VERSION 5.8 ;
BUSBITCHARS "[]" ;
DIVIDERCHAR "/" ;
UNITS
    DATABASE MICRONS 1000 ;
END UNITS

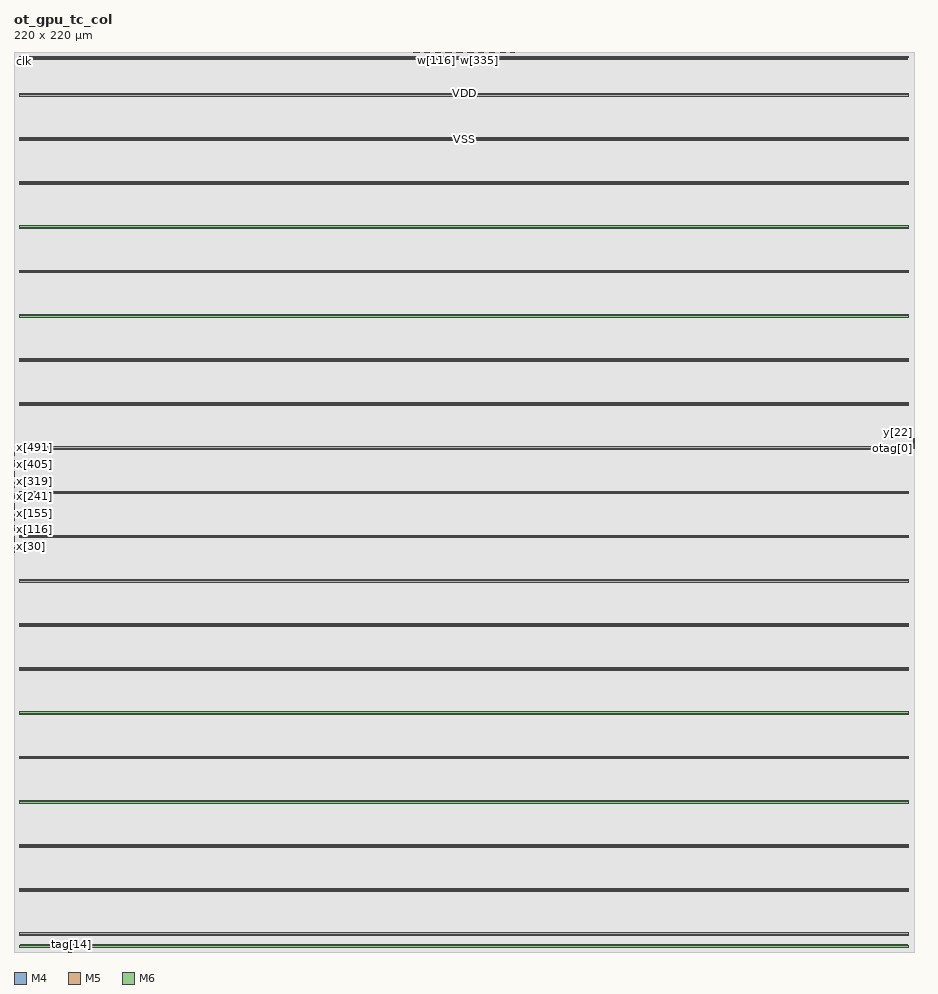
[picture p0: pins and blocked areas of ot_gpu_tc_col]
MACRO ot_gpu_tc_col
  FOREIGN ot_gpu_tc_col 0 0 ;
  CLASS BLOCK ;
  SIZE 220 BY 220 ;
  PIN clk
    DIRECTION INPUT ;
    USE SIGNAL ;
    PORT
      LAYER M4 ;
        RECT  0 217.584 0.084 217.608 ;
    END
  END clk
  PIN fault
    DIRECTION OUTPUT ;
    USE SIGNAL ;
    PORT
      LAYER M4 ;
        RECT  219.916 123.12 220 123.144 ;
    END
  END fault
  PIN first
    DIRECTION INPUT ;
    USE SIGNAL ;
    PORT
      LAYER M5 ;
        RECT  13.2 0 13.224 0.084 ;
    END
  END first
  PIN last
    DIRECTION INPUT ;
    USE SIGNAL ;
    PORT
      LAYER M5 ;
        RECT  13.248 0 13.272 0.084 ;
    END
  END last
  PIN otag[0]
    DIRECTION OUTPUT ;
    USE SIGNAL ;
    PORT
      LAYER M4 ;
        RECT  219.916 123.168 220 123.192 ;
    END
  END otag[0]
  PIN otag[10]
    DIRECTION OUTPUT ;
    USE SIGNAL ;
    PORT
      LAYER M4 ;
        RECT  219.916 123.648 220 123.672 ;
    END
  END otag[10]
  PIN otag[11]
    DIRECTION OUTPUT ;
    USE SIGNAL ;
    PORT
      LAYER M4 ;
        RECT  219.916 123.696 220 123.72 ;
    END
  END otag[11]
  PIN otag[12]
    DIRECTION OUTPUT ;
    USE SIGNAL ;
    PORT
      LAYER M4 ;
        RECT  219.916 123.744 220 123.768 ;
    END
  END otag[12]
  PIN otag[13]
    DIRECTION OUTPUT ;
    USE SIGNAL ;
    PORT
      LAYER M4 ;
        RECT  219.916 123.792 220 123.816 ;
    END
  END otag[13]
  PIN otag[14]
    DIRECTION OUTPUT ;
    USE SIGNAL ;
    PORT
      LAYER M4 ;
        RECT  219.916 123.84 220 123.864 ;
    END
  END otag[14]
  PIN otag[15]
    DIRECTION OUTPUT ;
    USE SIGNAL ;
    PORT
      LAYER M4 ;
        RECT  219.916 123.888 220 123.912 ;
    END
  END otag[15]
  PIN otag[1]
    DIRECTION OUTPUT ;
    USE SIGNAL ;
    PORT
      LAYER M4 ;
        RECT  219.916 123.216 220 123.24 ;
    END
  END otag[1]
  PIN otag[2]
    DIRECTION OUTPUT ;
    USE SIGNAL ;
    PORT
      LAYER M4 ;
        RECT  219.916 123.264 220 123.288 ;
    END
  END otag[2]
  PIN otag[3]
    DIRECTION OUTPUT ;
    USE SIGNAL ;
    PORT
      LAYER M4 ;
        RECT  219.916 123.312 220 123.336 ;
    END
  END otag[3]
  PIN otag[4]
    DIRECTION OUTPUT ;
    USE SIGNAL ;
    PORT
      LAYER M4 ;
        RECT  219.916 123.36 220 123.384 ;
    END
  END otag[4]
  PIN otag[5]
    DIRECTION OUTPUT ;
    USE SIGNAL ;
    PORT
      LAYER M4 ;
        RECT  219.916 123.408 220 123.432 ;
    END
  END otag[5]
  PIN otag[6]
    DIRECTION OUTPUT ;
    USE SIGNAL ;
    PORT
      LAYER M4 ;
        RECT  219.916 123.456 220 123.48 ;
    END
  END otag[6]
  PIN otag[7]
    DIRECTION OUTPUT ;
    USE SIGNAL ;
    PORT
      LAYER M4 ;
        RECT  219.916 123.504 220 123.528 ;
    END
  END otag[7]
  PIN otag[8]
    DIRECTION OUTPUT ;
    USE SIGNAL ;
    PORT
      LAYER M4 ;
        RECT  219.916 123.552 220 123.576 ;
    END
  END otag[8]
  PIN otag[9]
    DIRECTION OUTPUT ;
    USE SIGNAL ;
    PORT
      LAYER M4 ;
        RECT  219.916 123.6 220 123.624 ;
    END
  END otag[9]
  PIN ov
    DIRECTION OUTPUT ;
    USE SIGNAL ;
    PORT
      LAYER M4 ;
        RECT  219.916 123.936 220 123.96 ;
    END
  END ov
  PIN rst_n
    DIRECTION INPUT ;
    USE SIGNAL ;
    PORT
      LAYER M5 ;
        RECT  13.296 0 13.32 0.084 ;
    END
  END rst_n
  PIN tag[0]
    DIRECTION INPUT ;
    USE SIGNAL ;
    PORT
      LAYER M5 ;
        RECT  13.344 0 13.368 0.084 ;
    END
  END tag[0]
  PIN tag[10]
    DIRECTION INPUT ;
    USE SIGNAL ;
    PORT
      LAYER M5 ;
        RECT  13.824 0 13.848 0.084 ;
    END
  END tag[10]
  PIN tag[11]
    DIRECTION INPUT ;
    USE SIGNAL ;
    PORT
      LAYER M5 ;
        RECT  13.872 0 13.896 0.084 ;
    END
  END tag[11]
  PIN tag[12]
    DIRECTION INPUT ;
    USE SIGNAL ;
    PORT
      LAYER M5 ;
        RECT  13.92 0 13.944 0.084 ;
    END
  END tag[12]
  PIN tag[13]
    DIRECTION INPUT ;
    USE SIGNAL ;
    PORT
      LAYER M5 ;
        RECT  13.968 0 13.992 0.084 ;
    END
  END tag[13]
  PIN tag[14]
    DIRECTION INPUT ;
    USE SIGNAL ;
    PORT
      LAYER M5 ;
        RECT  14.016 0 14.04 0.084 ;
    END
  END tag[14]
  PIN tag[15]
    DIRECTION INPUT ;
    USE SIGNAL ;
    PORT
      LAYER M5 ;
        RECT  14.064 0 14.088 0.084 ;
    END
  END tag[15]
  PIN tag[1]
    DIRECTION INPUT ;
    USE SIGNAL ;
    PORT
      LAYER M5 ;
        RECT  13.392 0 13.416 0.084 ;
    END
  END tag[1]
  PIN tag[2]
    DIRECTION INPUT ;
    USE SIGNAL ;
    PORT
      LAYER M5 ;
        RECT  13.44 0 13.464 0.084 ;
    END
  END tag[2]
  PIN tag[3]
    DIRECTION INPUT ;
    USE SIGNAL ;
    PORT
      LAYER M5 ;
        RECT  13.488 0 13.512 0.084 ;
    END
  END tag[3]
  PIN tag[4]
    DIRECTION INPUT ;
    USE SIGNAL ;
    PORT
      LAYER M5 ;
        RECT  13.536 0 13.56 0.084 ;
    END
  END tag[4]
  PIN tag[5]
    DIRECTION INPUT ;
    USE SIGNAL ;
    PORT
      LAYER M5 ;
        RECT  13.584 0 13.608 0.084 ;
    END
  END tag[5]
  PIN tag[6]
    DIRECTION INPUT ;
    USE SIGNAL ;
    PORT
      LAYER M5 ;
        RECT  13.632 0 13.656 0.084 ;
    END
  END tag[6]
  PIN tag[7]
    DIRECTION INPUT ;
    USE SIGNAL ;
    PORT
      LAYER M5 ;
        RECT  13.68 0 13.704 0.084 ;
    END
  END tag[7]
  PIN tag[8]
    DIRECTION INPUT ;
    USE SIGNAL ;
    PORT
      LAYER M5 ;
        RECT  13.728 0 13.752 0.084 ;
    END
  END tag[8]
  PIN tag[9]
    DIRECTION INPUT ;
    USE SIGNAL ;
    PORT
      LAYER M5 ;
        RECT  13.776 0 13.8 0.084 ;
    END
  END tag[9]
  PIN v
    DIRECTION INPUT ;
    USE SIGNAL ;
    PORT
      LAYER M5 ;
        RECT  14.112 0 14.136 0.084 ;
    END
  END v
  PIN w[0]
    DIRECTION INPUT ;
    USE SIGNAL ;
    PORT
      LAYER M5 ;
        RECT  97.728 219.916 97.752 220 ;
    END
  END w[0]
  PIN w[100]
    DIRECTION INPUT ;
    USE SIGNAL ;
    PORT
      LAYER M5 ;
        RECT  102.528 219.916 102.552 220 ;
    END
  END w[100]
  PIN w[101]
    DIRECTION INPUT ;
    USE SIGNAL ;
    PORT
      LAYER M5 ;
        RECT  102.576 219.916 102.6 220 ;
    END
  END w[101]
  PIN w[102]
    DIRECTION INPUT ;
    USE SIGNAL ;
    PORT
      LAYER M5 ;
        RECT  102.624 219.916 102.648 220 ;
    END
  END w[102]
  PIN w[103]
    DIRECTION INPUT ;
    USE SIGNAL ;
    PORT
      LAYER M5 ;
        RECT  102.672 219.916 102.696 220 ;
    END
  END w[103]
  PIN w[104]
    DIRECTION INPUT ;
    USE SIGNAL ;
    PORT
      LAYER M5 ;
        RECT  102.72 219.916 102.744 220 ;
    END
  END w[104]
  PIN w[105]
    DIRECTION INPUT ;
    USE SIGNAL ;
    PORT
      LAYER M5 ;
        RECT  102.768 219.916 102.792 220 ;
    END
  END w[105]
  PIN w[106]
    DIRECTION INPUT ;
    USE SIGNAL ;
    PORT
      LAYER M5 ;
        RECT  102.816 219.916 102.84 220 ;
    END
  END w[106]
  PIN w[107]
    DIRECTION INPUT ;
    USE SIGNAL ;
    PORT
      LAYER M5 ;
        RECT  102.864 219.916 102.888 220 ;
    END
  END w[107]
  PIN w[108]
    DIRECTION INPUT ;
    USE SIGNAL ;
    PORT
      LAYER M5 ;
        RECT  102.912 219.916 102.936 220 ;
    END
  END w[108]
  PIN w[109]
    DIRECTION INPUT ;
    USE SIGNAL ;
    PORT
      LAYER M5 ;
        RECT  102.96 219.916 102.984 220 ;
    END
  END w[109]
  PIN w[10]
    DIRECTION INPUT ;
    USE SIGNAL ;
    PORT
      LAYER M5 ;
        RECT  98.208 219.916 98.232 220 ;
    END
  END w[10]
  PIN w[110]
    DIRECTION INPUT ;
    USE SIGNAL ;
    PORT
      LAYER M5 ;
        RECT  103.008 219.916 103.032 220 ;
    END
  END w[110]
  PIN w[111]
    DIRECTION INPUT ;
    USE SIGNAL ;
    PORT
      LAYER M5 ;
        RECT  103.056 219.916 103.08 220 ;
    END
  END w[111]
  PIN w[112]
    DIRECTION INPUT ;
    USE SIGNAL ;
    PORT
      LAYER M5 ;
        RECT  103.104 219.916 103.128 220 ;
    END
  END w[112]
  PIN w[113]
    DIRECTION INPUT ;
    USE SIGNAL ;
    PORT
      LAYER M5 ;
        RECT  103.152 219.916 103.176 220 ;
    END
  END w[113]
  PIN w[114]
    DIRECTION INPUT ;
    USE SIGNAL ;
    PORT
      LAYER M5 ;
        RECT  103.2 219.916 103.224 220 ;
    END
  END w[114]
  PIN w[115]
    DIRECTION INPUT ;
    USE SIGNAL ;
    PORT
      LAYER M5 ;
        RECT  103.248 219.916 103.272 220 ;
    END
  END w[115]
  PIN w[116]
    DIRECTION INPUT ;
    USE SIGNAL ;
    PORT
      LAYER M5 ;
        RECT  103.296 219.916 103.32 220 ;
    END
  END w[116]
  PIN w[117]
    DIRECTION INPUT ;
    USE SIGNAL ;
    PORT
      LAYER M5 ;
        RECT  103.344 219.916 103.368 220 ;
    END
  END w[117]
  PIN w[118]
    DIRECTION INPUT ;
    USE SIGNAL ;
    PORT
      LAYER M5 ;
        RECT  103.392 219.916 103.416 220 ;
    END
  END w[118]
  PIN w[119]
    DIRECTION INPUT ;
    USE SIGNAL ;
    PORT
      LAYER M5 ;
        RECT  103.44 219.916 103.464 220 ;
    END
  END w[119]
  PIN w[11]
    DIRECTION INPUT ;
    USE SIGNAL ;
    PORT
      LAYER M5 ;
        RECT  98.256 219.916 98.28 220 ;
    END
  END w[11]
  PIN w[120]
    DIRECTION INPUT ;
    USE SIGNAL ;
    PORT
      LAYER M5 ;
        RECT  103.488 219.916 103.512 220 ;
    END
  END w[120]
  PIN w[121]
    DIRECTION INPUT ;
    USE SIGNAL ;
    PORT
      LAYER M5 ;
        RECT  103.536 219.916 103.56 220 ;
    END
  END w[121]
  PIN w[122]
    DIRECTION INPUT ;
    USE SIGNAL ;
    PORT
      LAYER M5 ;
        RECT  103.584 219.916 103.608 220 ;
    END
  END w[122]
  PIN w[123]
    DIRECTION INPUT ;
    USE SIGNAL ;
    PORT
      LAYER M5 ;
        RECT  103.632 219.916 103.656 220 ;
    END
  END w[123]
  PIN w[124]
    DIRECTION INPUT ;
    USE SIGNAL ;
    PORT
      LAYER M5 ;
        RECT  103.68 219.916 103.704 220 ;
    END
  END w[124]
  PIN w[125]
    DIRECTION INPUT ;
    USE SIGNAL ;
    PORT
      LAYER M5 ;
        RECT  103.728 219.916 103.752 220 ;
    END
  END w[125]
  PIN w[126]
    DIRECTION INPUT ;
    USE SIGNAL ;
    PORT
      LAYER M5 ;
        RECT  103.776 219.916 103.8 220 ;
    END
  END w[126]
  PIN w[127]
    DIRECTION INPUT ;
    USE SIGNAL ;
    PORT
      LAYER M5 ;
        RECT  103.824 219.916 103.848 220 ;
    END
  END w[127]
  PIN w[128]
    DIRECTION INPUT ;
    USE SIGNAL ;
    PORT
      LAYER M5 ;
        RECT  103.872 219.916 103.896 220 ;
    END
  END w[128]
  PIN w[129]
    DIRECTION INPUT ;
    USE SIGNAL ;
    PORT
      LAYER M5 ;
        RECT  103.92 219.916 103.944 220 ;
    END
  END w[129]
  PIN w[12]
    DIRECTION INPUT ;
    USE SIGNAL ;
    PORT
      LAYER M5 ;
        RECT  98.304 219.916 98.328 220 ;
    END
  END w[12]
  PIN w[130]
    DIRECTION INPUT ;
    USE SIGNAL ;
    PORT
      LAYER M5 ;
        RECT  103.968 219.916 103.992 220 ;
    END
  END w[130]
  PIN w[131]
    DIRECTION INPUT ;
    USE SIGNAL ;
    PORT
      LAYER M5 ;
        RECT  104.016 219.916 104.04 220 ;
    END
  END w[131]
  PIN w[132]
    DIRECTION INPUT ;
    USE SIGNAL ;
    PORT
      LAYER M5 ;
        RECT  104.064 219.916 104.088 220 ;
    END
  END w[132]
  PIN w[133]
    DIRECTION INPUT ;
    USE SIGNAL ;
    PORT
      LAYER M5 ;
        RECT  104.112 219.916 104.136 220 ;
    END
  END w[133]
  PIN w[134]
    DIRECTION INPUT ;
    USE SIGNAL ;
    PORT
      LAYER M5 ;
        RECT  104.16 219.916 104.184 220 ;
    END
  END w[134]
  PIN w[135]
    DIRECTION INPUT ;
    USE SIGNAL ;
    PORT
      LAYER M5 ;
        RECT  104.208 219.916 104.232 220 ;
    END
  END w[135]
  PIN w[136]
    DIRECTION INPUT ;
    USE SIGNAL ;
    PORT
      LAYER M5 ;
        RECT  104.256 219.916 104.28 220 ;
    END
  END w[136]
  PIN w[137]
    DIRECTION INPUT ;
    USE SIGNAL ;
    PORT
      LAYER M5 ;
        RECT  104.304 219.916 104.328 220 ;
    END
  END w[137]
  PIN w[138]
    DIRECTION INPUT ;
    USE SIGNAL ;
    PORT
      LAYER M5 ;
        RECT  104.352 219.916 104.376 220 ;
    END
  END w[138]
  PIN w[139]
    DIRECTION INPUT ;
    USE SIGNAL ;
    PORT
      LAYER M5 ;
        RECT  104.4 219.916 104.424 220 ;
    END
  END w[139]
  PIN w[13]
    DIRECTION INPUT ;
    USE SIGNAL ;
    PORT
      LAYER M5 ;
        RECT  98.352 219.916 98.376 220 ;
    END
  END w[13]
  PIN w[140]
    DIRECTION INPUT ;
    USE SIGNAL ;
    PORT
      LAYER M5 ;
        RECT  104.448 219.916 104.472 220 ;
    END
  END w[140]
  PIN w[141]
    DIRECTION INPUT ;
    USE SIGNAL ;
    PORT
      LAYER M5 ;
        RECT  104.496 219.916 104.52 220 ;
    END
  END w[141]
  PIN w[142]
    DIRECTION INPUT ;
    USE SIGNAL ;
    PORT
      LAYER M5 ;
        RECT  104.544 219.916 104.568 220 ;
    END
  END w[142]
  PIN w[143]
    DIRECTION INPUT ;
    USE SIGNAL ;
    PORT
      LAYER M5 ;
        RECT  104.592 219.916 104.616 220 ;
    END
  END w[143]
  PIN w[144]
    DIRECTION INPUT ;
    USE SIGNAL ;
    PORT
      LAYER M5 ;
        RECT  104.64 219.916 104.664 220 ;
    END
  END w[144]
  PIN w[145]
    DIRECTION INPUT ;
    USE SIGNAL ;
    PORT
      LAYER M5 ;
        RECT  104.688 219.916 104.712 220 ;
    END
  END w[145]
  PIN w[146]
    DIRECTION INPUT ;
    USE SIGNAL ;
    PORT
      LAYER M5 ;
        RECT  104.736 219.916 104.76 220 ;
    END
  END w[146]
  PIN w[147]
    DIRECTION INPUT ;
    USE SIGNAL ;
    PORT
      LAYER M5 ;
        RECT  104.784 219.916 104.808 220 ;
    END
  END w[147]
  PIN w[148]
    DIRECTION INPUT ;
    USE SIGNAL ;
    PORT
      LAYER M5 ;
        RECT  104.832 219.916 104.856 220 ;
    END
  END w[148]
  PIN w[149]
    DIRECTION INPUT ;
    USE SIGNAL ;
    PORT
      LAYER M5 ;
        RECT  104.88 219.916 104.904 220 ;
    END
  END w[149]
  PIN w[14]
    DIRECTION INPUT ;
    USE SIGNAL ;
    PORT
      LAYER M5 ;
        RECT  98.4 219.916 98.424 220 ;
    END
  END w[14]
  PIN w[150]
    DIRECTION INPUT ;
    USE SIGNAL ;
    PORT
      LAYER M5 ;
        RECT  104.928 219.916 104.952 220 ;
    END
  END w[150]
  PIN w[151]
    DIRECTION INPUT ;
    USE SIGNAL ;
    PORT
      LAYER M5 ;
        RECT  104.976 219.916 105 220 ;
    END
  END w[151]
  PIN w[152]
    DIRECTION INPUT ;
    USE SIGNAL ;
    PORT
      LAYER M5 ;
        RECT  105.024 219.916 105.048 220 ;
    END
  END w[152]
  PIN w[153]
    DIRECTION INPUT ;
    USE SIGNAL ;
    PORT
      LAYER M5 ;
        RECT  105.072 219.916 105.096 220 ;
    END
  END w[153]
  PIN w[154]
    DIRECTION INPUT ;
    USE SIGNAL ;
    PORT
      LAYER M5 ;
        RECT  105.12 219.916 105.144 220 ;
    END
  END w[154]
  PIN w[155]
    DIRECTION INPUT ;
    USE SIGNAL ;
    PORT
      LAYER M5 ;
        RECT  105.168 219.916 105.192 220 ;
    END
  END w[155]
  PIN w[156]
    DIRECTION INPUT ;
    USE SIGNAL ;
    PORT
      LAYER M5 ;
        RECT  105.216 219.916 105.24 220 ;
    END
  END w[156]
  PIN w[157]
    DIRECTION INPUT ;
    USE SIGNAL ;
    PORT
      LAYER M5 ;
        RECT  105.264 219.916 105.288 220 ;
    END
  END w[157]
  PIN w[158]
    DIRECTION INPUT ;
    USE SIGNAL ;
    PORT
      LAYER M5 ;
        RECT  105.312 219.916 105.336 220 ;
    END
  END w[158]
  PIN w[159]
    DIRECTION INPUT ;
    USE SIGNAL ;
    PORT
      LAYER M5 ;
        RECT  105.36 219.916 105.384 220 ;
    END
  END w[159]
  PIN w[15]
    DIRECTION INPUT ;
    USE SIGNAL ;
    PORT
      LAYER M5 ;
        RECT  98.448 219.916 98.472 220 ;
    END
  END w[15]
  PIN w[160]
    DIRECTION INPUT ;
    USE SIGNAL ;
    PORT
      LAYER M5 ;
        RECT  105.408 219.916 105.432 220 ;
    END
  END w[160]
  PIN w[161]
    DIRECTION INPUT ;
    USE SIGNAL ;
    PORT
      LAYER M5 ;
        RECT  105.456 219.916 105.48 220 ;
    END
  END w[161]
  PIN w[162]
    DIRECTION INPUT ;
    USE SIGNAL ;
    PORT
      LAYER M5 ;
        RECT  105.504 219.916 105.528 220 ;
    END
  END w[162]
  PIN w[163]
    DIRECTION INPUT ;
    USE SIGNAL ;
    PORT
      LAYER M5 ;
        RECT  105.552 219.916 105.576 220 ;
    END
  END w[163]
  PIN w[164]
    DIRECTION INPUT ;
    USE SIGNAL ;
    PORT
      LAYER M5 ;
        RECT  105.6 219.916 105.624 220 ;
    END
  END w[164]
  PIN w[165]
    DIRECTION INPUT ;
    USE SIGNAL ;
    PORT
      LAYER M5 ;
        RECT  105.648 219.916 105.672 220 ;
    END
  END w[165]
  PIN w[166]
    DIRECTION INPUT ;
    USE SIGNAL ;
    PORT
      LAYER M5 ;
        RECT  105.696 219.916 105.72 220 ;
    END
  END w[166]
  PIN w[167]
    DIRECTION INPUT ;
    USE SIGNAL ;
    PORT
      LAYER M5 ;
        RECT  105.744 219.916 105.768 220 ;
    END
  END w[167]
  PIN w[168]
    DIRECTION INPUT ;
    USE SIGNAL ;
    PORT
      LAYER M5 ;
        RECT  105.792 219.916 105.816 220 ;
    END
  END w[168]
  PIN w[169]
    DIRECTION INPUT ;
    USE SIGNAL ;
    PORT
      LAYER M5 ;
        RECT  105.84 219.916 105.864 220 ;
    END
  END w[169]
  PIN w[16]
    DIRECTION INPUT ;
    USE SIGNAL ;
    PORT
      LAYER M5 ;
        RECT  98.496 219.916 98.52 220 ;
    END
  END w[16]
  PIN w[170]
    DIRECTION INPUT ;
    USE SIGNAL ;
    PORT
      LAYER M5 ;
        RECT  105.888 219.916 105.912 220 ;
    END
  END w[170]
  PIN w[171]
    DIRECTION INPUT ;
    USE SIGNAL ;
    PORT
      LAYER M5 ;
        RECT  105.936 219.916 105.96 220 ;
    END
  END w[171]
  PIN w[172]
    DIRECTION INPUT ;
    USE SIGNAL ;
    PORT
      LAYER M5 ;
        RECT  105.984 219.916 106.008 220 ;
    END
  END w[172]
  PIN w[173]
    DIRECTION INPUT ;
    USE SIGNAL ;
    PORT
      LAYER M5 ;
        RECT  106.032 219.916 106.056 220 ;
    END
  END w[173]
  PIN w[174]
    DIRECTION INPUT ;
    USE SIGNAL ;
    PORT
      LAYER M5 ;
        RECT  106.08 219.916 106.104 220 ;
    END
  END w[174]
  PIN w[175]
    DIRECTION INPUT ;
    USE SIGNAL ;
    PORT
      LAYER M5 ;
        RECT  106.128 219.916 106.152 220 ;
    END
  END w[175]
  PIN w[176]
    DIRECTION INPUT ;
    USE SIGNAL ;
    PORT
      LAYER M5 ;
        RECT  106.176 219.916 106.2 220 ;
    END
  END w[176]
  PIN w[177]
    DIRECTION INPUT ;
    USE SIGNAL ;
    PORT
      LAYER M5 ;
        RECT  106.224 219.916 106.248 220 ;
    END
  END w[177]
  PIN w[178]
    DIRECTION INPUT ;
    USE SIGNAL ;
    PORT
      LAYER M5 ;
        RECT  106.272 219.916 106.296 220 ;
    END
  END w[178]
  PIN w[179]
    DIRECTION INPUT ;
    USE SIGNAL ;
    PORT
      LAYER M5 ;
        RECT  106.32 219.916 106.344 220 ;
    END
  END w[179]
  PIN w[17]
    DIRECTION INPUT ;
    USE SIGNAL ;
    PORT
      LAYER M5 ;
        RECT  98.544 219.916 98.568 220 ;
    END
  END w[17]
  PIN w[180]
    DIRECTION INPUT ;
    USE SIGNAL ;
    PORT
      LAYER M5 ;
        RECT  106.368 219.916 106.392 220 ;
    END
  END w[180]
  PIN w[181]
    DIRECTION INPUT ;
    USE SIGNAL ;
    PORT
      LAYER M5 ;
        RECT  106.416 219.916 106.44 220 ;
    END
  END w[181]
  PIN w[182]
    DIRECTION INPUT ;
    USE SIGNAL ;
    PORT
      LAYER M5 ;
        RECT  106.464 219.916 106.488 220 ;
    END
  END w[182]
  PIN w[183]
    DIRECTION INPUT ;
    USE SIGNAL ;
    PORT
      LAYER M5 ;
        RECT  106.512 219.916 106.536 220 ;
    END
  END w[183]
  PIN w[184]
    DIRECTION INPUT ;
    USE SIGNAL ;
    PORT
      LAYER M5 ;
        RECT  106.56 219.916 106.584 220 ;
    END
  END w[184]
  PIN w[185]
    DIRECTION INPUT ;
    USE SIGNAL ;
    PORT
      LAYER M5 ;
        RECT  106.608 219.916 106.632 220 ;
    END
  END w[185]
  PIN w[186]
    DIRECTION INPUT ;
    USE SIGNAL ;
    PORT
      LAYER M5 ;
        RECT  106.656 219.916 106.68 220 ;
    END
  END w[186]
  PIN w[187]
    DIRECTION INPUT ;
    USE SIGNAL ;
    PORT
      LAYER M5 ;
        RECT  106.704 219.916 106.728 220 ;
    END
  END w[187]
  PIN w[188]
    DIRECTION INPUT ;
    USE SIGNAL ;
    PORT
      LAYER M5 ;
        RECT  106.752 219.916 106.776 220 ;
    END
  END w[188]
  PIN w[189]
    DIRECTION INPUT ;
    USE SIGNAL ;
    PORT
      LAYER M5 ;
        RECT  106.8 219.916 106.824 220 ;
    END
  END w[189]
  PIN w[18]
    DIRECTION INPUT ;
    USE SIGNAL ;
    PORT
      LAYER M5 ;
        RECT  98.592 219.916 98.616 220 ;
    END
  END w[18]
  PIN w[190]
    DIRECTION INPUT ;
    USE SIGNAL ;
    PORT
      LAYER M5 ;
        RECT  106.848 219.916 106.872 220 ;
    END
  END w[190]
  PIN w[191]
    DIRECTION INPUT ;
    USE SIGNAL ;
    PORT
      LAYER M5 ;
        RECT  106.896 219.916 106.92 220 ;
    END
  END w[191]
  PIN w[192]
    DIRECTION INPUT ;
    USE SIGNAL ;
    PORT
      LAYER M5 ;
        RECT  106.944 219.916 106.968 220 ;
    END
  END w[192]
  PIN w[193]
    DIRECTION INPUT ;
    USE SIGNAL ;
    PORT
      LAYER M5 ;
        RECT  106.992 219.916 107.016 220 ;
    END
  END w[193]
  PIN w[194]
    DIRECTION INPUT ;
    USE SIGNAL ;
    PORT
      LAYER M5 ;
        RECT  107.04 219.916 107.064 220 ;
    END
  END w[194]
  PIN w[195]
    DIRECTION INPUT ;
    USE SIGNAL ;
    PORT
      LAYER M5 ;
        RECT  107.088 219.916 107.112 220 ;
    END
  END w[195]
  PIN w[196]
    DIRECTION INPUT ;
    USE SIGNAL ;
    PORT
      LAYER M5 ;
        RECT  107.136 219.916 107.16 220 ;
    END
  END w[196]
  PIN w[197]
    DIRECTION INPUT ;
    USE SIGNAL ;
    PORT
      LAYER M5 ;
        RECT  107.184 219.916 107.208 220 ;
    END
  END w[197]
  PIN w[198]
    DIRECTION INPUT ;
    USE SIGNAL ;
    PORT
      LAYER M5 ;
        RECT  107.232 219.916 107.256 220 ;
    END
  END w[198]
  PIN w[199]
    DIRECTION INPUT ;
    USE SIGNAL ;
    PORT
      LAYER M5 ;
        RECT  107.28 219.916 107.304 220 ;
    END
  END w[199]
  PIN w[19]
    DIRECTION INPUT ;
    USE SIGNAL ;
    PORT
      LAYER M5 ;
        RECT  98.64 219.916 98.664 220 ;
    END
  END w[19]
  PIN w[1]
    DIRECTION INPUT ;
    USE SIGNAL ;
    PORT
      LAYER M5 ;
        RECT  97.776 219.916 97.8 220 ;
    END
  END w[1]
  PIN w[200]
    DIRECTION INPUT ;
    USE SIGNAL ;
    PORT
      LAYER M5 ;
        RECT  107.328 219.916 107.352 220 ;
    END
  END w[200]
  PIN w[201]
    DIRECTION INPUT ;
    USE SIGNAL ;
    PORT
      LAYER M5 ;
        RECT  107.376 219.916 107.4 220 ;
    END
  END w[201]
  PIN w[202]
    DIRECTION INPUT ;
    USE SIGNAL ;
    PORT
      LAYER M5 ;
        RECT  107.424 219.916 107.448 220 ;
    END
  END w[202]
  PIN w[203]
    DIRECTION INPUT ;
    USE SIGNAL ;
    PORT
      LAYER M5 ;
        RECT  107.472 219.916 107.496 220 ;
    END
  END w[203]
  PIN w[204]
    DIRECTION INPUT ;
    USE SIGNAL ;
    PORT
      LAYER M5 ;
        RECT  107.52 219.916 107.544 220 ;
    END
  END w[204]
  PIN w[205]
    DIRECTION INPUT ;
    USE SIGNAL ;
    PORT
      LAYER M5 ;
        RECT  107.568 219.916 107.592 220 ;
    END
  END w[205]
  PIN w[206]
    DIRECTION INPUT ;
    USE SIGNAL ;
    PORT
      LAYER M5 ;
        RECT  107.616 219.916 107.64 220 ;
    END
  END w[206]
  PIN w[207]
    DIRECTION INPUT ;
    USE SIGNAL ;
    PORT
      LAYER M5 ;
        RECT  107.664 219.916 107.688 220 ;
    END
  END w[207]
  PIN w[208]
    DIRECTION INPUT ;
    USE SIGNAL ;
    PORT
      LAYER M5 ;
        RECT  107.712 219.916 107.736 220 ;
    END
  END w[208]
  PIN w[209]
    DIRECTION INPUT ;
    USE SIGNAL ;
    PORT
      LAYER M5 ;
        RECT  107.76 219.916 107.784 220 ;
    END
  END w[209]
  PIN w[20]
    DIRECTION INPUT ;
    USE SIGNAL ;
    PORT
      LAYER M5 ;
        RECT  98.688 219.916 98.712 220 ;
    END
  END w[20]
  PIN w[210]
    DIRECTION INPUT ;
    USE SIGNAL ;
    PORT
      LAYER M5 ;
        RECT  107.808 219.916 107.832 220 ;
    END
  END w[210]
  PIN w[211]
    DIRECTION INPUT ;
    USE SIGNAL ;
    PORT
      LAYER M5 ;
        RECT  107.856 219.916 107.88 220 ;
    END
  END w[211]
  PIN w[212]
    DIRECTION INPUT ;
    USE SIGNAL ;
    PORT
      LAYER M5 ;
        RECT  107.904 219.916 107.928 220 ;
    END
  END w[212]
  PIN w[213]
    DIRECTION INPUT ;
    USE SIGNAL ;
    PORT
      LAYER M5 ;
        RECT  107.952 219.916 107.976 220 ;
    END
  END w[213]
  PIN w[214]
    DIRECTION INPUT ;
    USE SIGNAL ;
    PORT
      LAYER M5 ;
        RECT  108 219.916 108.024 220 ;
    END
  END w[214]
  PIN w[215]
    DIRECTION INPUT ;
    USE SIGNAL ;
    PORT
      LAYER M5 ;
        RECT  108.048 219.916 108.072 220 ;
    END
  END w[215]
  PIN w[216]
    DIRECTION INPUT ;
    USE SIGNAL ;
    PORT
      LAYER M5 ;
        RECT  108.096 219.916 108.12 220 ;
    END
  END w[216]
  PIN w[217]
    DIRECTION INPUT ;
    USE SIGNAL ;
    PORT
      LAYER M5 ;
        RECT  108.144 219.916 108.168 220 ;
    END
  END w[217]
  PIN w[218]
    DIRECTION INPUT ;
    USE SIGNAL ;
    PORT
      LAYER M5 ;
        RECT  108.192 219.916 108.216 220 ;
    END
  END w[218]
  PIN w[219]
    DIRECTION INPUT ;
    USE SIGNAL ;
    PORT
      LAYER M5 ;
        RECT  108.24 219.916 108.264 220 ;
    END
  END w[219]
  PIN w[21]
    DIRECTION INPUT ;
    USE SIGNAL ;
    PORT
      LAYER M5 ;
        RECT  98.736 219.916 98.76 220 ;
    END
  END w[21]
  PIN w[220]
    DIRECTION INPUT ;
    USE SIGNAL ;
    PORT
      LAYER M5 ;
        RECT  108.288 219.916 108.312 220 ;
    END
  END w[220]
  PIN w[221]
    DIRECTION INPUT ;
    USE SIGNAL ;
    PORT
      LAYER M5 ;
        RECT  108.336 219.916 108.36 220 ;
    END
  END w[221]
  PIN w[222]
    DIRECTION INPUT ;
    USE SIGNAL ;
    PORT
      LAYER M5 ;
        RECT  108.384 219.916 108.408 220 ;
    END
  END w[222]
  PIN w[223]
    DIRECTION INPUT ;
    USE SIGNAL ;
    PORT
      LAYER M5 ;
        RECT  108.432 219.916 108.456 220 ;
    END
  END w[223]
  PIN w[224]
    DIRECTION INPUT ;
    USE SIGNAL ;
    PORT
      LAYER M5 ;
        RECT  108.48 219.916 108.504 220 ;
    END
  END w[224]
  PIN w[225]
    DIRECTION INPUT ;
    USE SIGNAL ;
    PORT
      LAYER M5 ;
        RECT  108.528 219.916 108.552 220 ;
    END
  END w[225]
  PIN w[226]
    DIRECTION INPUT ;
    USE SIGNAL ;
    PORT
      LAYER M5 ;
        RECT  108.576 219.916 108.6 220 ;
    END
  END w[226]
  PIN w[227]
    DIRECTION INPUT ;
    USE SIGNAL ;
    PORT
      LAYER M5 ;
        RECT  108.624 219.916 108.648 220 ;
    END
  END w[227]
  PIN w[228]
    DIRECTION INPUT ;
    USE SIGNAL ;
    PORT
      LAYER M5 ;
        RECT  108.672 219.916 108.696 220 ;
    END
  END w[228]
  PIN w[229]
    DIRECTION INPUT ;
    USE SIGNAL ;
    PORT
      LAYER M5 ;
        RECT  108.72 219.916 108.744 220 ;
    END
  END w[229]
  PIN w[22]
    DIRECTION INPUT ;
    USE SIGNAL ;
    PORT
      LAYER M5 ;
        RECT  98.784 219.916 98.808 220 ;
    END
  END w[22]
  PIN w[230]
    DIRECTION INPUT ;
    USE SIGNAL ;
    PORT
      LAYER M5 ;
        RECT  108.768 219.916 108.792 220 ;
    END
  END w[230]
  PIN w[231]
    DIRECTION INPUT ;
    USE SIGNAL ;
    PORT
      LAYER M5 ;
        RECT  108.816 219.916 108.84 220 ;
    END
  END w[231]
  PIN w[232]
    DIRECTION INPUT ;
    USE SIGNAL ;
    PORT
      LAYER M5 ;
        RECT  108.864 219.916 108.888 220 ;
    END
  END w[232]
  PIN w[233]
    DIRECTION INPUT ;
    USE SIGNAL ;
    PORT
      LAYER M5 ;
        RECT  108.912 219.916 108.936 220 ;
    END
  END w[233]
  PIN w[234]
    DIRECTION INPUT ;
    USE SIGNAL ;
    PORT
      LAYER M5 ;
        RECT  108.96 219.916 108.984 220 ;
    END
  END w[234]
  PIN w[235]
    DIRECTION INPUT ;
    USE SIGNAL ;
    PORT
      LAYER M5 ;
        RECT  109.008 219.916 109.032 220 ;
    END
  END w[235]
  PIN w[236]
    DIRECTION INPUT ;
    USE SIGNAL ;
    PORT
      LAYER M5 ;
        RECT  109.056 219.916 109.08 220 ;
    END
  END w[236]
  PIN w[237]
    DIRECTION INPUT ;
    USE SIGNAL ;
    PORT
      LAYER M5 ;
        RECT  109.104 219.916 109.128 220 ;
    END
  END w[237]
  PIN w[238]
    DIRECTION INPUT ;
    USE SIGNAL ;
    PORT
      LAYER M5 ;
        RECT  109.152 219.916 109.176 220 ;
    END
  END w[238]
  PIN w[239]
    DIRECTION INPUT ;
    USE SIGNAL ;
    PORT
      LAYER M5 ;
        RECT  109.2 219.916 109.224 220 ;
    END
  END w[239]
  PIN w[23]
    DIRECTION INPUT ;
    USE SIGNAL ;
    PORT
      LAYER M5 ;
        RECT  98.832 219.916 98.856 220 ;
    END
  END w[23]
  PIN w[240]
    DIRECTION INPUT ;
    USE SIGNAL ;
    PORT
      LAYER M5 ;
        RECT  109.248 219.916 109.272 220 ;
    END
  END w[240]
  PIN w[241]
    DIRECTION INPUT ;
    USE SIGNAL ;
    PORT
      LAYER M5 ;
        RECT  109.296 219.916 109.32 220 ;
    END
  END w[241]
  PIN w[242]
    DIRECTION INPUT ;
    USE SIGNAL ;
    PORT
      LAYER M5 ;
        RECT  109.344 219.916 109.368 220 ;
    END
  END w[242]
  PIN w[243]
    DIRECTION INPUT ;
    USE SIGNAL ;
    PORT
      LAYER M5 ;
        RECT  109.392 219.916 109.416 220 ;
    END
  END w[243]
  PIN w[244]
    DIRECTION INPUT ;
    USE SIGNAL ;
    PORT
      LAYER M5 ;
        RECT  109.44 219.916 109.464 220 ;
    END
  END w[244]
  PIN w[245]
    DIRECTION INPUT ;
    USE SIGNAL ;
    PORT
      LAYER M5 ;
        RECT  109.488 219.916 109.512 220 ;
    END
  END w[245]
  PIN w[246]
    DIRECTION INPUT ;
    USE SIGNAL ;
    PORT
      LAYER M5 ;
        RECT  109.536 219.916 109.56 220 ;
    END
  END w[246]
  PIN w[247]
    DIRECTION INPUT ;
    USE SIGNAL ;
    PORT
      LAYER M5 ;
        RECT  109.584 219.916 109.608 220 ;
    END
  END w[247]
  PIN w[248]
    DIRECTION INPUT ;
    USE SIGNAL ;
    PORT
      LAYER M5 ;
        RECT  109.632 219.916 109.656 220 ;
    END
  END w[248]
  PIN w[249]
    DIRECTION INPUT ;
    USE SIGNAL ;
    PORT
      LAYER M5 ;
        RECT  109.68 219.916 109.704 220 ;
    END
  END w[249]
  PIN w[24]
    DIRECTION INPUT ;
    USE SIGNAL ;
    PORT
      LAYER M5 ;
        RECT  98.88 219.916 98.904 220 ;
    END
  END w[24]
  PIN w[250]
    DIRECTION INPUT ;
    USE SIGNAL ;
    PORT
      LAYER M5 ;
        RECT  109.728 219.916 109.752 220 ;
    END
  END w[250]
  PIN w[251]
    DIRECTION INPUT ;
    USE SIGNAL ;
    PORT
      LAYER M5 ;
        RECT  109.776 219.916 109.8 220 ;
    END
  END w[251]
  PIN w[252]
    DIRECTION INPUT ;
    USE SIGNAL ;
    PORT
      LAYER M5 ;
        RECT  109.824 219.916 109.848 220 ;
    END
  END w[252]
  PIN w[253]
    DIRECTION INPUT ;
    USE SIGNAL ;
    PORT
      LAYER M5 ;
        RECT  109.872 219.916 109.896 220 ;
    END
  END w[253]
  PIN w[254]
    DIRECTION INPUT ;
    USE SIGNAL ;
    PORT
      LAYER M5 ;
        RECT  109.92 219.916 109.944 220 ;
    END
  END w[254]
  PIN w[255]
    DIRECTION INPUT ;
    USE SIGNAL ;
    PORT
      LAYER M5 ;
        RECT  109.968 219.916 109.992 220 ;
    END
  END w[255]
  PIN w[256]
    DIRECTION INPUT ;
    USE SIGNAL ;
    PORT
      LAYER M5 ;
        RECT  110.016 219.916 110.04 220 ;
    END
  END w[256]
  PIN w[257]
    DIRECTION INPUT ;
    USE SIGNAL ;
    PORT
      LAYER M5 ;
        RECT  110.064 219.916 110.088 220 ;
    END
  END w[257]
  PIN w[258]
    DIRECTION INPUT ;
    USE SIGNAL ;
    PORT
      LAYER M5 ;
        RECT  110.112 219.916 110.136 220 ;
    END
  END w[258]
  PIN w[259]
    DIRECTION INPUT ;
    USE SIGNAL ;
    PORT
      LAYER M5 ;
        RECT  110.16 219.916 110.184 220 ;
    END
  END w[259]
  PIN w[25]
    DIRECTION INPUT ;
    USE SIGNAL ;
    PORT
      LAYER M5 ;
        RECT  98.928 219.916 98.952 220 ;
    END
  END w[25]
  PIN w[260]
    DIRECTION INPUT ;
    USE SIGNAL ;
    PORT
      LAYER M5 ;
        RECT  110.208 219.916 110.232 220 ;
    END
  END w[260]
  PIN w[261]
    DIRECTION INPUT ;
    USE SIGNAL ;
    PORT
      LAYER M5 ;
        RECT  110.256 219.916 110.28 220 ;
    END
  END w[261]
  PIN w[262]
    DIRECTION INPUT ;
    USE SIGNAL ;
    PORT
      LAYER M5 ;
        RECT  110.304 219.916 110.328 220 ;
    END
  END w[262]
  PIN w[263]
    DIRECTION INPUT ;
    USE SIGNAL ;
    PORT
      LAYER M5 ;
        RECT  110.352 219.916 110.376 220 ;
    END
  END w[263]
  PIN w[264]
    DIRECTION INPUT ;
    USE SIGNAL ;
    PORT
      LAYER M5 ;
        RECT  110.4 219.916 110.424 220 ;
    END
  END w[264]
  PIN w[265]
    DIRECTION INPUT ;
    USE SIGNAL ;
    PORT
      LAYER M5 ;
        RECT  110.448 219.916 110.472 220 ;
    END
  END w[265]
  PIN w[266]
    DIRECTION INPUT ;
    USE SIGNAL ;
    PORT
      LAYER M5 ;
        RECT  110.496 219.916 110.52 220 ;
    END
  END w[266]
  PIN w[267]
    DIRECTION INPUT ;
    USE SIGNAL ;
    PORT
      LAYER M5 ;
        RECT  110.544 219.916 110.568 220 ;
    END
  END w[267]
  PIN w[268]
    DIRECTION INPUT ;
    USE SIGNAL ;
    PORT
      LAYER M5 ;
        RECT  110.592 219.916 110.616 220 ;
    END
  END w[268]
  PIN w[269]
    DIRECTION INPUT ;
    USE SIGNAL ;
    PORT
      LAYER M5 ;
        RECT  110.64 219.916 110.664 220 ;
    END
  END w[269]
  PIN w[26]
    DIRECTION INPUT ;
    USE SIGNAL ;
    PORT
      LAYER M5 ;
        RECT  98.976 219.916 99 220 ;
    END
  END w[26]
  PIN w[270]
    DIRECTION INPUT ;
    USE SIGNAL ;
    PORT
      LAYER M5 ;
        RECT  110.688 219.916 110.712 220 ;
    END
  END w[270]
  PIN w[271]
    DIRECTION INPUT ;
    USE SIGNAL ;
    PORT
      LAYER M5 ;
        RECT  110.736 219.916 110.76 220 ;
    END
  END w[271]
  PIN w[272]
    DIRECTION INPUT ;
    USE SIGNAL ;
    PORT
      LAYER M5 ;
        RECT  110.784 219.916 110.808 220 ;
    END
  END w[272]
  PIN w[273]
    DIRECTION INPUT ;
    USE SIGNAL ;
    PORT
      LAYER M5 ;
        RECT  110.832 219.916 110.856 220 ;
    END
  END w[273]
  PIN w[274]
    DIRECTION INPUT ;
    USE SIGNAL ;
    PORT
      LAYER M5 ;
        RECT  110.88 219.916 110.904 220 ;
    END
  END w[274]
  PIN w[275]
    DIRECTION INPUT ;
    USE SIGNAL ;
    PORT
      LAYER M5 ;
        RECT  110.928 219.916 110.952 220 ;
    END
  END w[275]
  PIN w[276]
    DIRECTION INPUT ;
    USE SIGNAL ;
    PORT
      LAYER M5 ;
        RECT  110.976 219.916 111 220 ;
    END
  END w[276]
  PIN w[277]
    DIRECTION INPUT ;
    USE SIGNAL ;
    PORT
      LAYER M5 ;
        RECT  111.024 219.916 111.048 220 ;
    END
  END w[277]
  PIN w[278]
    DIRECTION INPUT ;
    USE SIGNAL ;
    PORT
      LAYER M5 ;
        RECT  111.072 219.916 111.096 220 ;
    END
  END w[278]
  PIN w[279]
    DIRECTION INPUT ;
    USE SIGNAL ;
    PORT
      LAYER M5 ;
        RECT  111.12 219.916 111.144 220 ;
    END
  END w[279]
  PIN w[27]
    DIRECTION INPUT ;
    USE SIGNAL ;
    PORT
      LAYER M5 ;
        RECT  99.024 219.916 99.048 220 ;
    END
  END w[27]
  PIN w[280]
    DIRECTION INPUT ;
    USE SIGNAL ;
    PORT
      LAYER M5 ;
        RECT  111.168 219.916 111.192 220 ;
    END
  END w[280]
  PIN w[281]
    DIRECTION INPUT ;
    USE SIGNAL ;
    PORT
      LAYER M5 ;
        RECT  111.216 219.916 111.24 220 ;
    END
  END w[281]
  PIN w[282]
    DIRECTION INPUT ;
    USE SIGNAL ;
    PORT
      LAYER M5 ;
        RECT  111.264 219.916 111.288 220 ;
    END
  END w[282]
  PIN w[283]
    DIRECTION INPUT ;
    USE SIGNAL ;
    PORT
      LAYER M5 ;
        RECT  111.312 219.916 111.336 220 ;
    END
  END w[283]
  PIN w[284]
    DIRECTION INPUT ;
    USE SIGNAL ;
    PORT
      LAYER M5 ;
        RECT  111.36 219.916 111.384 220 ;
    END
  END w[284]
  PIN w[285]
    DIRECTION INPUT ;
    USE SIGNAL ;
    PORT
      LAYER M5 ;
        RECT  111.408 219.916 111.432 220 ;
    END
  END w[285]
  PIN w[286]
    DIRECTION INPUT ;
    USE SIGNAL ;
    PORT
      LAYER M5 ;
        RECT  111.456 219.916 111.48 220 ;
    END
  END w[286]
  PIN w[287]
    DIRECTION INPUT ;
    USE SIGNAL ;
    PORT
      LAYER M5 ;
        RECT  111.504 219.916 111.528 220 ;
    END
  END w[287]
  PIN w[288]
    DIRECTION INPUT ;
    USE SIGNAL ;
    PORT
      LAYER M5 ;
        RECT  111.552 219.916 111.576 220 ;
    END
  END w[288]
  PIN w[289]
    DIRECTION INPUT ;
    USE SIGNAL ;
    PORT
      LAYER M5 ;
        RECT  111.6 219.916 111.624 220 ;
    END
  END w[289]
  PIN w[28]
    DIRECTION INPUT ;
    USE SIGNAL ;
    PORT
      LAYER M5 ;
        RECT  99.072 219.916 99.096 220 ;
    END
  END w[28]
  PIN w[290]
    DIRECTION INPUT ;
    USE SIGNAL ;
    PORT
      LAYER M5 ;
        RECT  111.648 219.916 111.672 220 ;
    END
  END w[290]
  PIN w[291]
    DIRECTION INPUT ;
    USE SIGNAL ;
    PORT
      LAYER M5 ;
        RECT  111.696 219.916 111.72 220 ;
    END
  END w[291]
  PIN w[292]
    DIRECTION INPUT ;
    USE SIGNAL ;
    PORT
      LAYER M5 ;
        RECT  111.744 219.916 111.768 220 ;
    END
  END w[292]
  PIN w[293]
    DIRECTION INPUT ;
    USE SIGNAL ;
    PORT
      LAYER M5 ;
        RECT  111.792 219.916 111.816 220 ;
    END
  END w[293]
  PIN w[294]
    DIRECTION INPUT ;
    USE SIGNAL ;
    PORT
      LAYER M5 ;
        RECT  111.84 219.916 111.864 220 ;
    END
  END w[294]
  PIN w[295]
    DIRECTION INPUT ;
    USE SIGNAL ;
    PORT
      LAYER M5 ;
        RECT  111.888 219.916 111.912 220 ;
    END
  END w[295]
  PIN w[296]
    DIRECTION INPUT ;
    USE SIGNAL ;
    PORT
      LAYER M5 ;
        RECT  111.936 219.916 111.96 220 ;
    END
  END w[296]
  PIN w[297]
    DIRECTION INPUT ;
    USE SIGNAL ;
    PORT
      LAYER M5 ;
        RECT  111.984 219.916 112.008 220 ;
    END
  END w[297]
  PIN w[298]
    DIRECTION INPUT ;
    USE SIGNAL ;
    PORT
      LAYER M5 ;
        RECT  112.032 219.916 112.056 220 ;
    END
  END w[298]
  PIN w[299]
    DIRECTION INPUT ;
    USE SIGNAL ;
    PORT
      LAYER M5 ;
        RECT  112.08 219.916 112.104 220 ;
    END
  END w[299]
  PIN w[29]
    DIRECTION INPUT ;
    USE SIGNAL ;
    PORT
      LAYER M5 ;
        RECT  99.12 219.916 99.144 220 ;
    END
  END w[29]
  PIN w[2]
    DIRECTION INPUT ;
    USE SIGNAL ;
    PORT
      LAYER M5 ;
        RECT  97.824 219.916 97.848 220 ;
    END
  END w[2]
  PIN w[300]
    DIRECTION INPUT ;
    USE SIGNAL ;
    PORT
      LAYER M5 ;
        RECT  112.128 219.916 112.152 220 ;
    END
  END w[300]
  PIN w[301]
    DIRECTION INPUT ;
    USE SIGNAL ;
    PORT
      LAYER M5 ;
        RECT  112.176 219.916 112.2 220 ;
    END
  END w[301]
  PIN w[302]
    DIRECTION INPUT ;
    USE SIGNAL ;
    PORT
      LAYER M5 ;
        RECT  112.224 219.916 112.248 220 ;
    END
  END w[302]
  PIN w[303]
    DIRECTION INPUT ;
    USE SIGNAL ;
    PORT
      LAYER M5 ;
        RECT  112.272 219.916 112.296 220 ;
    END
  END w[303]
  PIN w[304]
    DIRECTION INPUT ;
    USE SIGNAL ;
    PORT
      LAYER M5 ;
        RECT  112.32 219.916 112.344 220 ;
    END
  END w[304]
  PIN w[305]
    DIRECTION INPUT ;
    USE SIGNAL ;
    PORT
      LAYER M5 ;
        RECT  112.368 219.916 112.392 220 ;
    END
  END w[305]
  PIN w[306]
    DIRECTION INPUT ;
    USE SIGNAL ;
    PORT
      LAYER M5 ;
        RECT  112.416 219.916 112.44 220 ;
    END
  END w[306]
  PIN w[307]
    DIRECTION INPUT ;
    USE SIGNAL ;
    PORT
      LAYER M5 ;
        RECT  112.464 219.916 112.488 220 ;
    END
  END w[307]
  PIN w[308]
    DIRECTION INPUT ;
    USE SIGNAL ;
    PORT
      LAYER M5 ;
        RECT  112.512 219.916 112.536 220 ;
    END
  END w[308]
  PIN w[309]
    DIRECTION INPUT ;
    USE SIGNAL ;
    PORT
      LAYER M5 ;
        RECT  112.56 219.916 112.584 220 ;
    END
  END w[309]
  PIN w[30]
    DIRECTION INPUT ;
    USE SIGNAL ;
    PORT
      LAYER M5 ;
        RECT  99.168 219.916 99.192 220 ;
    END
  END w[30]
  PIN w[310]
    DIRECTION INPUT ;
    USE SIGNAL ;
    PORT
      LAYER M5 ;
        RECT  112.608 219.916 112.632 220 ;
    END
  END w[310]
  PIN w[311]
    DIRECTION INPUT ;
    USE SIGNAL ;
    PORT
      LAYER M5 ;
        RECT  112.656 219.916 112.68 220 ;
    END
  END w[311]
  PIN w[312]
    DIRECTION INPUT ;
    USE SIGNAL ;
    PORT
      LAYER M5 ;
        RECT  112.704 219.916 112.728 220 ;
    END
  END w[312]
  PIN w[313]
    DIRECTION INPUT ;
    USE SIGNAL ;
    PORT
      LAYER M5 ;
        RECT  112.752 219.916 112.776 220 ;
    END
  END w[313]
  PIN w[314]
    DIRECTION INPUT ;
    USE SIGNAL ;
    PORT
      LAYER M5 ;
        RECT  112.8 219.916 112.824 220 ;
    END
  END w[314]
  PIN w[315]
    DIRECTION INPUT ;
    USE SIGNAL ;
    PORT
      LAYER M5 ;
        RECT  112.848 219.916 112.872 220 ;
    END
  END w[315]
  PIN w[316]
    DIRECTION INPUT ;
    USE SIGNAL ;
    PORT
      LAYER M5 ;
        RECT  112.896 219.916 112.92 220 ;
    END
  END w[316]
  PIN w[317]
    DIRECTION INPUT ;
    USE SIGNAL ;
    PORT
      LAYER M5 ;
        RECT  112.944 219.916 112.968 220 ;
    END
  END w[317]
  PIN w[318]
    DIRECTION INPUT ;
    USE SIGNAL ;
    PORT
      LAYER M5 ;
        RECT  112.992 219.916 113.016 220 ;
    END
  END w[318]
  PIN w[319]
    DIRECTION INPUT ;
    USE SIGNAL ;
    PORT
      LAYER M5 ;
        RECT  113.04 219.916 113.064 220 ;
    END
  END w[319]
  PIN w[31]
    DIRECTION INPUT ;
    USE SIGNAL ;
    PORT
      LAYER M5 ;
        RECT  99.216 219.916 99.24 220 ;
    END
  END w[31]
  PIN w[320]
    DIRECTION INPUT ;
    USE SIGNAL ;
    PORT
      LAYER M5 ;
        RECT  113.088 219.916 113.112 220 ;
    END
  END w[320]
  PIN w[321]
    DIRECTION INPUT ;
    USE SIGNAL ;
    PORT
      LAYER M5 ;
        RECT  113.136 219.916 113.16 220 ;
    END
  END w[321]
  PIN w[322]
    DIRECTION INPUT ;
    USE SIGNAL ;
    PORT
      LAYER M5 ;
        RECT  113.184 219.916 113.208 220 ;
    END
  END w[322]
  PIN w[323]
    DIRECTION INPUT ;
    USE SIGNAL ;
    PORT
      LAYER M5 ;
        RECT  113.232 219.916 113.256 220 ;
    END
  END w[323]
  PIN w[324]
    DIRECTION INPUT ;
    USE SIGNAL ;
    PORT
      LAYER M5 ;
        RECT  113.28 219.916 113.304 220 ;
    END
  END w[324]
  PIN w[325]
    DIRECTION INPUT ;
    USE SIGNAL ;
    PORT
      LAYER M5 ;
        RECT  113.328 219.916 113.352 220 ;
    END
  END w[325]
  PIN w[326]
    DIRECTION INPUT ;
    USE SIGNAL ;
    PORT
      LAYER M5 ;
        RECT  113.376 219.916 113.4 220 ;
    END
  END w[326]
  PIN w[327]
    DIRECTION INPUT ;
    USE SIGNAL ;
    PORT
      LAYER M5 ;
        RECT  113.424 219.916 113.448 220 ;
    END
  END w[327]
  PIN w[328]
    DIRECTION INPUT ;
    USE SIGNAL ;
    PORT
      LAYER M5 ;
        RECT  113.472 219.916 113.496 220 ;
    END
  END w[328]
  PIN w[329]
    DIRECTION INPUT ;
    USE SIGNAL ;
    PORT
      LAYER M5 ;
        RECT  113.52 219.916 113.544 220 ;
    END
  END w[329]
  PIN w[32]
    DIRECTION INPUT ;
    USE SIGNAL ;
    PORT
      LAYER M5 ;
        RECT  99.264 219.916 99.288 220 ;
    END
  END w[32]
  PIN w[330]
    DIRECTION INPUT ;
    USE SIGNAL ;
    PORT
      LAYER M5 ;
        RECT  113.568 219.916 113.592 220 ;
    END
  END w[330]
  PIN w[331]
    DIRECTION INPUT ;
    USE SIGNAL ;
    PORT
      LAYER M5 ;
        RECT  113.616 219.916 113.64 220 ;
    END
  END w[331]
  PIN w[332]
    DIRECTION INPUT ;
    USE SIGNAL ;
    PORT
      LAYER M5 ;
        RECT  113.664 219.916 113.688 220 ;
    END
  END w[332]
  PIN w[333]
    DIRECTION INPUT ;
    USE SIGNAL ;
    PORT
      LAYER M5 ;
        RECT  113.712 219.916 113.736 220 ;
    END
  END w[333]
  PIN w[334]
    DIRECTION INPUT ;
    USE SIGNAL ;
    PORT
      LAYER M5 ;
        RECT  113.76 219.916 113.784 220 ;
    END
  END w[334]
  PIN w[335]
    DIRECTION INPUT ;
    USE SIGNAL ;
    PORT
      LAYER M5 ;
        RECT  113.808 219.916 113.832 220 ;
    END
  END w[335]
  PIN w[336]
    DIRECTION INPUT ;
    USE SIGNAL ;
    PORT
      LAYER M5 ;
        RECT  113.856 219.916 113.88 220 ;
    END
  END w[336]
  PIN w[337]
    DIRECTION INPUT ;
    USE SIGNAL ;
    PORT
      LAYER M5 ;
        RECT  113.904 219.916 113.928 220 ;
    END
  END w[337]
  PIN w[338]
    DIRECTION INPUT ;
    USE SIGNAL ;
    PORT
      LAYER M5 ;
        RECT  113.952 219.916 113.976 220 ;
    END
  END w[338]
  PIN w[339]
    DIRECTION INPUT ;
    USE SIGNAL ;
    PORT
      LAYER M5 ;
        RECT  114 219.916 114.024 220 ;
    END
  END w[339]
  PIN w[33]
    DIRECTION INPUT ;
    USE SIGNAL ;
    PORT
      LAYER M5 ;
        RECT  99.312 219.916 99.336 220 ;
    END
  END w[33]
  PIN w[340]
    DIRECTION INPUT ;
    USE SIGNAL ;
    PORT
      LAYER M5 ;
        RECT  114.048 219.916 114.072 220 ;
    END
  END w[340]
  PIN w[341]
    DIRECTION INPUT ;
    USE SIGNAL ;
    PORT
      LAYER M5 ;
        RECT  114.096 219.916 114.12 220 ;
    END
  END w[341]
  PIN w[342]
    DIRECTION INPUT ;
    USE SIGNAL ;
    PORT
      LAYER M5 ;
        RECT  114.144 219.916 114.168 220 ;
    END
  END w[342]
  PIN w[343]
    DIRECTION INPUT ;
    USE SIGNAL ;
    PORT
      LAYER M5 ;
        RECT  114.192 219.916 114.216 220 ;
    END
  END w[343]
  PIN w[344]
    DIRECTION INPUT ;
    USE SIGNAL ;
    PORT
      LAYER M5 ;
        RECT  114.24 219.916 114.264 220 ;
    END
  END w[344]
  PIN w[345]
    DIRECTION INPUT ;
    USE SIGNAL ;
    PORT
      LAYER M5 ;
        RECT  114.288 219.916 114.312 220 ;
    END
  END w[345]
  PIN w[346]
    DIRECTION INPUT ;
    USE SIGNAL ;
    PORT
      LAYER M5 ;
        RECT  114.336 219.916 114.36 220 ;
    END
  END w[346]
  PIN w[347]
    DIRECTION INPUT ;
    USE SIGNAL ;
    PORT
      LAYER M5 ;
        RECT  114.384 219.916 114.408 220 ;
    END
  END w[347]
  PIN w[348]
    DIRECTION INPUT ;
    USE SIGNAL ;
    PORT
      LAYER M5 ;
        RECT  114.432 219.916 114.456 220 ;
    END
  END w[348]
  PIN w[349]
    DIRECTION INPUT ;
    USE SIGNAL ;
    PORT
      LAYER M5 ;
        RECT  114.48 219.916 114.504 220 ;
    END
  END w[349]
  PIN w[34]
    DIRECTION INPUT ;
    USE SIGNAL ;
    PORT
      LAYER M5 ;
        RECT  99.36 219.916 99.384 220 ;
    END
  END w[34]
  PIN w[350]
    DIRECTION INPUT ;
    USE SIGNAL ;
    PORT
      LAYER M5 ;
        RECT  114.528 219.916 114.552 220 ;
    END
  END w[350]
  PIN w[351]
    DIRECTION INPUT ;
    USE SIGNAL ;
    PORT
      LAYER M5 ;
        RECT  114.576 219.916 114.6 220 ;
    END
  END w[351]
  PIN w[352]
    DIRECTION INPUT ;
    USE SIGNAL ;
    PORT
      LAYER M5 ;
        RECT  114.624 219.916 114.648 220 ;
    END
  END w[352]
  PIN w[353]
    DIRECTION INPUT ;
    USE SIGNAL ;
    PORT
      LAYER M5 ;
        RECT  114.672 219.916 114.696 220 ;
    END
  END w[353]
  PIN w[354]
    DIRECTION INPUT ;
    USE SIGNAL ;
    PORT
      LAYER M5 ;
        RECT  114.72 219.916 114.744 220 ;
    END
  END w[354]
  PIN w[355]
    DIRECTION INPUT ;
    USE SIGNAL ;
    PORT
      LAYER M5 ;
        RECT  114.768 219.916 114.792 220 ;
    END
  END w[355]
  PIN w[356]
    DIRECTION INPUT ;
    USE SIGNAL ;
    PORT
      LAYER M5 ;
        RECT  114.816 219.916 114.84 220 ;
    END
  END w[356]
  PIN w[357]
    DIRECTION INPUT ;
    USE SIGNAL ;
    PORT
      LAYER M5 ;
        RECT  114.864 219.916 114.888 220 ;
    END
  END w[357]
  PIN w[358]
    DIRECTION INPUT ;
    USE SIGNAL ;
    PORT
      LAYER M5 ;
        RECT  114.912 219.916 114.936 220 ;
    END
  END w[358]
  PIN w[359]
    DIRECTION INPUT ;
    USE SIGNAL ;
    PORT
      LAYER M5 ;
        RECT  114.96 219.916 114.984 220 ;
    END
  END w[359]
  PIN w[35]
    DIRECTION INPUT ;
    USE SIGNAL ;
    PORT
      LAYER M5 ;
        RECT  99.408 219.916 99.432 220 ;
    END
  END w[35]
  PIN w[360]
    DIRECTION INPUT ;
    USE SIGNAL ;
    PORT
      LAYER M5 ;
        RECT  115.008 219.916 115.032 220 ;
    END
  END w[360]
  PIN w[361]
    DIRECTION INPUT ;
    USE SIGNAL ;
    PORT
      LAYER M5 ;
        RECT  115.056 219.916 115.08 220 ;
    END
  END w[361]
  PIN w[362]
    DIRECTION INPUT ;
    USE SIGNAL ;
    PORT
      LAYER M5 ;
        RECT  115.104 219.916 115.128 220 ;
    END
  END w[362]
  PIN w[363]
    DIRECTION INPUT ;
    USE SIGNAL ;
    PORT
      LAYER M5 ;
        RECT  115.152 219.916 115.176 220 ;
    END
  END w[363]
  PIN w[364]
    DIRECTION INPUT ;
    USE SIGNAL ;
    PORT
      LAYER M5 ;
        RECT  115.2 219.916 115.224 220 ;
    END
  END w[364]
  PIN w[365]
    DIRECTION INPUT ;
    USE SIGNAL ;
    PORT
      LAYER M5 ;
        RECT  115.248 219.916 115.272 220 ;
    END
  END w[365]
  PIN w[366]
    DIRECTION INPUT ;
    USE SIGNAL ;
    PORT
      LAYER M5 ;
        RECT  115.296 219.916 115.32 220 ;
    END
  END w[366]
  PIN w[367]
    DIRECTION INPUT ;
    USE SIGNAL ;
    PORT
      LAYER M5 ;
        RECT  115.344 219.916 115.368 220 ;
    END
  END w[367]
  PIN w[368]
    DIRECTION INPUT ;
    USE SIGNAL ;
    PORT
      LAYER M5 ;
        RECT  115.392 219.916 115.416 220 ;
    END
  END w[368]
  PIN w[369]
    DIRECTION INPUT ;
    USE SIGNAL ;
    PORT
      LAYER M5 ;
        RECT  115.44 219.916 115.464 220 ;
    END
  END w[369]
  PIN w[36]
    DIRECTION INPUT ;
    USE SIGNAL ;
    PORT
      LAYER M5 ;
        RECT  99.456 219.916 99.48 220 ;
    END
  END w[36]
  PIN w[370]
    DIRECTION INPUT ;
    USE SIGNAL ;
    PORT
      LAYER M5 ;
        RECT  115.488 219.916 115.512 220 ;
    END
  END w[370]
  PIN w[371]
    DIRECTION INPUT ;
    USE SIGNAL ;
    PORT
      LAYER M5 ;
        RECT  115.536 219.916 115.56 220 ;
    END
  END w[371]
  PIN w[372]
    DIRECTION INPUT ;
    USE SIGNAL ;
    PORT
      LAYER M5 ;
        RECT  115.584 219.916 115.608 220 ;
    END
  END w[372]
  PIN w[373]
    DIRECTION INPUT ;
    USE SIGNAL ;
    PORT
      LAYER M5 ;
        RECT  115.632 219.916 115.656 220 ;
    END
  END w[373]
  PIN w[374]
    DIRECTION INPUT ;
    USE SIGNAL ;
    PORT
      LAYER M5 ;
        RECT  115.68 219.916 115.704 220 ;
    END
  END w[374]
  PIN w[375]
    DIRECTION INPUT ;
    USE SIGNAL ;
    PORT
      LAYER M5 ;
        RECT  115.728 219.916 115.752 220 ;
    END
  END w[375]
  PIN w[376]
    DIRECTION INPUT ;
    USE SIGNAL ;
    PORT
      LAYER M5 ;
        RECT  115.776 219.916 115.8 220 ;
    END
  END w[376]
  PIN w[377]
    DIRECTION INPUT ;
    USE SIGNAL ;
    PORT
      LAYER M5 ;
        RECT  115.824 219.916 115.848 220 ;
    END
  END w[377]
  PIN w[378]
    DIRECTION INPUT ;
    USE SIGNAL ;
    PORT
      LAYER M5 ;
        RECT  115.872 219.916 115.896 220 ;
    END
  END w[378]
  PIN w[379]
    DIRECTION INPUT ;
    USE SIGNAL ;
    PORT
      LAYER M5 ;
        RECT  115.92 219.916 115.944 220 ;
    END
  END w[379]
  PIN w[37]
    DIRECTION INPUT ;
    USE SIGNAL ;
    PORT
      LAYER M5 ;
        RECT  99.504 219.916 99.528 220 ;
    END
  END w[37]
  PIN w[380]
    DIRECTION INPUT ;
    USE SIGNAL ;
    PORT
      LAYER M5 ;
        RECT  115.968 219.916 115.992 220 ;
    END
  END w[380]
  PIN w[381]
    DIRECTION INPUT ;
    USE SIGNAL ;
    PORT
      LAYER M5 ;
        RECT  116.016 219.916 116.04 220 ;
    END
  END w[381]
  PIN w[382]
    DIRECTION INPUT ;
    USE SIGNAL ;
    PORT
      LAYER M5 ;
        RECT  116.064 219.916 116.088 220 ;
    END
  END w[382]
  PIN w[383]
    DIRECTION INPUT ;
    USE SIGNAL ;
    PORT
      LAYER M5 ;
        RECT  116.112 219.916 116.136 220 ;
    END
  END w[383]
  PIN w[384]
    DIRECTION INPUT ;
    USE SIGNAL ;
    PORT
      LAYER M5 ;
        RECT  116.16 219.916 116.184 220 ;
    END
  END w[384]
  PIN w[385]
    DIRECTION INPUT ;
    USE SIGNAL ;
    PORT
      LAYER M5 ;
        RECT  116.208 219.916 116.232 220 ;
    END
  END w[385]
  PIN w[386]
    DIRECTION INPUT ;
    USE SIGNAL ;
    PORT
      LAYER M5 ;
        RECT  116.256 219.916 116.28 220 ;
    END
  END w[386]
  PIN w[387]
    DIRECTION INPUT ;
    USE SIGNAL ;
    PORT
      LAYER M5 ;
        RECT  116.304 219.916 116.328 220 ;
    END
  END w[387]
  PIN w[388]
    DIRECTION INPUT ;
    USE SIGNAL ;
    PORT
      LAYER M5 ;
        RECT  116.352 219.916 116.376 220 ;
    END
  END w[388]
  PIN w[389]
    DIRECTION INPUT ;
    USE SIGNAL ;
    PORT
      LAYER M5 ;
        RECT  116.4 219.916 116.424 220 ;
    END
  END w[389]
  PIN w[38]
    DIRECTION INPUT ;
    USE SIGNAL ;
    PORT
      LAYER M5 ;
        RECT  99.552 219.916 99.576 220 ;
    END
  END w[38]
  PIN w[390]
    DIRECTION INPUT ;
    USE SIGNAL ;
    PORT
      LAYER M5 ;
        RECT  116.448 219.916 116.472 220 ;
    END
  END w[390]
  PIN w[391]
    DIRECTION INPUT ;
    USE SIGNAL ;
    PORT
      LAYER M5 ;
        RECT  116.496 219.916 116.52 220 ;
    END
  END w[391]
  PIN w[392]
    DIRECTION INPUT ;
    USE SIGNAL ;
    PORT
      LAYER M5 ;
        RECT  116.544 219.916 116.568 220 ;
    END
  END w[392]
  PIN w[393]
    DIRECTION INPUT ;
    USE SIGNAL ;
    PORT
      LAYER M5 ;
        RECT  116.592 219.916 116.616 220 ;
    END
  END w[393]
  PIN w[394]
    DIRECTION INPUT ;
    USE SIGNAL ;
    PORT
      LAYER M5 ;
        RECT  116.64 219.916 116.664 220 ;
    END
  END w[394]
  PIN w[395]
    DIRECTION INPUT ;
    USE SIGNAL ;
    PORT
      LAYER M5 ;
        RECT  116.688 219.916 116.712 220 ;
    END
  END w[395]
  PIN w[396]
    DIRECTION INPUT ;
    USE SIGNAL ;
    PORT
      LAYER M5 ;
        RECT  116.736 219.916 116.76 220 ;
    END
  END w[396]
  PIN w[397]
    DIRECTION INPUT ;
    USE SIGNAL ;
    PORT
      LAYER M5 ;
        RECT  116.784 219.916 116.808 220 ;
    END
  END w[397]
  PIN w[398]
    DIRECTION INPUT ;
    USE SIGNAL ;
    PORT
      LAYER M5 ;
        RECT  116.832 219.916 116.856 220 ;
    END
  END w[398]
  PIN w[399]
    DIRECTION INPUT ;
    USE SIGNAL ;
    PORT
      LAYER M5 ;
        RECT  116.88 219.916 116.904 220 ;
    END
  END w[399]
  PIN w[39]
    DIRECTION INPUT ;
    USE SIGNAL ;
    PORT
      LAYER M5 ;
        RECT  99.6 219.916 99.624 220 ;
    END
  END w[39]
  PIN w[3]
    DIRECTION INPUT ;
    USE SIGNAL ;
    PORT
      LAYER M5 ;
        RECT  97.872 219.916 97.896 220 ;
    END
  END w[3]
  PIN w[400]
    DIRECTION INPUT ;
    USE SIGNAL ;
    PORT
      LAYER M5 ;
        RECT  116.928 219.916 116.952 220 ;
    END
  END w[400]
  PIN w[401]
    DIRECTION INPUT ;
    USE SIGNAL ;
    PORT
      LAYER M5 ;
        RECT  116.976 219.916 117 220 ;
    END
  END w[401]
  PIN w[402]
    DIRECTION INPUT ;
    USE SIGNAL ;
    PORT
      LAYER M5 ;
        RECT  117.024 219.916 117.048 220 ;
    END
  END w[402]
  PIN w[403]
    DIRECTION INPUT ;
    USE SIGNAL ;
    PORT
      LAYER M5 ;
        RECT  117.072 219.916 117.096 220 ;
    END
  END w[403]
  PIN w[404]
    DIRECTION INPUT ;
    USE SIGNAL ;
    PORT
      LAYER M5 ;
        RECT  117.12 219.916 117.144 220 ;
    END
  END w[404]
  PIN w[405]
    DIRECTION INPUT ;
    USE SIGNAL ;
    PORT
      LAYER M5 ;
        RECT  117.168 219.916 117.192 220 ;
    END
  END w[405]
  PIN w[406]
    DIRECTION INPUT ;
    USE SIGNAL ;
    PORT
      LAYER M5 ;
        RECT  117.216 219.916 117.24 220 ;
    END
  END w[406]
  PIN w[407]
    DIRECTION INPUT ;
    USE SIGNAL ;
    PORT
      LAYER M5 ;
        RECT  117.264 219.916 117.288 220 ;
    END
  END w[407]
  PIN w[408]
    DIRECTION INPUT ;
    USE SIGNAL ;
    PORT
      LAYER M5 ;
        RECT  117.312 219.916 117.336 220 ;
    END
  END w[408]
  PIN w[409]
    DIRECTION INPUT ;
    USE SIGNAL ;
    PORT
      LAYER M5 ;
        RECT  117.36 219.916 117.384 220 ;
    END
  END w[409]
  PIN w[40]
    DIRECTION INPUT ;
    USE SIGNAL ;
    PORT
      LAYER M5 ;
        RECT  99.648 219.916 99.672 220 ;
    END
  END w[40]
  PIN w[410]
    DIRECTION INPUT ;
    USE SIGNAL ;
    PORT
      LAYER M5 ;
        RECT  117.408 219.916 117.432 220 ;
    END
  END w[410]
  PIN w[411]
    DIRECTION INPUT ;
    USE SIGNAL ;
    PORT
      LAYER M5 ;
        RECT  117.456 219.916 117.48 220 ;
    END
  END w[411]
  PIN w[412]
    DIRECTION INPUT ;
    USE SIGNAL ;
    PORT
      LAYER M5 ;
        RECT  117.504 219.916 117.528 220 ;
    END
  END w[412]
  PIN w[413]
    DIRECTION INPUT ;
    USE SIGNAL ;
    PORT
      LAYER M5 ;
        RECT  117.552 219.916 117.576 220 ;
    END
  END w[413]
  PIN w[414]
    DIRECTION INPUT ;
    USE SIGNAL ;
    PORT
      LAYER M5 ;
        RECT  117.6 219.916 117.624 220 ;
    END
  END w[414]
  PIN w[415]
    DIRECTION INPUT ;
    USE SIGNAL ;
    PORT
      LAYER M5 ;
        RECT  117.648 219.916 117.672 220 ;
    END
  END w[415]
  PIN w[416]
    DIRECTION INPUT ;
    USE SIGNAL ;
    PORT
      LAYER M5 ;
        RECT  117.696 219.916 117.72 220 ;
    END
  END w[416]
  PIN w[417]
    DIRECTION INPUT ;
    USE SIGNAL ;
    PORT
      LAYER M5 ;
        RECT  117.744 219.916 117.768 220 ;
    END
  END w[417]
  PIN w[418]
    DIRECTION INPUT ;
    USE SIGNAL ;
    PORT
      LAYER M5 ;
        RECT  117.792 219.916 117.816 220 ;
    END
  END w[418]
  PIN w[419]
    DIRECTION INPUT ;
    USE SIGNAL ;
    PORT
      LAYER M5 ;
        RECT  117.84 219.916 117.864 220 ;
    END
  END w[419]
  PIN w[41]
    DIRECTION INPUT ;
    USE SIGNAL ;
    PORT
      LAYER M5 ;
        RECT  99.696 219.916 99.72 220 ;
    END
  END w[41]
  PIN w[420]
    DIRECTION INPUT ;
    USE SIGNAL ;
    PORT
      LAYER M5 ;
        RECT  117.888 219.916 117.912 220 ;
    END
  END w[420]
  PIN w[421]
    DIRECTION INPUT ;
    USE SIGNAL ;
    PORT
      LAYER M5 ;
        RECT  117.936 219.916 117.96 220 ;
    END
  END w[421]
  PIN w[422]
    DIRECTION INPUT ;
    USE SIGNAL ;
    PORT
      LAYER M5 ;
        RECT  117.984 219.916 118.008 220 ;
    END
  END w[422]
  PIN w[423]
    DIRECTION INPUT ;
    USE SIGNAL ;
    PORT
      LAYER M5 ;
        RECT  118.032 219.916 118.056 220 ;
    END
  END w[423]
  PIN w[424]
    DIRECTION INPUT ;
    USE SIGNAL ;
    PORT
      LAYER M5 ;
        RECT  118.08 219.916 118.104 220 ;
    END
  END w[424]
  PIN w[425]
    DIRECTION INPUT ;
    USE SIGNAL ;
    PORT
      LAYER M5 ;
        RECT  118.128 219.916 118.152 220 ;
    END
  END w[425]
  PIN w[426]
    DIRECTION INPUT ;
    USE SIGNAL ;
    PORT
      LAYER M5 ;
        RECT  118.176 219.916 118.2 220 ;
    END
  END w[426]
  PIN w[427]
    DIRECTION INPUT ;
    USE SIGNAL ;
    PORT
      LAYER M5 ;
        RECT  118.224 219.916 118.248 220 ;
    END
  END w[427]
  PIN w[428]
    DIRECTION INPUT ;
    USE SIGNAL ;
    PORT
      LAYER M5 ;
        RECT  118.272 219.916 118.296 220 ;
    END
  END w[428]
  PIN w[429]
    DIRECTION INPUT ;
    USE SIGNAL ;
    PORT
      LAYER M5 ;
        RECT  118.32 219.916 118.344 220 ;
    END
  END w[429]
  PIN w[42]
    DIRECTION INPUT ;
    USE SIGNAL ;
    PORT
      LAYER M5 ;
        RECT  99.744 219.916 99.768 220 ;
    END
  END w[42]
  PIN w[430]
    DIRECTION INPUT ;
    USE SIGNAL ;
    PORT
      LAYER M5 ;
        RECT  118.368 219.916 118.392 220 ;
    END
  END w[430]
  PIN w[431]
    DIRECTION INPUT ;
    USE SIGNAL ;
    PORT
      LAYER M5 ;
        RECT  118.416 219.916 118.44 220 ;
    END
  END w[431]
  PIN w[432]
    DIRECTION INPUT ;
    USE SIGNAL ;
    PORT
      LAYER M5 ;
        RECT  118.464 219.916 118.488 220 ;
    END
  END w[432]
  PIN w[433]
    DIRECTION INPUT ;
    USE SIGNAL ;
    PORT
      LAYER M5 ;
        RECT  118.512 219.916 118.536 220 ;
    END
  END w[433]
  PIN w[434]
    DIRECTION INPUT ;
    USE SIGNAL ;
    PORT
      LAYER M5 ;
        RECT  118.56 219.916 118.584 220 ;
    END
  END w[434]
  PIN w[435]
    DIRECTION INPUT ;
    USE SIGNAL ;
    PORT
      LAYER M5 ;
        RECT  118.608 219.916 118.632 220 ;
    END
  END w[435]
  PIN w[436]
    DIRECTION INPUT ;
    USE SIGNAL ;
    PORT
      LAYER M5 ;
        RECT  118.656 219.916 118.68 220 ;
    END
  END w[436]
  PIN w[437]
    DIRECTION INPUT ;
    USE SIGNAL ;
    PORT
      LAYER M5 ;
        RECT  118.704 219.916 118.728 220 ;
    END
  END w[437]
  PIN w[438]
    DIRECTION INPUT ;
    USE SIGNAL ;
    PORT
      LAYER M5 ;
        RECT  118.752 219.916 118.776 220 ;
    END
  END w[438]
  PIN w[439]
    DIRECTION INPUT ;
    USE SIGNAL ;
    PORT
      LAYER M5 ;
        RECT  118.8 219.916 118.824 220 ;
    END
  END w[439]
  PIN w[43]
    DIRECTION INPUT ;
    USE SIGNAL ;
    PORT
      LAYER M5 ;
        RECT  99.792 219.916 99.816 220 ;
    END
  END w[43]
  PIN w[440]
    DIRECTION INPUT ;
    USE SIGNAL ;
    PORT
      LAYER M5 ;
        RECT  118.848 219.916 118.872 220 ;
    END
  END w[440]
  PIN w[441]
    DIRECTION INPUT ;
    USE SIGNAL ;
    PORT
      LAYER M5 ;
        RECT  118.896 219.916 118.92 220 ;
    END
  END w[441]
  PIN w[442]
    DIRECTION INPUT ;
    USE SIGNAL ;
    PORT
      LAYER M5 ;
        RECT  118.944 219.916 118.968 220 ;
    END
  END w[442]
  PIN w[443]
    DIRECTION INPUT ;
    USE SIGNAL ;
    PORT
      LAYER M5 ;
        RECT  118.992 219.916 119.016 220 ;
    END
  END w[443]
  PIN w[444]
    DIRECTION INPUT ;
    USE SIGNAL ;
    PORT
      LAYER M5 ;
        RECT  119.04 219.916 119.064 220 ;
    END
  END w[444]
  PIN w[445]
    DIRECTION INPUT ;
    USE SIGNAL ;
    PORT
      LAYER M5 ;
        RECT  119.088 219.916 119.112 220 ;
    END
  END w[445]
  PIN w[446]
    DIRECTION INPUT ;
    USE SIGNAL ;
    PORT
      LAYER M5 ;
        RECT  119.136 219.916 119.16 220 ;
    END
  END w[446]
  PIN w[447]
    DIRECTION INPUT ;
    USE SIGNAL ;
    PORT
      LAYER M5 ;
        RECT  119.184 219.916 119.208 220 ;
    END
  END w[447]
  PIN w[448]
    DIRECTION INPUT ;
    USE SIGNAL ;
    PORT
      LAYER M5 ;
        RECT  119.232 219.916 119.256 220 ;
    END
  END w[448]
  PIN w[449]
    DIRECTION INPUT ;
    USE SIGNAL ;
    PORT
      LAYER M5 ;
        RECT  119.28 219.916 119.304 220 ;
    END
  END w[449]
  PIN w[44]
    DIRECTION INPUT ;
    USE SIGNAL ;
    PORT
      LAYER M5 ;
        RECT  99.84 219.916 99.864 220 ;
    END
  END w[44]
  PIN w[450]
    DIRECTION INPUT ;
    USE SIGNAL ;
    PORT
      LAYER M5 ;
        RECT  119.328 219.916 119.352 220 ;
    END
  END w[450]
  PIN w[451]
    DIRECTION INPUT ;
    USE SIGNAL ;
    PORT
      LAYER M5 ;
        RECT  119.376 219.916 119.4 220 ;
    END
  END w[451]
  PIN w[452]
    DIRECTION INPUT ;
    USE SIGNAL ;
    PORT
      LAYER M5 ;
        RECT  119.424 219.916 119.448 220 ;
    END
  END w[452]
  PIN w[453]
    DIRECTION INPUT ;
    USE SIGNAL ;
    PORT
      LAYER M5 ;
        RECT  119.472 219.916 119.496 220 ;
    END
  END w[453]
  PIN w[454]
    DIRECTION INPUT ;
    USE SIGNAL ;
    PORT
      LAYER M5 ;
        RECT  119.52 219.916 119.544 220 ;
    END
  END w[454]
  PIN w[455]
    DIRECTION INPUT ;
    USE SIGNAL ;
    PORT
      LAYER M5 ;
        RECT  119.568 219.916 119.592 220 ;
    END
  END w[455]
  PIN w[456]
    DIRECTION INPUT ;
    USE SIGNAL ;
    PORT
      LAYER M5 ;
        RECT  119.616 219.916 119.64 220 ;
    END
  END w[456]
  PIN w[457]
    DIRECTION INPUT ;
    USE SIGNAL ;
    PORT
      LAYER M5 ;
        RECT  119.664 219.916 119.688 220 ;
    END
  END w[457]
  PIN w[458]
    DIRECTION INPUT ;
    USE SIGNAL ;
    PORT
      LAYER M5 ;
        RECT  119.712 219.916 119.736 220 ;
    END
  END w[458]
  PIN w[459]
    DIRECTION INPUT ;
    USE SIGNAL ;
    PORT
      LAYER M5 ;
        RECT  119.76 219.916 119.784 220 ;
    END
  END w[459]
  PIN w[45]
    DIRECTION INPUT ;
    USE SIGNAL ;
    PORT
      LAYER M5 ;
        RECT  99.888 219.916 99.912 220 ;
    END
  END w[45]
  PIN w[460]
    DIRECTION INPUT ;
    USE SIGNAL ;
    PORT
      LAYER M5 ;
        RECT  119.808 219.916 119.832 220 ;
    END
  END w[460]
  PIN w[461]
    DIRECTION INPUT ;
    USE SIGNAL ;
    PORT
      LAYER M5 ;
        RECT  119.856 219.916 119.88 220 ;
    END
  END w[461]
  PIN w[462]
    DIRECTION INPUT ;
    USE SIGNAL ;
    PORT
      LAYER M5 ;
        RECT  119.904 219.916 119.928 220 ;
    END
  END w[462]
  PIN w[463]
    DIRECTION INPUT ;
    USE SIGNAL ;
    PORT
      LAYER M5 ;
        RECT  119.952 219.916 119.976 220 ;
    END
  END w[463]
  PIN w[464]
    DIRECTION INPUT ;
    USE SIGNAL ;
    PORT
      LAYER M5 ;
        RECT  120 219.916 120.024 220 ;
    END
  END w[464]
  PIN w[465]
    DIRECTION INPUT ;
    USE SIGNAL ;
    PORT
      LAYER M5 ;
        RECT  120.048 219.916 120.072 220 ;
    END
  END w[465]
  PIN w[466]
    DIRECTION INPUT ;
    USE SIGNAL ;
    PORT
      LAYER M5 ;
        RECT  120.096 219.916 120.12 220 ;
    END
  END w[466]
  PIN w[467]
    DIRECTION INPUT ;
    USE SIGNAL ;
    PORT
      LAYER M5 ;
        RECT  120.144 219.916 120.168 220 ;
    END
  END w[467]
  PIN w[468]
    DIRECTION INPUT ;
    USE SIGNAL ;
    PORT
      LAYER M5 ;
        RECT  120.192 219.916 120.216 220 ;
    END
  END w[468]
  PIN w[469]
    DIRECTION INPUT ;
    USE SIGNAL ;
    PORT
      LAYER M5 ;
        RECT  120.24 219.916 120.264 220 ;
    END
  END w[469]
  PIN w[46]
    DIRECTION INPUT ;
    USE SIGNAL ;
    PORT
      LAYER M5 ;
        RECT  99.936 219.916 99.96 220 ;
    END
  END w[46]
  PIN w[470]
    DIRECTION INPUT ;
    USE SIGNAL ;
    PORT
      LAYER M5 ;
        RECT  120.288 219.916 120.312 220 ;
    END
  END w[470]
  PIN w[471]
    DIRECTION INPUT ;
    USE SIGNAL ;
    PORT
      LAYER M5 ;
        RECT  120.336 219.916 120.36 220 ;
    END
  END w[471]
  PIN w[472]
    DIRECTION INPUT ;
    USE SIGNAL ;
    PORT
      LAYER M5 ;
        RECT  120.384 219.916 120.408 220 ;
    END
  END w[472]
  PIN w[473]
    DIRECTION INPUT ;
    USE SIGNAL ;
    PORT
      LAYER M5 ;
        RECT  120.432 219.916 120.456 220 ;
    END
  END w[473]
  PIN w[474]
    DIRECTION INPUT ;
    USE SIGNAL ;
    PORT
      LAYER M5 ;
        RECT  120.48 219.916 120.504 220 ;
    END
  END w[474]
  PIN w[475]
    DIRECTION INPUT ;
    USE SIGNAL ;
    PORT
      LAYER M5 ;
        RECT  120.528 219.916 120.552 220 ;
    END
  END w[475]
  PIN w[476]
    DIRECTION INPUT ;
    USE SIGNAL ;
    PORT
      LAYER M5 ;
        RECT  120.576 219.916 120.6 220 ;
    END
  END w[476]
  PIN w[477]
    DIRECTION INPUT ;
    USE SIGNAL ;
    PORT
      LAYER M5 ;
        RECT  120.624 219.916 120.648 220 ;
    END
  END w[477]
  PIN w[478]
    DIRECTION INPUT ;
    USE SIGNAL ;
    PORT
      LAYER M5 ;
        RECT  120.672 219.916 120.696 220 ;
    END
  END w[478]
  PIN w[479]
    DIRECTION INPUT ;
    USE SIGNAL ;
    PORT
      LAYER M5 ;
        RECT  120.72 219.916 120.744 220 ;
    END
  END w[479]
  PIN w[47]
    DIRECTION INPUT ;
    USE SIGNAL ;
    PORT
      LAYER M5 ;
        RECT  99.984 219.916 100.008 220 ;
    END
  END w[47]
  PIN w[480]
    DIRECTION INPUT ;
    USE SIGNAL ;
    PORT
      LAYER M5 ;
        RECT  120.768 219.916 120.792 220 ;
    END
  END w[480]
  PIN w[481]
    DIRECTION INPUT ;
    USE SIGNAL ;
    PORT
      LAYER M5 ;
        RECT  120.816 219.916 120.84 220 ;
    END
  END w[481]
  PIN w[482]
    DIRECTION INPUT ;
    USE SIGNAL ;
    PORT
      LAYER M5 ;
        RECT  120.864 219.916 120.888 220 ;
    END
  END w[482]
  PIN w[483]
    DIRECTION INPUT ;
    USE SIGNAL ;
    PORT
      LAYER M5 ;
        RECT  120.912 219.916 120.936 220 ;
    END
  END w[483]
  PIN w[484]
    DIRECTION INPUT ;
    USE SIGNAL ;
    PORT
      LAYER M5 ;
        RECT  120.96 219.916 120.984 220 ;
    END
  END w[484]
  PIN w[485]
    DIRECTION INPUT ;
    USE SIGNAL ;
    PORT
      LAYER M5 ;
        RECT  121.008 219.916 121.032 220 ;
    END
  END w[485]
  PIN w[486]
    DIRECTION INPUT ;
    USE SIGNAL ;
    PORT
      LAYER M5 ;
        RECT  121.056 219.916 121.08 220 ;
    END
  END w[486]
  PIN w[487]
    DIRECTION INPUT ;
    USE SIGNAL ;
    PORT
      LAYER M5 ;
        RECT  121.104 219.916 121.128 220 ;
    END
  END w[487]
  PIN w[488]
    DIRECTION INPUT ;
    USE SIGNAL ;
    PORT
      LAYER M5 ;
        RECT  121.152 219.916 121.176 220 ;
    END
  END w[488]
  PIN w[489]
    DIRECTION INPUT ;
    USE SIGNAL ;
    PORT
      LAYER M5 ;
        RECT  121.2 219.916 121.224 220 ;
    END
  END w[489]
  PIN w[48]
    DIRECTION INPUT ;
    USE SIGNAL ;
    PORT
      LAYER M5 ;
        RECT  100.032 219.916 100.056 220 ;
    END
  END w[48]
  PIN w[490]
    DIRECTION INPUT ;
    USE SIGNAL ;
    PORT
      LAYER M5 ;
        RECT  121.248 219.916 121.272 220 ;
    END
  END w[490]
  PIN w[491]
    DIRECTION INPUT ;
    USE SIGNAL ;
    PORT
      LAYER M5 ;
        RECT  121.296 219.916 121.32 220 ;
    END
  END w[491]
  PIN w[492]
    DIRECTION INPUT ;
    USE SIGNAL ;
    PORT
      LAYER M5 ;
        RECT  121.344 219.916 121.368 220 ;
    END
  END w[492]
  PIN w[493]
    DIRECTION INPUT ;
    USE SIGNAL ;
    PORT
      LAYER M5 ;
        RECT  121.392 219.916 121.416 220 ;
    END
  END w[493]
  PIN w[494]
    DIRECTION INPUT ;
    USE SIGNAL ;
    PORT
      LAYER M5 ;
        RECT  121.44 219.916 121.464 220 ;
    END
  END w[494]
  PIN w[495]
    DIRECTION INPUT ;
    USE SIGNAL ;
    PORT
      LAYER M5 ;
        RECT  121.488 219.916 121.512 220 ;
    END
  END w[495]
  PIN w[496]
    DIRECTION INPUT ;
    USE SIGNAL ;
    PORT
      LAYER M5 ;
        RECT  121.536 219.916 121.56 220 ;
    END
  END w[496]
  PIN w[497]
    DIRECTION INPUT ;
    USE SIGNAL ;
    PORT
      LAYER M5 ;
        RECT  121.584 219.916 121.608 220 ;
    END
  END w[497]
  PIN w[498]
    DIRECTION INPUT ;
    USE SIGNAL ;
    PORT
      LAYER M5 ;
        RECT  121.632 219.916 121.656 220 ;
    END
  END w[498]
  PIN w[499]
    DIRECTION INPUT ;
    USE SIGNAL ;
    PORT
      LAYER M5 ;
        RECT  121.68 219.916 121.704 220 ;
    END
  END w[499]
  PIN w[49]
    DIRECTION INPUT ;
    USE SIGNAL ;
    PORT
      LAYER M5 ;
        RECT  100.08 219.916 100.104 220 ;
    END
  END w[49]
  PIN w[4]
    DIRECTION INPUT ;
    USE SIGNAL ;
    PORT
      LAYER M5 ;
        RECT  97.92 219.916 97.944 220 ;
    END
  END w[4]
  PIN w[500]
    DIRECTION INPUT ;
    USE SIGNAL ;
    PORT
      LAYER M5 ;
        RECT  121.728 219.916 121.752 220 ;
    END
  END w[500]
  PIN w[501]
    DIRECTION INPUT ;
    USE SIGNAL ;
    PORT
      LAYER M5 ;
        RECT  121.776 219.916 121.8 220 ;
    END
  END w[501]
  PIN w[502]
    DIRECTION INPUT ;
    USE SIGNAL ;
    PORT
      LAYER M5 ;
        RECT  121.824 219.916 121.848 220 ;
    END
  END w[502]
  PIN w[503]
    DIRECTION INPUT ;
    USE SIGNAL ;
    PORT
      LAYER M5 ;
        RECT  121.872 219.916 121.896 220 ;
    END
  END w[503]
  PIN w[504]
    DIRECTION INPUT ;
    USE SIGNAL ;
    PORT
      LAYER M5 ;
        RECT  121.92 219.916 121.944 220 ;
    END
  END w[504]
  PIN w[505]
    DIRECTION INPUT ;
    USE SIGNAL ;
    PORT
      LAYER M5 ;
        RECT  121.968 219.916 121.992 220 ;
    END
  END w[505]
  PIN w[506]
    DIRECTION INPUT ;
    USE SIGNAL ;
    PORT
      LAYER M5 ;
        RECT  122.016 219.916 122.04 220 ;
    END
  END w[506]
  PIN w[507]
    DIRECTION INPUT ;
    USE SIGNAL ;
    PORT
      LAYER M5 ;
        RECT  122.064 219.916 122.088 220 ;
    END
  END w[507]
  PIN w[508]
    DIRECTION INPUT ;
    USE SIGNAL ;
    PORT
      LAYER M5 ;
        RECT  122.112 219.916 122.136 220 ;
    END
  END w[508]
  PIN w[509]
    DIRECTION INPUT ;
    USE SIGNAL ;
    PORT
      LAYER M5 ;
        RECT  122.16 219.916 122.184 220 ;
    END
  END w[509]
  PIN w[50]
    DIRECTION INPUT ;
    USE SIGNAL ;
    PORT
      LAYER M5 ;
        RECT  100.128 219.916 100.152 220 ;
    END
  END w[50]
  PIN w[510]
    DIRECTION INPUT ;
    USE SIGNAL ;
    PORT
      LAYER M5 ;
        RECT  122.208 219.916 122.232 220 ;
    END
  END w[510]
  PIN w[511]
    DIRECTION INPUT ;
    USE SIGNAL ;
    PORT
      LAYER M5 ;
        RECT  122.256 219.916 122.28 220 ;
    END
  END w[511]
  PIN w[51]
    DIRECTION INPUT ;
    USE SIGNAL ;
    PORT
      LAYER M5 ;
        RECT  100.176 219.916 100.2 220 ;
    END
  END w[51]
  PIN w[52]
    DIRECTION INPUT ;
    USE SIGNAL ;
    PORT
      LAYER M5 ;
        RECT  100.224 219.916 100.248 220 ;
    END
  END w[52]
  PIN w[53]
    DIRECTION INPUT ;
    USE SIGNAL ;
    PORT
      LAYER M5 ;
        RECT  100.272 219.916 100.296 220 ;
    END
  END w[53]
  PIN w[54]
    DIRECTION INPUT ;
    USE SIGNAL ;
    PORT
      LAYER M5 ;
        RECT  100.32 219.916 100.344 220 ;
    END
  END w[54]
  PIN w[55]
    DIRECTION INPUT ;
    USE SIGNAL ;
    PORT
      LAYER M5 ;
        RECT  100.368 219.916 100.392 220 ;
    END
  END w[55]
  PIN w[56]
    DIRECTION INPUT ;
    USE SIGNAL ;
    PORT
      LAYER M5 ;
        RECT  100.416 219.916 100.44 220 ;
    END
  END w[56]
  PIN w[57]
    DIRECTION INPUT ;
    USE SIGNAL ;
    PORT
      LAYER M5 ;
        RECT  100.464 219.916 100.488 220 ;
    END
  END w[57]
  PIN w[58]
    DIRECTION INPUT ;
    USE SIGNAL ;
    PORT
      LAYER M5 ;
        RECT  100.512 219.916 100.536 220 ;
    END
  END w[58]
  PIN w[59]
    DIRECTION INPUT ;
    USE SIGNAL ;
    PORT
      LAYER M5 ;
        RECT  100.56 219.916 100.584 220 ;
    END
  END w[59]
  PIN w[5]
    DIRECTION INPUT ;
    USE SIGNAL ;
    PORT
      LAYER M5 ;
        RECT  97.968 219.916 97.992 220 ;
    END
  END w[5]
  PIN w[60]
    DIRECTION INPUT ;
    USE SIGNAL ;
    PORT
      LAYER M5 ;
        RECT  100.608 219.916 100.632 220 ;
    END
  END w[60]
  PIN w[61]
    DIRECTION INPUT ;
    USE SIGNAL ;
    PORT
      LAYER M5 ;
        RECT  100.656 219.916 100.68 220 ;
    END
  END w[61]
  PIN w[62]
    DIRECTION INPUT ;
    USE SIGNAL ;
    PORT
      LAYER M5 ;
        RECT  100.704 219.916 100.728 220 ;
    END
  END w[62]
  PIN w[63]
    DIRECTION INPUT ;
    USE SIGNAL ;
    PORT
      LAYER M5 ;
        RECT  100.752 219.916 100.776 220 ;
    END
  END w[63]
  PIN w[64]
    DIRECTION INPUT ;
    USE SIGNAL ;
    PORT
      LAYER M5 ;
        RECT  100.8 219.916 100.824 220 ;
    END
  END w[64]
  PIN w[65]
    DIRECTION INPUT ;
    USE SIGNAL ;
    PORT
      LAYER M5 ;
        RECT  100.848 219.916 100.872 220 ;
    END
  END w[65]
  PIN w[66]
    DIRECTION INPUT ;
    USE SIGNAL ;
    PORT
      LAYER M5 ;
        RECT  100.896 219.916 100.92 220 ;
    END
  END w[66]
  PIN w[67]
    DIRECTION INPUT ;
    USE SIGNAL ;
    PORT
      LAYER M5 ;
        RECT  100.944 219.916 100.968 220 ;
    END
  END w[67]
  PIN w[68]
    DIRECTION INPUT ;
    USE SIGNAL ;
    PORT
      LAYER M5 ;
        RECT  100.992 219.916 101.016 220 ;
    END
  END w[68]
  PIN w[69]
    DIRECTION INPUT ;
    USE SIGNAL ;
    PORT
      LAYER M5 ;
        RECT  101.04 219.916 101.064 220 ;
    END
  END w[69]
  PIN w[6]
    DIRECTION INPUT ;
    USE SIGNAL ;
    PORT
      LAYER M5 ;
        RECT  98.016 219.916 98.04 220 ;
    END
  END w[6]
  PIN w[70]
    DIRECTION INPUT ;
    USE SIGNAL ;
    PORT
      LAYER M5 ;
        RECT  101.088 219.916 101.112 220 ;
    END
  END w[70]
  PIN w[71]
    DIRECTION INPUT ;
    USE SIGNAL ;
    PORT
      LAYER M5 ;
        RECT  101.136 219.916 101.16 220 ;
    END
  END w[71]
  PIN w[72]
    DIRECTION INPUT ;
    USE SIGNAL ;
    PORT
      LAYER M5 ;
        RECT  101.184 219.916 101.208 220 ;
    END
  END w[72]
  PIN w[73]
    DIRECTION INPUT ;
    USE SIGNAL ;
    PORT
      LAYER M5 ;
        RECT  101.232 219.916 101.256 220 ;
    END
  END w[73]
  PIN w[74]
    DIRECTION INPUT ;
    USE SIGNAL ;
    PORT
      LAYER M5 ;
        RECT  101.28 219.916 101.304 220 ;
    END
  END w[74]
  PIN w[75]
    DIRECTION INPUT ;
    USE SIGNAL ;
    PORT
      LAYER M5 ;
        RECT  101.328 219.916 101.352 220 ;
    END
  END w[75]
  PIN w[76]
    DIRECTION INPUT ;
    USE SIGNAL ;
    PORT
      LAYER M5 ;
        RECT  101.376 219.916 101.4 220 ;
    END
  END w[76]
  PIN w[77]
    DIRECTION INPUT ;
    USE SIGNAL ;
    PORT
      LAYER M5 ;
        RECT  101.424 219.916 101.448 220 ;
    END
  END w[77]
  PIN w[78]
    DIRECTION INPUT ;
    USE SIGNAL ;
    PORT
      LAYER M5 ;
        RECT  101.472 219.916 101.496 220 ;
    END
  END w[78]
  PIN w[79]
    DIRECTION INPUT ;
    USE SIGNAL ;
    PORT
      LAYER M5 ;
        RECT  101.52 219.916 101.544 220 ;
    END
  END w[79]
  PIN w[7]
    DIRECTION INPUT ;
    USE SIGNAL ;
    PORT
      LAYER M5 ;
        RECT  98.064 219.916 98.088 220 ;
    END
  END w[7]
  PIN w[80]
    DIRECTION INPUT ;
    USE SIGNAL ;
    PORT
      LAYER M5 ;
        RECT  101.568 219.916 101.592 220 ;
    END
  END w[80]
  PIN w[81]
    DIRECTION INPUT ;
    USE SIGNAL ;
    PORT
      LAYER M5 ;
        RECT  101.616 219.916 101.64 220 ;
    END
  END w[81]
  PIN w[82]
    DIRECTION INPUT ;
    USE SIGNAL ;
    PORT
      LAYER M5 ;
        RECT  101.664 219.916 101.688 220 ;
    END
  END w[82]
  PIN w[83]
    DIRECTION INPUT ;
    USE SIGNAL ;
    PORT
      LAYER M5 ;
        RECT  101.712 219.916 101.736 220 ;
    END
  END w[83]
  PIN w[84]
    DIRECTION INPUT ;
    USE SIGNAL ;
    PORT
      LAYER M5 ;
        RECT  101.76 219.916 101.784 220 ;
    END
  END w[84]
  PIN w[85]
    DIRECTION INPUT ;
    USE SIGNAL ;
    PORT
      LAYER M5 ;
        RECT  101.808 219.916 101.832 220 ;
    END
  END w[85]
  PIN w[86]
    DIRECTION INPUT ;
    USE SIGNAL ;
    PORT
      LAYER M5 ;
        RECT  101.856 219.916 101.88 220 ;
    END
  END w[86]
  PIN w[87]
    DIRECTION INPUT ;
    USE SIGNAL ;
    PORT
      LAYER M5 ;
        RECT  101.904 219.916 101.928 220 ;
    END
  END w[87]
  PIN w[88]
    DIRECTION INPUT ;
    USE SIGNAL ;
    PORT
      LAYER M5 ;
        RECT  101.952 219.916 101.976 220 ;
    END
  END w[88]
  PIN w[89]
    DIRECTION INPUT ;
    USE SIGNAL ;
    PORT
      LAYER M5 ;
        RECT  102 219.916 102.024 220 ;
    END
  END w[89]
  PIN w[8]
    DIRECTION INPUT ;
    USE SIGNAL ;
    PORT
      LAYER M5 ;
        RECT  98.112 219.916 98.136 220 ;
    END
  END w[8]
  PIN w[90]
    DIRECTION INPUT ;
    USE SIGNAL ;
    PORT
      LAYER M5 ;
        RECT  102.048 219.916 102.072 220 ;
    END
  END w[90]
  PIN w[91]
    DIRECTION INPUT ;
    USE SIGNAL ;
    PORT
      LAYER M5 ;
        RECT  102.096 219.916 102.12 220 ;
    END
  END w[91]
  PIN w[92]
    DIRECTION INPUT ;
    USE SIGNAL ;
    PORT
      LAYER M5 ;
        RECT  102.144 219.916 102.168 220 ;
    END
  END w[92]
  PIN w[93]
    DIRECTION INPUT ;
    USE SIGNAL ;
    PORT
      LAYER M5 ;
        RECT  102.192 219.916 102.216 220 ;
    END
  END w[93]
  PIN w[94]
    DIRECTION INPUT ;
    USE SIGNAL ;
    PORT
      LAYER M5 ;
        RECT  102.24 219.916 102.264 220 ;
    END
  END w[94]
  PIN w[95]
    DIRECTION INPUT ;
    USE SIGNAL ;
    PORT
      LAYER M5 ;
        RECT  102.288 219.916 102.312 220 ;
    END
  END w[95]
  PIN w[96]
    DIRECTION INPUT ;
    USE SIGNAL ;
    PORT
      LAYER M5 ;
        RECT  102.336 219.916 102.36 220 ;
    END
  END w[96]
  PIN w[97]
    DIRECTION INPUT ;
    USE SIGNAL ;
    PORT
      LAYER M5 ;
        RECT  102.384 219.916 102.408 220 ;
    END
  END w[97]
  PIN w[98]
    DIRECTION INPUT ;
    USE SIGNAL ;
    PORT
      LAYER M5 ;
        RECT  102.432 219.916 102.456 220 ;
    END
  END w[98]
  PIN w[99]
    DIRECTION INPUT ;
    USE SIGNAL ;
    PORT
      LAYER M5 ;
        RECT  102.48 219.916 102.504 220 ;
    END
  END w[99]
  PIN w[9]
    DIRECTION INPUT ;
    USE SIGNAL ;
    PORT
      LAYER M5 ;
        RECT  98.16 219.916 98.184 220 ;
    END
  END w[9]
  PIN x[0]
    DIRECTION INPUT ;
    USE SIGNAL ;
    PORT
      LAYER M4 ;
        RECT  0 97.728 0.084 97.752 ;
    END
  END x[0]
  PIN x[100]
    DIRECTION INPUT ;
    USE SIGNAL ;
    PORT
      LAYER M4 ;
        RECT  0 102.528 0.084 102.552 ;
    END
  END x[100]
  PIN x[101]
    DIRECTION INPUT ;
    USE SIGNAL ;
    PORT
      LAYER M4 ;
        RECT  0 102.576 0.084 102.6 ;
    END
  END x[101]
  PIN x[102]
    DIRECTION INPUT ;
    USE SIGNAL ;
    PORT
      LAYER M4 ;
        RECT  0 102.624 0.084 102.648 ;
    END
  END x[102]
  PIN x[103]
    DIRECTION INPUT ;
    USE SIGNAL ;
    PORT
      LAYER M4 ;
        RECT  0 102.672 0.084 102.696 ;
    END
  END x[103]
  PIN x[104]
    DIRECTION INPUT ;
    USE SIGNAL ;
    PORT
      LAYER M4 ;
        RECT  0 102.72 0.084 102.744 ;
    END
  END x[104]
  PIN x[105]
    DIRECTION INPUT ;
    USE SIGNAL ;
    PORT
      LAYER M4 ;
        RECT  0 102.768 0.084 102.792 ;
    END
  END x[105]
  PIN x[106]
    DIRECTION INPUT ;
    USE SIGNAL ;
    PORT
      LAYER M4 ;
        RECT  0 102.816 0.084 102.84 ;
    END
  END x[106]
  PIN x[107]
    DIRECTION INPUT ;
    USE SIGNAL ;
    PORT
      LAYER M4 ;
        RECT  0 102.864 0.084 102.888 ;
    END
  END x[107]
  PIN x[108]
    DIRECTION INPUT ;
    USE SIGNAL ;
    PORT
      LAYER M4 ;
        RECT  0 102.912 0.084 102.936 ;
    END
  END x[108]
  PIN x[109]
    DIRECTION INPUT ;
    USE SIGNAL ;
    PORT
      LAYER M4 ;
        RECT  0 102.96 0.084 102.984 ;
    END
  END x[109]
  PIN x[10]
    DIRECTION INPUT ;
    USE SIGNAL ;
    PORT
      LAYER M4 ;
        RECT  0 98.208 0.084 98.232 ;
    END
  END x[10]
  PIN x[110]
    DIRECTION INPUT ;
    USE SIGNAL ;
    PORT
      LAYER M4 ;
        RECT  0 103.008 0.084 103.032 ;
    END
  END x[110]
  PIN x[111]
    DIRECTION INPUT ;
    USE SIGNAL ;
    PORT
      LAYER M4 ;
        RECT  0 103.056 0.084 103.08 ;
    END
  END x[111]
  PIN x[112]
    DIRECTION INPUT ;
    USE SIGNAL ;
    PORT
      LAYER M4 ;
        RECT  0 103.104 0.084 103.128 ;
    END
  END x[112]
  PIN x[113]
    DIRECTION INPUT ;
    USE SIGNAL ;
    PORT
      LAYER M4 ;
        RECT  0 103.152 0.084 103.176 ;
    END
  END x[113]
  PIN x[114]
    DIRECTION INPUT ;
    USE SIGNAL ;
    PORT
      LAYER M4 ;
        RECT  0 103.2 0.084 103.224 ;
    END
  END x[114]
  PIN x[115]
    DIRECTION INPUT ;
    USE SIGNAL ;
    PORT
      LAYER M4 ;
        RECT  0 103.248 0.084 103.272 ;
    END
  END x[115]
  PIN x[116]
    DIRECTION INPUT ;
    USE SIGNAL ;
    PORT
      LAYER M4 ;
        RECT  0 103.296 0.084 103.32 ;
    END
  END x[116]
  PIN x[117]
    DIRECTION INPUT ;
    USE SIGNAL ;
    PORT
      LAYER M4 ;
        RECT  0 103.344 0.084 103.368 ;
    END
  END x[117]
  PIN x[118]
    DIRECTION INPUT ;
    USE SIGNAL ;
    PORT
      LAYER M4 ;
        RECT  0 103.392 0.084 103.416 ;
    END
  END x[118]
  PIN x[119]
    DIRECTION INPUT ;
    USE SIGNAL ;
    PORT
      LAYER M4 ;
        RECT  0 103.44 0.084 103.464 ;
    END
  END x[119]
  PIN x[11]
    DIRECTION INPUT ;
    USE SIGNAL ;
    PORT
      LAYER M4 ;
        RECT  0 98.256 0.084 98.28 ;
    END
  END x[11]
  PIN x[120]
    DIRECTION INPUT ;
    USE SIGNAL ;
    PORT
      LAYER M4 ;
        RECT  0 103.488 0.084 103.512 ;
    END
  END x[120]
  PIN x[121]
    DIRECTION INPUT ;
    USE SIGNAL ;
    PORT
      LAYER M4 ;
        RECT  0 103.536 0.084 103.56 ;
    END
  END x[121]
  PIN x[122]
    DIRECTION INPUT ;
    USE SIGNAL ;
    PORT
      LAYER M4 ;
        RECT  0 103.584 0.084 103.608 ;
    END
  END x[122]
  PIN x[123]
    DIRECTION INPUT ;
    USE SIGNAL ;
    PORT
      LAYER M4 ;
        RECT  0 103.632 0.084 103.656 ;
    END
  END x[123]
  PIN x[124]
    DIRECTION INPUT ;
    USE SIGNAL ;
    PORT
      LAYER M4 ;
        RECT  0 103.68 0.084 103.704 ;
    END
  END x[124]
  PIN x[125]
    DIRECTION INPUT ;
    USE SIGNAL ;
    PORT
      LAYER M4 ;
        RECT  0 103.728 0.084 103.752 ;
    END
  END x[125]
  PIN x[126]
    DIRECTION INPUT ;
    USE SIGNAL ;
    PORT
      LAYER M4 ;
        RECT  0 103.776 0.084 103.8 ;
    END
  END x[126]
  PIN x[127]
    DIRECTION INPUT ;
    USE SIGNAL ;
    PORT
      LAYER M4 ;
        RECT  0 103.824 0.084 103.848 ;
    END
  END x[127]
  PIN x[128]
    DIRECTION INPUT ;
    USE SIGNAL ;
    PORT
      LAYER M4 ;
        RECT  0 103.872 0.084 103.896 ;
    END
  END x[128]
  PIN x[129]
    DIRECTION INPUT ;
    USE SIGNAL ;
    PORT
      LAYER M4 ;
        RECT  0 103.92 0.084 103.944 ;
    END
  END x[129]
  PIN x[12]
    DIRECTION INPUT ;
    USE SIGNAL ;
    PORT
      LAYER M4 ;
        RECT  0 98.304 0.084 98.328 ;
    END
  END x[12]
  PIN x[130]
    DIRECTION INPUT ;
    USE SIGNAL ;
    PORT
      LAYER M4 ;
        RECT  0 103.968 0.084 103.992 ;
    END
  END x[130]
  PIN x[131]
    DIRECTION INPUT ;
    USE SIGNAL ;
    PORT
      LAYER M4 ;
        RECT  0 104.016 0.084 104.04 ;
    END
  END x[131]
  PIN x[132]
    DIRECTION INPUT ;
    USE SIGNAL ;
    PORT
      LAYER M4 ;
        RECT  0 104.064 0.084 104.088 ;
    END
  END x[132]
  PIN x[133]
    DIRECTION INPUT ;
    USE SIGNAL ;
    PORT
      LAYER M4 ;
        RECT  0 104.112 0.084 104.136 ;
    END
  END x[133]
  PIN x[134]
    DIRECTION INPUT ;
    USE SIGNAL ;
    PORT
      LAYER M4 ;
        RECT  0 104.16 0.084 104.184 ;
    END
  END x[134]
  PIN x[135]
    DIRECTION INPUT ;
    USE SIGNAL ;
    PORT
      LAYER M4 ;
        RECT  0 104.208 0.084 104.232 ;
    END
  END x[135]
  PIN x[136]
    DIRECTION INPUT ;
    USE SIGNAL ;
    PORT
      LAYER M4 ;
        RECT  0 104.256 0.084 104.28 ;
    END
  END x[136]
  PIN x[137]
    DIRECTION INPUT ;
    USE SIGNAL ;
    PORT
      LAYER M4 ;
        RECT  0 104.304 0.084 104.328 ;
    END
  END x[137]
  PIN x[138]
    DIRECTION INPUT ;
    USE SIGNAL ;
    PORT
      LAYER M4 ;
        RECT  0 104.352 0.084 104.376 ;
    END
  END x[138]
  PIN x[139]
    DIRECTION INPUT ;
    USE SIGNAL ;
    PORT
      LAYER M4 ;
        RECT  0 104.4 0.084 104.424 ;
    END
  END x[139]
  PIN x[13]
    DIRECTION INPUT ;
    USE SIGNAL ;
    PORT
      LAYER M4 ;
        RECT  0 98.352 0.084 98.376 ;
    END
  END x[13]
  PIN x[140]
    DIRECTION INPUT ;
    USE SIGNAL ;
    PORT
      LAYER M4 ;
        RECT  0 104.448 0.084 104.472 ;
    END
  END x[140]
  PIN x[141]
    DIRECTION INPUT ;
    USE SIGNAL ;
    PORT
      LAYER M4 ;
        RECT  0 104.496 0.084 104.52 ;
    END
  END x[141]
  PIN x[142]
    DIRECTION INPUT ;
    USE SIGNAL ;
    PORT
      LAYER M4 ;
        RECT  0 104.544 0.084 104.568 ;
    END
  END x[142]
  PIN x[143]
    DIRECTION INPUT ;
    USE SIGNAL ;
    PORT
      LAYER M4 ;
        RECT  0 104.592 0.084 104.616 ;
    END
  END x[143]
  PIN x[144]
    DIRECTION INPUT ;
    USE SIGNAL ;
    PORT
      LAYER M4 ;
        RECT  0 104.64 0.084 104.664 ;
    END
  END x[144]
  PIN x[145]
    DIRECTION INPUT ;
    USE SIGNAL ;
    PORT
      LAYER M4 ;
        RECT  0 104.688 0.084 104.712 ;
    END
  END x[145]
  PIN x[146]
    DIRECTION INPUT ;
    USE SIGNAL ;
    PORT
      LAYER M4 ;
        RECT  0 104.736 0.084 104.76 ;
    END
  END x[146]
  PIN x[147]
    DIRECTION INPUT ;
    USE SIGNAL ;
    PORT
      LAYER M4 ;
        RECT  0 104.784 0.084 104.808 ;
    END
  END x[147]
  PIN x[148]
    DIRECTION INPUT ;
    USE SIGNAL ;
    PORT
      LAYER M4 ;
        RECT  0 104.832 0.084 104.856 ;
    END
  END x[148]
  PIN x[149]
    DIRECTION INPUT ;
    USE SIGNAL ;
    PORT
      LAYER M4 ;
        RECT  0 104.88 0.084 104.904 ;
    END
  END x[149]
  PIN x[14]
    DIRECTION INPUT ;
    USE SIGNAL ;
    PORT
      LAYER M4 ;
        RECT  0 98.4 0.084 98.424 ;
    END
  END x[14]
  PIN x[150]
    DIRECTION INPUT ;
    USE SIGNAL ;
    PORT
      LAYER M4 ;
        RECT  0 104.928 0.084 104.952 ;
    END
  END x[150]
  PIN x[151]
    DIRECTION INPUT ;
    USE SIGNAL ;
    PORT
      LAYER M4 ;
        RECT  0 104.976 0.084 105 ;
    END
  END x[151]
  PIN x[152]
    DIRECTION INPUT ;
    USE SIGNAL ;
    PORT
      LAYER M4 ;
        RECT  0 105.024 0.084 105.048 ;
    END
  END x[152]
  PIN x[153]
    DIRECTION INPUT ;
    USE SIGNAL ;
    PORT
      LAYER M4 ;
        RECT  0 105.072 0.084 105.096 ;
    END
  END x[153]
  PIN x[154]
    DIRECTION INPUT ;
    USE SIGNAL ;
    PORT
      LAYER M4 ;
        RECT  0 105.12 0.084 105.144 ;
    END
  END x[154]
  PIN x[155]
    DIRECTION INPUT ;
    USE SIGNAL ;
    PORT
      LAYER M4 ;
        RECT  0 105.168 0.084 105.192 ;
    END
  END x[155]
  PIN x[156]
    DIRECTION INPUT ;
    USE SIGNAL ;
    PORT
      LAYER M4 ;
        RECT  0 105.216 0.084 105.24 ;
    END
  END x[156]
  PIN x[157]
    DIRECTION INPUT ;
    USE SIGNAL ;
    PORT
      LAYER M4 ;
        RECT  0 105.264 0.084 105.288 ;
    END
  END x[157]
  PIN x[158]
    DIRECTION INPUT ;
    USE SIGNAL ;
    PORT
      LAYER M4 ;
        RECT  0 105.312 0.084 105.336 ;
    END
  END x[158]
  PIN x[159]
    DIRECTION INPUT ;
    USE SIGNAL ;
    PORT
      LAYER M4 ;
        RECT  0 105.36 0.084 105.384 ;
    END
  END x[159]
  PIN x[15]
    DIRECTION INPUT ;
    USE SIGNAL ;
    PORT
      LAYER M4 ;
        RECT  0 98.448 0.084 98.472 ;
    END
  END x[15]
  PIN x[160]
    DIRECTION INPUT ;
    USE SIGNAL ;
    PORT
      LAYER M4 ;
        RECT  0 105.408 0.084 105.432 ;
    END
  END x[160]
  PIN x[161]
    DIRECTION INPUT ;
    USE SIGNAL ;
    PORT
      LAYER M4 ;
        RECT  0 105.456 0.084 105.48 ;
    END
  END x[161]
  PIN x[162]
    DIRECTION INPUT ;
    USE SIGNAL ;
    PORT
      LAYER M4 ;
        RECT  0 105.504 0.084 105.528 ;
    END
  END x[162]
  PIN x[163]
    DIRECTION INPUT ;
    USE SIGNAL ;
    PORT
      LAYER M4 ;
        RECT  0 105.552 0.084 105.576 ;
    END
  END x[163]
  PIN x[164]
    DIRECTION INPUT ;
    USE SIGNAL ;
    PORT
      LAYER M4 ;
        RECT  0 105.6 0.084 105.624 ;
    END
  END x[164]
  PIN x[165]
    DIRECTION INPUT ;
    USE SIGNAL ;
    PORT
      LAYER M4 ;
        RECT  0 105.648 0.084 105.672 ;
    END
  END x[165]
  PIN x[166]
    DIRECTION INPUT ;
    USE SIGNAL ;
    PORT
      LAYER M4 ;
        RECT  0 105.696 0.084 105.72 ;
    END
  END x[166]
  PIN x[167]
    DIRECTION INPUT ;
    USE SIGNAL ;
    PORT
      LAYER M4 ;
        RECT  0 105.744 0.084 105.768 ;
    END
  END x[167]
  PIN x[168]
    DIRECTION INPUT ;
    USE SIGNAL ;
    PORT
      LAYER M4 ;
        RECT  0 105.792 0.084 105.816 ;
    END
  END x[168]
  PIN x[169]
    DIRECTION INPUT ;
    USE SIGNAL ;
    PORT
      LAYER M4 ;
        RECT  0 105.84 0.084 105.864 ;
    END
  END x[169]
  PIN x[16]
    DIRECTION INPUT ;
    USE SIGNAL ;
    PORT
      LAYER M4 ;
        RECT  0 98.496 0.084 98.52 ;
    END
  END x[16]
  PIN x[170]
    DIRECTION INPUT ;
    USE SIGNAL ;
    PORT
      LAYER M4 ;
        RECT  0 105.888 0.084 105.912 ;
    END
  END x[170]
  PIN x[171]
    DIRECTION INPUT ;
    USE SIGNAL ;
    PORT
      LAYER M4 ;
        RECT  0 105.936 0.084 105.96 ;
    END
  END x[171]
  PIN x[172]
    DIRECTION INPUT ;
    USE SIGNAL ;
    PORT
      LAYER M4 ;
        RECT  0 105.984 0.084 106.008 ;
    END
  END x[172]
  PIN x[173]
    DIRECTION INPUT ;
    USE SIGNAL ;
    PORT
      LAYER M4 ;
        RECT  0 106.032 0.084 106.056 ;
    END
  END x[173]
  PIN x[174]
    DIRECTION INPUT ;
    USE SIGNAL ;
    PORT
      LAYER M4 ;
        RECT  0 106.08 0.084 106.104 ;
    END
  END x[174]
  PIN x[175]
    DIRECTION INPUT ;
    USE SIGNAL ;
    PORT
      LAYER M4 ;
        RECT  0 106.128 0.084 106.152 ;
    END
  END x[175]
  PIN x[176]
    DIRECTION INPUT ;
    USE SIGNAL ;
    PORT
      LAYER M4 ;
        RECT  0 106.176 0.084 106.2 ;
    END
  END x[176]
  PIN x[177]
    DIRECTION INPUT ;
    USE SIGNAL ;
    PORT
      LAYER M4 ;
        RECT  0 106.224 0.084 106.248 ;
    END
  END x[177]
  PIN x[178]
    DIRECTION INPUT ;
    USE SIGNAL ;
    PORT
      LAYER M4 ;
        RECT  0 106.272 0.084 106.296 ;
    END
  END x[178]
  PIN x[179]
    DIRECTION INPUT ;
    USE SIGNAL ;
    PORT
      LAYER M4 ;
        RECT  0 106.32 0.084 106.344 ;
    END
  END x[179]
  PIN x[17]
    DIRECTION INPUT ;
    USE SIGNAL ;
    PORT
      LAYER M4 ;
        RECT  0 98.544 0.084 98.568 ;
    END
  END x[17]
  PIN x[180]
    DIRECTION INPUT ;
    USE SIGNAL ;
    PORT
      LAYER M4 ;
        RECT  0 106.368 0.084 106.392 ;
    END
  END x[180]
  PIN x[181]
    DIRECTION INPUT ;
    USE SIGNAL ;
    PORT
      LAYER M4 ;
        RECT  0 106.416 0.084 106.44 ;
    END
  END x[181]
  PIN x[182]
    DIRECTION INPUT ;
    USE SIGNAL ;
    PORT
      LAYER M4 ;
        RECT  0 106.464 0.084 106.488 ;
    END
  END x[182]
  PIN x[183]
    DIRECTION INPUT ;
    USE SIGNAL ;
    PORT
      LAYER M4 ;
        RECT  0 106.512 0.084 106.536 ;
    END
  END x[183]
  PIN x[184]
    DIRECTION INPUT ;
    USE SIGNAL ;
    PORT
      LAYER M4 ;
        RECT  0 106.56 0.084 106.584 ;
    END
  END x[184]
  PIN x[185]
    DIRECTION INPUT ;
    USE SIGNAL ;
    PORT
      LAYER M4 ;
        RECT  0 106.608 0.084 106.632 ;
    END
  END x[185]
  PIN x[186]
    DIRECTION INPUT ;
    USE SIGNAL ;
    PORT
      LAYER M4 ;
        RECT  0 106.656 0.084 106.68 ;
    END
  END x[186]
  PIN x[187]
    DIRECTION INPUT ;
    USE SIGNAL ;
    PORT
      LAYER M4 ;
        RECT  0 106.704 0.084 106.728 ;
    END
  END x[187]
  PIN x[188]
    DIRECTION INPUT ;
    USE SIGNAL ;
    PORT
      LAYER M4 ;
        RECT  0 106.752 0.084 106.776 ;
    END
  END x[188]
  PIN x[189]
    DIRECTION INPUT ;
    USE SIGNAL ;
    PORT
      LAYER M4 ;
        RECT  0 106.8 0.084 106.824 ;
    END
  END x[189]
  PIN x[18]
    DIRECTION INPUT ;
    USE SIGNAL ;
    PORT
      LAYER M4 ;
        RECT  0 98.592 0.084 98.616 ;
    END
  END x[18]
  PIN x[190]
    DIRECTION INPUT ;
    USE SIGNAL ;
    PORT
      LAYER M4 ;
        RECT  0 106.848 0.084 106.872 ;
    END
  END x[190]
  PIN x[191]
    DIRECTION INPUT ;
    USE SIGNAL ;
    PORT
      LAYER M4 ;
        RECT  0 106.896 0.084 106.92 ;
    END
  END x[191]
  PIN x[192]
    DIRECTION INPUT ;
    USE SIGNAL ;
    PORT
      LAYER M4 ;
        RECT  0 106.944 0.084 106.968 ;
    END
  END x[192]
  PIN x[193]
    DIRECTION INPUT ;
    USE SIGNAL ;
    PORT
      LAYER M4 ;
        RECT  0 106.992 0.084 107.016 ;
    END
  END x[193]
  PIN x[194]
    DIRECTION INPUT ;
    USE SIGNAL ;
    PORT
      LAYER M4 ;
        RECT  0 107.04 0.084 107.064 ;
    END
  END x[194]
  PIN x[195]
    DIRECTION INPUT ;
    USE SIGNAL ;
    PORT
      LAYER M4 ;
        RECT  0 107.088 0.084 107.112 ;
    END
  END x[195]
  PIN x[196]
    DIRECTION INPUT ;
    USE SIGNAL ;
    PORT
      LAYER M4 ;
        RECT  0 107.136 0.084 107.16 ;
    END
  END x[196]
  PIN x[197]
    DIRECTION INPUT ;
    USE SIGNAL ;
    PORT
      LAYER M4 ;
        RECT  0 107.184 0.084 107.208 ;
    END
  END x[197]
  PIN x[198]
    DIRECTION INPUT ;
    USE SIGNAL ;
    PORT
      LAYER M4 ;
        RECT  0 107.232 0.084 107.256 ;
    END
  END x[198]
  PIN x[199]
    DIRECTION INPUT ;
    USE SIGNAL ;
    PORT
      LAYER M4 ;
        RECT  0 107.28 0.084 107.304 ;
    END
  END x[199]
  PIN x[19]
    DIRECTION INPUT ;
    USE SIGNAL ;
    PORT
      LAYER M4 ;
        RECT  0 98.64 0.084 98.664 ;
    END
  END x[19]
  PIN x[1]
    DIRECTION INPUT ;
    USE SIGNAL ;
    PORT
      LAYER M4 ;
        RECT  0 97.776 0.084 97.8 ;
    END
  END x[1]
  PIN x[200]
    DIRECTION INPUT ;
    USE SIGNAL ;
    PORT
      LAYER M4 ;
        RECT  0 107.328 0.084 107.352 ;
    END
  END x[200]
  PIN x[201]
    DIRECTION INPUT ;
    USE SIGNAL ;
    PORT
      LAYER M4 ;
        RECT  0 107.376 0.084 107.4 ;
    END
  END x[201]
  PIN x[202]
    DIRECTION INPUT ;
    USE SIGNAL ;
    PORT
      LAYER M4 ;
        RECT  0 107.424 0.084 107.448 ;
    END
  END x[202]
  PIN x[203]
    DIRECTION INPUT ;
    USE SIGNAL ;
    PORT
      LAYER M4 ;
        RECT  0 107.472 0.084 107.496 ;
    END
  END x[203]
  PIN x[204]
    DIRECTION INPUT ;
    USE SIGNAL ;
    PORT
      LAYER M4 ;
        RECT  0 107.52 0.084 107.544 ;
    END
  END x[204]
  PIN x[205]
    DIRECTION INPUT ;
    USE SIGNAL ;
    PORT
      LAYER M4 ;
        RECT  0 107.568 0.084 107.592 ;
    END
  END x[205]
  PIN x[206]
    DIRECTION INPUT ;
    USE SIGNAL ;
    PORT
      LAYER M4 ;
        RECT  0 107.616 0.084 107.64 ;
    END
  END x[206]
  PIN x[207]
    DIRECTION INPUT ;
    USE SIGNAL ;
    PORT
      LAYER M4 ;
        RECT  0 107.664 0.084 107.688 ;
    END
  END x[207]
  PIN x[208]
    DIRECTION INPUT ;
    USE SIGNAL ;
    PORT
      LAYER M4 ;
        RECT  0 107.712 0.084 107.736 ;
    END
  END x[208]
  PIN x[209]
    DIRECTION INPUT ;
    USE SIGNAL ;
    PORT
      LAYER M4 ;
        RECT  0 107.76 0.084 107.784 ;
    END
  END x[209]
  PIN x[20]
    DIRECTION INPUT ;
    USE SIGNAL ;
    PORT
      LAYER M4 ;
        RECT  0 98.688 0.084 98.712 ;
    END
  END x[20]
  PIN x[210]
    DIRECTION INPUT ;
    USE SIGNAL ;
    PORT
      LAYER M4 ;
        RECT  0 107.808 0.084 107.832 ;
    END
  END x[210]
  PIN x[211]
    DIRECTION INPUT ;
    USE SIGNAL ;
    PORT
      LAYER M4 ;
        RECT  0 107.856 0.084 107.88 ;
    END
  END x[211]
  PIN x[212]
    DIRECTION INPUT ;
    USE SIGNAL ;
    PORT
      LAYER M4 ;
        RECT  0 107.904 0.084 107.928 ;
    END
  END x[212]
  PIN x[213]
    DIRECTION INPUT ;
    USE SIGNAL ;
    PORT
      LAYER M4 ;
        RECT  0 107.952 0.084 107.976 ;
    END
  END x[213]
  PIN x[214]
    DIRECTION INPUT ;
    USE SIGNAL ;
    PORT
      LAYER M4 ;
        RECT  0 108 0.084 108.024 ;
    END
  END x[214]
  PIN x[215]
    DIRECTION INPUT ;
    USE SIGNAL ;
    PORT
      LAYER M4 ;
        RECT  0 108.048 0.084 108.072 ;
    END
  END x[215]
  PIN x[216]
    DIRECTION INPUT ;
    USE SIGNAL ;
    PORT
      LAYER M4 ;
        RECT  0 108.096 0.084 108.12 ;
    END
  END x[216]
  PIN x[217]
    DIRECTION INPUT ;
    USE SIGNAL ;
    PORT
      LAYER M4 ;
        RECT  0 108.144 0.084 108.168 ;
    END
  END x[217]
  PIN x[218]
    DIRECTION INPUT ;
    USE SIGNAL ;
    PORT
      LAYER M4 ;
        RECT  0 108.192 0.084 108.216 ;
    END
  END x[218]
  PIN x[219]
    DIRECTION INPUT ;
    USE SIGNAL ;
    PORT
      LAYER M4 ;
        RECT  0 108.24 0.084 108.264 ;
    END
  END x[219]
  PIN x[21]
    DIRECTION INPUT ;
    USE SIGNAL ;
    PORT
      LAYER M4 ;
        RECT  0 98.736 0.084 98.76 ;
    END
  END x[21]
  PIN x[220]
    DIRECTION INPUT ;
    USE SIGNAL ;
    PORT
      LAYER M4 ;
        RECT  0 108.288 0.084 108.312 ;
    END
  END x[220]
  PIN x[221]
    DIRECTION INPUT ;
    USE SIGNAL ;
    PORT
      LAYER M4 ;
        RECT  0 108.336 0.084 108.36 ;
    END
  END x[221]
  PIN x[222]
    DIRECTION INPUT ;
    USE SIGNAL ;
    PORT
      LAYER M4 ;
        RECT  0 108.384 0.084 108.408 ;
    END
  END x[222]
  PIN x[223]
    DIRECTION INPUT ;
    USE SIGNAL ;
    PORT
      LAYER M4 ;
        RECT  0 108.432 0.084 108.456 ;
    END
  END x[223]
  PIN x[224]
    DIRECTION INPUT ;
    USE SIGNAL ;
    PORT
      LAYER M4 ;
        RECT  0 108.48 0.084 108.504 ;
    END
  END x[224]
  PIN x[225]
    DIRECTION INPUT ;
    USE SIGNAL ;
    PORT
      LAYER M4 ;
        RECT  0 108.528 0.084 108.552 ;
    END
  END x[225]
  PIN x[226]
    DIRECTION INPUT ;
    USE SIGNAL ;
    PORT
      LAYER M4 ;
        RECT  0 108.576 0.084 108.6 ;
    END
  END x[226]
  PIN x[227]
    DIRECTION INPUT ;
    USE SIGNAL ;
    PORT
      LAYER M4 ;
        RECT  0 108.624 0.084 108.648 ;
    END
  END x[227]
  PIN x[228]
    DIRECTION INPUT ;
    USE SIGNAL ;
    PORT
      LAYER M4 ;
        RECT  0 108.672 0.084 108.696 ;
    END
  END x[228]
  PIN x[229]
    DIRECTION INPUT ;
    USE SIGNAL ;
    PORT
      LAYER M4 ;
        RECT  0 108.72 0.084 108.744 ;
    END
  END x[229]
  PIN x[22]
    DIRECTION INPUT ;
    USE SIGNAL ;
    PORT
      LAYER M4 ;
        RECT  0 98.784 0.084 98.808 ;
    END
  END x[22]
  PIN x[230]
    DIRECTION INPUT ;
    USE SIGNAL ;
    PORT
      LAYER M4 ;
        RECT  0 108.768 0.084 108.792 ;
    END
  END x[230]
  PIN x[231]
    DIRECTION INPUT ;
    USE SIGNAL ;
    PORT
      LAYER M4 ;
        RECT  0 108.816 0.084 108.84 ;
    END
  END x[231]
  PIN x[232]
    DIRECTION INPUT ;
    USE SIGNAL ;
    PORT
      LAYER M4 ;
        RECT  0 108.864 0.084 108.888 ;
    END
  END x[232]
  PIN x[233]
    DIRECTION INPUT ;
    USE SIGNAL ;
    PORT
      LAYER M4 ;
        RECT  0 108.912 0.084 108.936 ;
    END
  END x[233]
  PIN x[234]
    DIRECTION INPUT ;
    USE SIGNAL ;
    PORT
      LAYER M4 ;
        RECT  0 108.96 0.084 108.984 ;
    END
  END x[234]
  PIN x[235]
    DIRECTION INPUT ;
    USE SIGNAL ;
    PORT
      LAYER M4 ;
        RECT  0 109.008 0.084 109.032 ;
    END
  END x[235]
  PIN x[236]
    DIRECTION INPUT ;
    USE SIGNAL ;
    PORT
      LAYER M4 ;
        RECT  0 109.056 0.084 109.08 ;
    END
  END x[236]
  PIN x[237]
    DIRECTION INPUT ;
    USE SIGNAL ;
    PORT
      LAYER M4 ;
        RECT  0 109.104 0.084 109.128 ;
    END
  END x[237]
  PIN x[238]
    DIRECTION INPUT ;
    USE SIGNAL ;
    PORT
      LAYER M4 ;
        RECT  0 109.152 0.084 109.176 ;
    END
  END x[238]
  PIN x[239]
    DIRECTION INPUT ;
    USE SIGNAL ;
    PORT
      LAYER M4 ;
        RECT  0 109.2 0.084 109.224 ;
    END
  END x[239]
  PIN x[23]
    DIRECTION INPUT ;
    USE SIGNAL ;
    PORT
      LAYER M4 ;
        RECT  0 98.832 0.084 98.856 ;
    END
  END x[23]
  PIN x[240]
    DIRECTION INPUT ;
    USE SIGNAL ;
    PORT
      LAYER M4 ;
        RECT  0 109.248 0.084 109.272 ;
    END
  END x[240]
  PIN x[241]
    DIRECTION INPUT ;
    USE SIGNAL ;
    PORT
      LAYER M4 ;
        RECT  0 109.296 0.084 109.32 ;
    END
  END x[241]
  PIN x[242]
    DIRECTION INPUT ;
    USE SIGNAL ;
    PORT
      LAYER M4 ;
        RECT  0 109.344 0.084 109.368 ;
    END
  END x[242]
  PIN x[243]
    DIRECTION INPUT ;
    USE SIGNAL ;
    PORT
      LAYER M4 ;
        RECT  0 109.392 0.084 109.416 ;
    END
  END x[243]
  PIN x[244]
    DIRECTION INPUT ;
    USE SIGNAL ;
    PORT
      LAYER M4 ;
        RECT  0 109.44 0.084 109.464 ;
    END
  END x[244]
  PIN x[245]
    DIRECTION INPUT ;
    USE SIGNAL ;
    PORT
      LAYER M4 ;
        RECT  0 109.488 0.084 109.512 ;
    END
  END x[245]
  PIN x[246]
    DIRECTION INPUT ;
    USE SIGNAL ;
    PORT
      LAYER M4 ;
        RECT  0 109.536 0.084 109.56 ;
    END
  END x[246]
  PIN x[247]
    DIRECTION INPUT ;
    USE SIGNAL ;
    PORT
      LAYER M4 ;
        RECT  0 109.584 0.084 109.608 ;
    END
  END x[247]
  PIN x[248]
    DIRECTION INPUT ;
    USE SIGNAL ;
    PORT
      LAYER M4 ;
        RECT  0 109.632 0.084 109.656 ;
    END
  END x[248]
  PIN x[249]
    DIRECTION INPUT ;
    USE SIGNAL ;
    PORT
      LAYER M4 ;
        RECT  0 109.68 0.084 109.704 ;
    END
  END x[249]
  PIN x[24]
    DIRECTION INPUT ;
    USE SIGNAL ;
    PORT
      LAYER M4 ;
        RECT  0 98.88 0.084 98.904 ;
    END
  END x[24]
  PIN x[250]
    DIRECTION INPUT ;
    USE SIGNAL ;
    PORT
      LAYER M4 ;
        RECT  0 109.728 0.084 109.752 ;
    END
  END x[250]
  PIN x[251]
    DIRECTION INPUT ;
    USE SIGNAL ;
    PORT
      LAYER M4 ;
        RECT  0 109.776 0.084 109.8 ;
    END
  END x[251]
  PIN x[252]
    DIRECTION INPUT ;
    USE SIGNAL ;
    PORT
      LAYER M4 ;
        RECT  0 109.824 0.084 109.848 ;
    END
  END x[252]
  PIN x[253]
    DIRECTION INPUT ;
    USE SIGNAL ;
    PORT
      LAYER M4 ;
        RECT  0 109.872 0.084 109.896 ;
    END
  END x[253]
  PIN x[254]
    DIRECTION INPUT ;
    USE SIGNAL ;
    PORT
      LAYER M4 ;
        RECT  0 109.92 0.084 109.944 ;
    END
  END x[254]
  PIN x[255]
    DIRECTION INPUT ;
    USE SIGNAL ;
    PORT
      LAYER M4 ;
        RECT  0 109.968 0.084 109.992 ;
    END
  END x[255]
  PIN x[256]
    DIRECTION INPUT ;
    USE SIGNAL ;
    PORT
      LAYER M4 ;
        RECT  0 110.016 0.084 110.04 ;
    END
  END x[256]
  PIN x[257]
    DIRECTION INPUT ;
    USE SIGNAL ;
    PORT
      LAYER M4 ;
        RECT  0 110.064 0.084 110.088 ;
    END
  END x[257]
  PIN x[258]
    DIRECTION INPUT ;
    USE SIGNAL ;
    PORT
      LAYER M4 ;
        RECT  0 110.112 0.084 110.136 ;
    END
  END x[258]
  PIN x[259]
    DIRECTION INPUT ;
    USE SIGNAL ;
    PORT
      LAYER M4 ;
        RECT  0 110.16 0.084 110.184 ;
    END
  END x[259]
  PIN x[25]
    DIRECTION INPUT ;
    USE SIGNAL ;
    PORT
      LAYER M4 ;
        RECT  0 98.928 0.084 98.952 ;
    END
  END x[25]
  PIN x[260]
    DIRECTION INPUT ;
    USE SIGNAL ;
    PORT
      LAYER M4 ;
        RECT  0 110.208 0.084 110.232 ;
    END
  END x[260]
  PIN x[261]
    DIRECTION INPUT ;
    USE SIGNAL ;
    PORT
      LAYER M4 ;
        RECT  0 110.256 0.084 110.28 ;
    END
  END x[261]
  PIN x[262]
    DIRECTION INPUT ;
    USE SIGNAL ;
    PORT
      LAYER M4 ;
        RECT  0 110.304 0.084 110.328 ;
    END
  END x[262]
  PIN x[263]
    DIRECTION INPUT ;
    USE SIGNAL ;
    PORT
      LAYER M4 ;
        RECT  0 110.352 0.084 110.376 ;
    END
  END x[263]
  PIN x[264]
    DIRECTION INPUT ;
    USE SIGNAL ;
    PORT
      LAYER M4 ;
        RECT  0 110.4 0.084 110.424 ;
    END
  END x[264]
  PIN x[265]
    DIRECTION INPUT ;
    USE SIGNAL ;
    PORT
      LAYER M4 ;
        RECT  0 110.448 0.084 110.472 ;
    END
  END x[265]
  PIN x[266]
    DIRECTION INPUT ;
    USE SIGNAL ;
    PORT
      LAYER M4 ;
        RECT  0 110.496 0.084 110.52 ;
    END
  END x[266]
  PIN x[267]
    DIRECTION INPUT ;
    USE SIGNAL ;
    PORT
      LAYER M4 ;
        RECT  0 110.544 0.084 110.568 ;
    END
  END x[267]
  PIN x[268]
    DIRECTION INPUT ;
    USE SIGNAL ;
    PORT
      LAYER M4 ;
        RECT  0 110.592 0.084 110.616 ;
    END
  END x[268]
  PIN x[269]
    DIRECTION INPUT ;
    USE SIGNAL ;
    PORT
      LAYER M4 ;
        RECT  0 110.64 0.084 110.664 ;
    END
  END x[269]
  PIN x[26]
    DIRECTION INPUT ;
    USE SIGNAL ;
    PORT
      LAYER M4 ;
        RECT  0 98.976 0.084 99 ;
    END
  END x[26]
  PIN x[270]
    DIRECTION INPUT ;
    USE SIGNAL ;
    PORT
      LAYER M4 ;
        RECT  0 110.688 0.084 110.712 ;
    END
  END x[270]
  PIN x[271]
    DIRECTION INPUT ;
    USE SIGNAL ;
    PORT
      LAYER M4 ;
        RECT  0 110.736 0.084 110.76 ;
    END
  END x[271]
  PIN x[272]
    DIRECTION INPUT ;
    USE SIGNAL ;
    PORT
      LAYER M4 ;
        RECT  0 110.784 0.084 110.808 ;
    END
  END x[272]
  PIN x[273]
    DIRECTION INPUT ;
    USE SIGNAL ;
    PORT
      LAYER M4 ;
        RECT  0 110.832 0.084 110.856 ;
    END
  END x[273]
  PIN x[274]
    DIRECTION INPUT ;
    USE SIGNAL ;
    PORT
      LAYER M4 ;
        RECT  0 110.88 0.084 110.904 ;
    END
  END x[274]
  PIN x[275]
    DIRECTION INPUT ;
    USE SIGNAL ;
    PORT
      LAYER M4 ;
        RECT  0 110.928 0.084 110.952 ;
    END
  END x[275]
  PIN x[276]
    DIRECTION INPUT ;
    USE SIGNAL ;
    PORT
      LAYER M4 ;
        RECT  0 110.976 0.084 111 ;
    END
  END x[276]
  PIN x[277]
    DIRECTION INPUT ;
    USE SIGNAL ;
    PORT
      LAYER M4 ;
        RECT  0 111.024 0.084 111.048 ;
    END
  END x[277]
  PIN x[278]
    DIRECTION INPUT ;
    USE SIGNAL ;
    PORT
      LAYER M4 ;
        RECT  0 111.072 0.084 111.096 ;
    END
  END x[278]
  PIN x[279]
    DIRECTION INPUT ;
    USE SIGNAL ;
    PORT
      LAYER M4 ;
        RECT  0 111.12 0.084 111.144 ;
    END
  END x[279]
  PIN x[27]
    DIRECTION INPUT ;
    USE SIGNAL ;
    PORT
      LAYER M4 ;
        RECT  0 99.024 0.084 99.048 ;
    END
  END x[27]
  PIN x[280]
    DIRECTION INPUT ;
    USE SIGNAL ;
    PORT
      LAYER M4 ;
        RECT  0 111.168 0.084 111.192 ;
    END
  END x[280]
  PIN x[281]
    DIRECTION INPUT ;
    USE SIGNAL ;
    PORT
      LAYER M4 ;
        RECT  0 111.216 0.084 111.24 ;
    END
  END x[281]
  PIN x[282]
    DIRECTION INPUT ;
    USE SIGNAL ;
    PORT
      LAYER M4 ;
        RECT  0 111.264 0.084 111.288 ;
    END
  END x[282]
  PIN x[283]
    DIRECTION INPUT ;
    USE SIGNAL ;
    PORT
      LAYER M4 ;
        RECT  0 111.312 0.084 111.336 ;
    END
  END x[283]
  PIN x[284]
    DIRECTION INPUT ;
    USE SIGNAL ;
    PORT
      LAYER M4 ;
        RECT  0 111.36 0.084 111.384 ;
    END
  END x[284]
  PIN x[285]
    DIRECTION INPUT ;
    USE SIGNAL ;
    PORT
      LAYER M4 ;
        RECT  0 111.408 0.084 111.432 ;
    END
  END x[285]
  PIN x[286]
    DIRECTION INPUT ;
    USE SIGNAL ;
    PORT
      LAYER M4 ;
        RECT  0 111.456 0.084 111.48 ;
    END
  END x[286]
  PIN x[287]
    DIRECTION INPUT ;
    USE SIGNAL ;
    PORT
      LAYER M4 ;
        RECT  0 111.504 0.084 111.528 ;
    END
  END x[287]
  PIN x[288]
    DIRECTION INPUT ;
    USE SIGNAL ;
    PORT
      LAYER M4 ;
        RECT  0 111.552 0.084 111.576 ;
    END
  END x[288]
  PIN x[289]
    DIRECTION INPUT ;
    USE SIGNAL ;
    PORT
      LAYER M4 ;
        RECT  0 111.6 0.084 111.624 ;
    END
  END x[289]
  PIN x[28]
    DIRECTION INPUT ;
    USE SIGNAL ;
    PORT
      LAYER M4 ;
        RECT  0 99.072 0.084 99.096 ;
    END
  END x[28]
  PIN x[290]
    DIRECTION INPUT ;
    USE SIGNAL ;
    PORT
      LAYER M4 ;
        RECT  0 111.648 0.084 111.672 ;
    END
  END x[290]
  PIN x[291]
    DIRECTION INPUT ;
    USE SIGNAL ;
    PORT
      LAYER M4 ;
        RECT  0 111.696 0.084 111.72 ;
    END
  END x[291]
  PIN x[292]
    DIRECTION INPUT ;
    USE SIGNAL ;
    PORT
      LAYER M4 ;
        RECT  0 111.744 0.084 111.768 ;
    END
  END x[292]
  PIN x[293]
    DIRECTION INPUT ;
    USE SIGNAL ;
    PORT
      LAYER M4 ;
        RECT  0 111.792 0.084 111.816 ;
    END
  END x[293]
  PIN x[294]
    DIRECTION INPUT ;
    USE SIGNAL ;
    PORT
      LAYER M4 ;
        RECT  0 111.84 0.084 111.864 ;
    END
  END x[294]
  PIN x[295]
    DIRECTION INPUT ;
    USE SIGNAL ;
    PORT
      LAYER M4 ;
        RECT  0 111.888 0.084 111.912 ;
    END
  END x[295]
  PIN x[296]
    DIRECTION INPUT ;
    USE SIGNAL ;
    PORT
      LAYER M4 ;
        RECT  0 111.936 0.084 111.96 ;
    END
  END x[296]
  PIN x[297]
    DIRECTION INPUT ;
    USE SIGNAL ;
    PORT
      LAYER M4 ;
        RECT  0 111.984 0.084 112.008 ;
    END
  END x[297]
  PIN x[298]
    DIRECTION INPUT ;
    USE SIGNAL ;
    PORT
      LAYER M4 ;
        RECT  0 112.032 0.084 112.056 ;
    END
  END x[298]
  PIN x[299]
    DIRECTION INPUT ;
    USE SIGNAL ;
    PORT
      LAYER M4 ;
        RECT  0 112.08 0.084 112.104 ;
    END
  END x[299]
  PIN x[29]
    DIRECTION INPUT ;
    USE SIGNAL ;
    PORT
      LAYER M4 ;
        RECT  0 99.12 0.084 99.144 ;
    END
  END x[29]
  PIN x[2]
    DIRECTION INPUT ;
    USE SIGNAL ;
    PORT
      LAYER M4 ;
        RECT  0 97.824 0.084 97.848 ;
    END
  END x[2]
  PIN x[300]
    DIRECTION INPUT ;
    USE SIGNAL ;
    PORT
      LAYER M4 ;
        RECT  0 112.128 0.084 112.152 ;
    END
  END x[300]
  PIN x[301]
    DIRECTION INPUT ;
    USE SIGNAL ;
    PORT
      LAYER M4 ;
        RECT  0 112.176 0.084 112.2 ;
    END
  END x[301]
  PIN x[302]
    DIRECTION INPUT ;
    USE SIGNAL ;
    PORT
      LAYER M4 ;
        RECT  0 112.224 0.084 112.248 ;
    END
  END x[302]
  PIN x[303]
    DIRECTION INPUT ;
    USE SIGNAL ;
    PORT
      LAYER M4 ;
        RECT  0 112.272 0.084 112.296 ;
    END
  END x[303]
  PIN x[304]
    DIRECTION INPUT ;
    USE SIGNAL ;
    PORT
      LAYER M4 ;
        RECT  0 112.32 0.084 112.344 ;
    END
  END x[304]
  PIN x[305]
    DIRECTION INPUT ;
    USE SIGNAL ;
    PORT
      LAYER M4 ;
        RECT  0 112.368 0.084 112.392 ;
    END
  END x[305]
  PIN x[306]
    DIRECTION INPUT ;
    USE SIGNAL ;
    PORT
      LAYER M4 ;
        RECT  0 112.416 0.084 112.44 ;
    END
  END x[306]
  PIN x[307]
    DIRECTION INPUT ;
    USE SIGNAL ;
    PORT
      LAYER M4 ;
        RECT  0 112.464 0.084 112.488 ;
    END
  END x[307]
  PIN x[308]
    DIRECTION INPUT ;
    USE SIGNAL ;
    PORT
      LAYER M4 ;
        RECT  0 112.512 0.084 112.536 ;
    END
  END x[308]
  PIN x[309]
    DIRECTION INPUT ;
    USE SIGNAL ;
    PORT
      LAYER M4 ;
        RECT  0 112.56 0.084 112.584 ;
    END
  END x[309]
  PIN x[30]
    DIRECTION INPUT ;
    USE SIGNAL ;
    PORT
      LAYER M4 ;
        RECT  0 99.168 0.084 99.192 ;
    END
  END x[30]
  PIN x[310]
    DIRECTION INPUT ;
    USE SIGNAL ;
    PORT
      LAYER M4 ;
        RECT  0 112.608 0.084 112.632 ;
    END
  END x[310]
  PIN x[311]
    DIRECTION INPUT ;
    USE SIGNAL ;
    PORT
      LAYER M4 ;
        RECT  0 112.656 0.084 112.68 ;
    END
  END x[311]
  PIN x[312]
    DIRECTION INPUT ;
    USE SIGNAL ;
    PORT
      LAYER M4 ;
        RECT  0 112.704 0.084 112.728 ;
    END
  END x[312]
  PIN x[313]
    DIRECTION INPUT ;
    USE SIGNAL ;
    PORT
      LAYER M4 ;
        RECT  0 112.752 0.084 112.776 ;
    END
  END x[313]
  PIN x[314]
    DIRECTION INPUT ;
    USE SIGNAL ;
    PORT
      LAYER M4 ;
        RECT  0 112.8 0.084 112.824 ;
    END
  END x[314]
  PIN x[315]
    DIRECTION INPUT ;
    USE SIGNAL ;
    PORT
      LAYER M4 ;
        RECT  0 112.848 0.084 112.872 ;
    END
  END x[315]
  PIN x[316]
    DIRECTION INPUT ;
    USE SIGNAL ;
    PORT
      LAYER M4 ;
        RECT  0 112.896 0.084 112.92 ;
    END
  END x[316]
  PIN x[317]
    DIRECTION INPUT ;
    USE SIGNAL ;
    PORT
      LAYER M4 ;
        RECT  0 112.944 0.084 112.968 ;
    END
  END x[317]
  PIN x[318]
    DIRECTION INPUT ;
    USE SIGNAL ;
    PORT
      LAYER M4 ;
        RECT  0 112.992 0.084 113.016 ;
    END
  END x[318]
  PIN x[319]
    DIRECTION INPUT ;
    USE SIGNAL ;
    PORT
      LAYER M4 ;
        RECT  0 113.04 0.084 113.064 ;
    END
  END x[319]
  PIN x[31]
    DIRECTION INPUT ;
    USE SIGNAL ;
    PORT
      LAYER M4 ;
        RECT  0 99.216 0.084 99.24 ;
    END
  END x[31]
  PIN x[320]
    DIRECTION INPUT ;
    USE SIGNAL ;
    PORT
      LAYER M4 ;
        RECT  0 113.088 0.084 113.112 ;
    END
  END x[320]
  PIN x[321]
    DIRECTION INPUT ;
    USE SIGNAL ;
    PORT
      LAYER M4 ;
        RECT  0 113.136 0.084 113.16 ;
    END
  END x[321]
  PIN x[322]
    DIRECTION INPUT ;
    USE SIGNAL ;
    PORT
      LAYER M4 ;
        RECT  0 113.184 0.084 113.208 ;
    END
  END x[322]
  PIN x[323]
    DIRECTION INPUT ;
    USE SIGNAL ;
    PORT
      LAYER M4 ;
        RECT  0 113.232 0.084 113.256 ;
    END
  END x[323]
  PIN x[324]
    DIRECTION INPUT ;
    USE SIGNAL ;
    PORT
      LAYER M4 ;
        RECT  0 113.28 0.084 113.304 ;
    END
  END x[324]
  PIN x[325]
    DIRECTION INPUT ;
    USE SIGNAL ;
    PORT
      LAYER M4 ;
        RECT  0 113.328 0.084 113.352 ;
    END
  END x[325]
  PIN x[326]
    DIRECTION INPUT ;
    USE SIGNAL ;
    PORT
      LAYER M4 ;
        RECT  0 113.376 0.084 113.4 ;
    END
  END x[326]
  PIN x[327]
    DIRECTION INPUT ;
    USE SIGNAL ;
    PORT
      LAYER M4 ;
        RECT  0 113.424 0.084 113.448 ;
    END
  END x[327]
  PIN x[328]
    DIRECTION INPUT ;
    USE SIGNAL ;
    PORT
      LAYER M4 ;
        RECT  0 113.472 0.084 113.496 ;
    END
  END x[328]
  PIN x[329]
    DIRECTION INPUT ;
    USE SIGNAL ;
    PORT
      LAYER M4 ;
        RECT  0 113.52 0.084 113.544 ;
    END
  END x[329]
  PIN x[32]
    DIRECTION INPUT ;
    USE SIGNAL ;
    PORT
      LAYER M4 ;
        RECT  0 99.264 0.084 99.288 ;
    END
  END x[32]
  PIN x[330]
    DIRECTION INPUT ;
    USE SIGNAL ;
    PORT
      LAYER M4 ;
        RECT  0 113.568 0.084 113.592 ;
    END
  END x[330]
  PIN x[331]
    DIRECTION INPUT ;
    USE SIGNAL ;
    PORT
      LAYER M4 ;
        RECT  0 113.616 0.084 113.64 ;
    END
  END x[331]
  PIN x[332]
    DIRECTION INPUT ;
    USE SIGNAL ;
    PORT
      LAYER M4 ;
        RECT  0 113.664 0.084 113.688 ;
    END
  END x[332]
  PIN x[333]
    DIRECTION INPUT ;
    USE SIGNAL ;
    PORT
      LAYER M4 ;
        RECT  0 113.712 0.084 113.736 ;
    END
  END x[333]
  PIN x[334]
    DIRECTION INPUT ;
    USE SIGNAL ;
    PORT
      LAYER M4 ;
        RECT  0 113.76 0.084 113.784 ;
    END
  END x[334]
  PIN x[335]
    DIRECTION INPUT ;
    USE SIGNAL ;
    PORT
      LAYER M4 ;
        RECT  0 113.808 0.084 113.832 ;
    END
  END x[335]
  PIN x[336]
    DIRECTION INPUT ;
    USE SIGNAL ;
    PORT
      LAYER M4 ;
        RECT  0 113.856 0.084 113.88 ;
    END
  END x[336]
  PIN x[337]
    DIRECTION INPUT ;
    USE SIGNAL ;
    PORT
      LAYER M4 ;
        RECT  0 113.904 0.084 113.928 ;
    END
  END x[337]
  PIN x[338]
    DIRECTION INPUT ;
    USE SIGNAL ;
    PORT
      LAYER M4 ;
        RECT  0 113.952 0.084 113.976 ;
    END
  END x[338]
  PIN x[339]
    DIRECTION INPUT ;
    USE SIGNAL ;
    PORT
      LAYER M4 ;
        RECT  0 114 0.084 114.024 ;
    END
  END x[339]
  PIN x[33]
    DIRECTION INPUT ;
    USE SIGNAL ;
    PORT
      LAYER M4 ;
        RECT  0 99.312 0.084 99.336 ;
    END
  END x[33]
  PIN x[340]
    DIRECTION INPUT ;
    USE SIGNAL ;
    PORT
      LAYER M4 ;
        RECT  0 114.048 0.084 114.072 ;
    END
  END x[340]
  PIN x[341]
    DIRECTION INPUT ;
    USE SIGNAL ;
    PORT
      LAYER M4 ;
        RECT  0 114.096 0.084 114.12 ;
    END
  END x[341]
  PIN x[342]
    DIRECTION INPUT ;
    USE SIGNAL ;
    PORT
      LAYER M4 ;
        RECT  0 114.144 0.084 114.168 ;
    END
  END x[342]
  PIN x[343]
    DIRECTION INPUT ;
    USE SIGNAL ;
    PORT
      LAYER M4 ;
        RECT  0 114.192 0.084 114.216 ;
    END
  END x[343]
  PIN x[344]
    DIRECTION INPUT ;
    USE SIGNAL ;
    PORT
      LAYER M4 ;
        RECT  0 114.24 0.084 114.264 ;
    END
  END x[344]
  PIN x[345]
    DIRECTION INPUT ;
    USE SIGNAL ;
    PORT
      LAYER M4 ;
        RECT  0 114.288 0.084 114.312 ;
    END
  END x[345]
  PIN x[346]
    DIRECTION INPUT ;
    USE SIGNAL ;
    PORT
      LAYER M4 ;
        RECT  0 114.336 0.084 114.36 ;
    END
  END x[346]
  PIN x[347]
    DIRECTION INPUT ;
    USE SIGNAL ;
    PORT
      LAYER M4 ;
        RECT  0 114.384 0.084 114.408 ;
    END
  END x[347]
  PIN x[348]
    DIRECTION INPUT ;
    USE SIGNAL ;
    PORT
      LAYER M4 ;
        RECT  0 114.432 0.084 114.456 ;
    END
  END x[348]
  PIN x[349]
    DIRECTION INPUT ;
    USE SIGNAL ;
    PORT
      LAYER M4 ;
        RECT  0 114.48 0.084 114.504 ;
    END
  END x[349]
  PIN x[34]
    DIRECTION INPUT ;
    USE SIGNAL ;
    PORT
      LAYER M4 ;
        RECT  0 99.36 0.084 99.384 ;
    END
  END x[34]
  PIN x[350]
    DIRECTION INPUT ;
    USE SIGNAL ;
    PORT
      LAYER M4 ;
        RECT  0 114.528 0.084 114.552 ;
    END
  END x[350]
  PIN x[351]
    DIRECTION INPUT ;
    USE SIGNAL ;
    PORT
      LAYER M4 ;
        RECT  0 114.576 0.084 114.6 ;
    END
  END x[351]
  PIN x[352]
    DIRECTION INPUT ;
    USE SIGNAL ;
    PORT
      LAYER M4 ;
        RECT  0 114.624 0.084 114.648 ;
    END
  END x[352]
  PIN x[353]
    DIRECTION INPUT ;
    USE SIGNAL ;
    PORT
      LAYER M4 ;
        RECT  0 114.672 0.084 114.696 ;
    END
  END x[353]
  PIN x[354]
    DIRECTION INPUT ;
    USE SIGNAL ;
    PORT
      LAYER M4 ;
        RECT  0 114.72 0.084 114.744 ;
    END
  END x[354]
  PIN x[355]
    DIRECTION INPUT ;
    USE SIGNAL ;
    PORT
      LAYER M4 ;
        RECT  0 114.768 0.084 114.792 ;
    END
  END x[355]
  PIN x[356]
    DIRECTION INPUT ;
    USE SIGNAL ;
    PORT
      LAYER M4 ;
        RECT  0 114.816 0.084 114.84 ;
    END
  END x[356]
  PIN x[357]
    DIRECTION INPUT ;
    USE SIGNAL ;
    PORT
      LAYER M4 ;
        RECT  0 114.864 0.084 114.888 ;
    END
  END x[357]
  PIN x[358]
    DIRECTION INPUT ;
    USE SIGNAL ;
    PORT
      LAYER M4 ;
        RECT  0 114.912 0.084 114.936 ;
    END
  END x[358]
  PIN x[359]
    DIRECTION INPUT ;
    USE SIGNAL ;
    PORT
      LAYER M4 ;
        RECT  0 114.96 0.084 114.984 ;
    END
  END x[359]
  PIN x[35]
    DIRECTION INPUT ;
    USE SIGNAL ;
    PORT
      LAYER M4 ;
        RECT  0 99.408 0.084 99.432 ;
    END
  END x[35]
  PIN x[360]
    DIRECTION INPUT ;
    USE SIGNAL ;
    PORT
      LAYER M4 ;
        RECT  0 115.008 0.084 115.032 ;
    END
  END x[360]
  PIN x[361]
    DIRECTION INPUT ;
    USE SIGNAL ;
    PORT
      LAYER M4 ;
        RECT  0 115.056 0.084 115.08 ;
    END
  END x[361]
  PIN x[362]
    DIRECTION INPUT ;
    USE SIGNAL ;
    PORT
      LAYER M4 ;
        RECT  0 115.104 0.084 115.128 ;
    END
  END x[362]
  PIN x[363]
    DIRECTION INPUT ;
    USE SIGNAL ;
    PORT
      LAYER M4 ;
        RECT  0 115.152 0.084 115.176 ;
    END
  END x[363]
  PIN x[364]
    DIRECTION INPUT ;
    USE SIGNAL ;
    PORT
      LAYER M4 ;
        RECT  0 115.2 0.084 115.224 ;
    END
  END x[364]
  PIN x[365]
    DIRECTION INPUT ;
    USE SIGNAL ;
    PORT
      LAYER M4 ;
        RECT  0 115.248 0.084 115.272 ;
    END
  END x[365]
  PIN x[366]
    DIRECTION INPUT ;
    USE SIGNAL ;
    PORT
      LAYER M4 ;
        RECT  0 115.296 0.084 115.32 ;
    END
  END x[366]
  PIN x[367]
    DIRECTION INPUT ;
    USE SIGNAL ;
    PORT
      LAYER M4 ;
        RECT  0 115.344 0.084 115.368 ;
    END
  END x[367]
  PIN x[368]
    DIRECTION INPUT ;
    USE SIGNAL ;
    PORT
      LAYER M4 ;
        RECT  0 115.392 0.084 115.416 ;
    END
  END x[368]
  PIN x[369]
    DIRECTION INPUT ;
    USE SIGNAL ;
    PORT
      LAYER M4 ;
        RECT  0 115.44 0.084 115.464 ;
    END
  END x[369]
  PIN x[36]
    DIRECTION INPUT ;
    USE SIGNAL ;
    PORT
      LAYER M4 ;
        RECT  0 99.456 0.084 99.48 ;
    END
  END x[36]
  PIN x[370]
    DIRECTION INPUT ;
    USE SIGNAL ;
    PORT
      LAYER M4 ;
        RECT  0 115.488 0.084 115.512 ;
    END
  END x[370]
  PIN x[371]
    DIRECTION INPUT ;
    USE SIGNAL ;
    PORT
      LAYER M4 ;
        RECT  0 115.536 0.084 115.56 ;
    END
  END x[371]
  PIN x[372]
    DIRECTION INPUT ;
    USE SIGNAL ;
    PORT
      LAYER M4 ;
        RECT  0 115.584 0.084 115.608 ;
    END
  END x[372]
  PIN x[373]
    DIRECTION INPUT ;
    USE SIGNAL ;
    PORT
      LAYER M4 ;
        RECT  0 115.632 0.084 115.656 ;
    END
  END x[373]
  PIN x[374]
    DIRECTION INPUT ;
    USE SIGNAL ;
    PORT
      LAYER M4 ;
        RECT  0 115.68 0.084 115.704 ;
    END
  END x[374]
  PIN x[375]
    DIRECTION INPUT ;
    USE SIGNAL ;
    PORT
      LAYER M4 ;
        RECT  0 115.728 0.084 115.752 ;
    END
  END x[375]
  PIN x[376]
    DIRECTION INPUT ;
    USE SIGNAL ;
    PORT
      LAYER M4 ;
        RECT  0 115.776 0.084 115.8 ;
    END
  END x[376]
  PIN x[377]
    DIRECTION INPUT ;
    USE SIGNAL ;
    PORT
      LAYER M4 ;
        RECT  0 115.824 0.084 115.848 ;
    END
  END x[377]
  PIN x[378]
    DIRECTION INPUT ;
    USE SIGNAL ;
    PORT
      LAYER M4 ;
        RECT  0 115.872 0.084 115.896 ;
    END
  END x[378]
  PIN x[379]
    DIRECTION INPUT ;
    USE SIGNAL ;
    PORT
      LAYER M4 ;
        RECT  0 115.92 0.084 115.944 ;
    END
  END x[379]
  PIN x[37]
    DIRECTION INPUT ;
    USE SIGNAL ;
    PORT
      LAYER M4 ;
        RECT  0 99.504 0.084 99.528 ;
    END
  END x[37]
  PIN x[380]
    DIRECTION INPUT ;
    USE SIGNAL ;
    PORT
      LAYER M4 ;
        RECT  0 115.968 0.084 115.992 ;
    END
  END x[380]
  PIN x[381]
    DIRECTION INPUT ;
    USE SIGNAL ;
    PORT
      LAYER M4 ;
        RECT  0 116.016 0.084 116.04 ;
    END
  END x[381]
  PIN x[382]
    DIRECTION INPUT ;
    USE SIGNAL ;
    PORT
      LAYER M4 ;
        RECT  0 116.064 0.084 116.088 ;
    END
  END x[382]
  PIN x[383]
    DIRECTION INPUT ;
    USE SIGNAL ;
    PORT
      LAYER M4 ;
        RECT  0 116.112 0.084 116.136 ;
    END
  END x[383]
  PIN x[384]
    DIRECTION INPUT ;
    USE SIGNAL ;
    PORT
      LAYER M4 ;
        RECT  0 116.16 0.084 116.184 ;
    END
  END x[384]
  PIN x[385]
    DIRECTION INPUT ;
    USE SIGNAL ;
    PORT
      LAYER M4 ;
        RECT  0 116.208 0.084 116.232 ;
    END
  END x[385]
  PIN x[386]
    DIRECTION INPUT ;
    USE SIGNAL ;
    PORT
      LAYER M4 ;
        RECT  0 116.256 0.084 116.28 ;
    END
  END x[386]
  PIN x[387]
    DIRECTION INPUT ;
    USE SIGNAL ;
    PORT
      LAYER M4 ;
        RECT  0 116.304 0.084 116.328 ;
    END
  END x[387]
  PIN x[388]
    DIRECTION INPUT ;
    USE SIGNAL ;
    PORT
      LAYER M4 ;
        RECT  0 116.352 0.084 116.376 ;
    END
  END x[388]
  PIN x[389]
    DIRECTION INPUT ;
    USE SIGNAL ;
    PORT
      LAYER M4 ;
        RECT  0 116.4 0.084 116.424 ;
    END
  END x[389]
  PIN x[38]
    DIRECTION INPUT ;
    USE SIGNAL ;
    PORT
      LAYER M4 ;
        RECT  0 99.552 0.084 99.576 ;
    END
  END x[38]
  PIN x[390]
    DIRECTION INPUT ;
    USE SIGNAL ;
    PORT
      LAYER M4 ;
        RECT  0 116.448 0.084 116.472 ;
    END
  END x[390]
  PIN x[391]
    DIRECTION INPUT ;
    USE SIGNAL ;
    PORT
      LAYER M4 ;
        RECT  0 116.496 0.084 116.52 ;
    END
  END x[391]
  PIN x[392]
    DIRECTION INPUT ;
    USE SIGNAL ;
    PORT
      LAYER M4 ;
        RECT  0 116.544 0.084 116.568 ;
    END
  END x[392]
  PIN x[393]
    DIRECTION INPUT ;
    USE SIGNAL ;
    PORT
      LAYER M4 ;
        RECT  0 116.592 0.084 116.616 ;
    END
  END x[393]
  PIN x[394]
    DIRECTION INPUT ;
    USE SIGNAL ;
    PORT
      LAYER M4 ;
        RECT  0 116.64 0.084 116.664 ;
    END
  END x[394]
  PIN x[395]
    DIRECTION INPUT ;
    USE SIGNAL ;
    PORT
      LAYER M4 ;
        RECT  0 116.688 0.084 116.712 ;
    END
  END x[395]
  PIN x[396]
    DIRECTION INPUT ;
    USE SIGNAL ;
    PORT
      LAYER M4 ;
        RECT  0 116.736 0.084 116.76 ;
    END
  END x[396]
  PIN x[397]
    DIRECTION INPUT ;
    USE SIGNAL ;
    PORT
      LAYER M4 ;
        RECT  0 116.784 0.084 116.808 ;
    END
  END x[397]
  PIN x[398]
    DIRECTION INPUT ;
    USE SIGNAL ;
    PORT
      LAYER M4 ;
        RECT  0 116.832 0.084 116.856 ;
    END
  END x[398]
  PIN x[399]
    DIRECTION INPUT ;
    USE SIGNAL ;
    PORT
      LAYER M4 ;
        RECT  0 116.88 0.084 116.904 ;
    END
  END x[399]
  PIN x[39]
    DIRECTION INPUT ;
    USE SIGNAL ;
    PORT
      LAYER M4 ;
        RECT  0 99.6 0.084 99.624 ;
    END
  END x[39]
  PIN x[3]
    DIRECTION INPUT ;
    USE SIGNAL ;
    PORT
      LAYER M4 ;
        RECT  0 97.872 0.084 97.896 ;
    END
  END x[3]
  PIN x[400]
    DIRECTION INPUT ;
    USE SIGNAL ;
    PORT
      LAYER M4 ;
        RECT  0 116.928 0.084 116.952 ;
    END
  END x[400]
  PIN x[401]
    DIRECTION INPUT ;
    USE SIGNAL ;
    PORT
      LAYER M4 ;
        RECT  0 116.976 0.084 117 ;
    END
  END x[401]
  PIN x[402]
    DIRECTION INPUT ;
    USE SIGNAL ;
    PORT
      LAYER M4 ;
        RECT  0 117.024 0.084 117.048 ;
    END
  END x[402]
  PIN x[403]
    DIRECTION INPUT ;
    USE SIGNAL ;
    PORT
      LAYER M4 ;
        RECT  0 117.072 0.084 117.096 ;
    END
  END x[403]
  PIN x[404]
    DIRECTION INPUT ;
    USE SIGNAL ;
    PORT
      LAYER M4 ;
        RECT  0 117.12 0.084 117.144 ;
    END
  END x[404]
  PIN x[405]
    DIRECTION INPUT ;
    USE SIGNAL ;
    PORT
      LAYER M4 ;
        RECT  0 117.168 0.084 117.192 ;
    END
  END x[405]
  PIN x[406]
    DIRECTION INPUT ;
    USE SIGNAL ;
    PORT
      LAYER M4 ;
        RECT  0 117.216 0.084 117.24 ;
    END
  END x[406]
  PIN x[407]
    DIRECTION INPUT ;
    USE SIGNAL ;
    PORT
      LAYER M4 ;
        RECT  0 117.264 0.084 117.288 ;
    END
  END x[407]
  PIN x[408]
    DIRECTION INPUT ;
    USE SIGNAL ;
    PORT
      LAYER M4 ;
        RECT  0 117.312 0.084 117.336 ;
    END
  END x[408]
  PIN x[409]
    DIRECTION INPUT ;
    USE SIGNAL ;
    PORT
      LAYER M4 ;
        RECT  0 117.36 0.084 117.384 ;
    END
  END x[409]
  PIN x[40]
    DIRECTION INPUT ;
    USE SIGNAL ;
    PORT
      LAYER M4 ;
        RECT  0 99.648 0.084 99.672 ;
    END
  END x[40]
  PIN x[410]
    DIRECTION INPUT ;
    USE SIGNAL ;
    PORT
      LAYER M4 ;
        RECT  0 117.408 0.084 117.432 ;
    END
  END x[410]
  PIN x[411]
    DIRECTION INPUT ;
    USE SIGNAL ;
    PORT
      LAYER M4 ;
        RECT  0 117.456 0.084 117.48 ;
    END
  END x[411]
  PIN x[412]
    DIRECTION INPUT ;
    USE SIGNAL ;
    PORT
      LAYER M4 ;
        RECT  0 117.504 0.084 117.528 ;
    END
  END x[412]
  PIN x[413]
    DIRECTION INPUT ;
    USE SIGNAL ;
    PORT
      LAYER M4 ;
        RECT  0 117.552 0.084 117.576 ;
    END
  END x[413]
  PIN x[414]
    DIRECTION INPUT ;
    USE SIGNAL ;
    PORT
      LAYER M4 ;
        RECT  0 117.6 0.084 117.624 ;
    END
  END x[414]
  PIN x[415]
    DIRECTION INPUT ;
    USE SIGNAL ;
    PORT
      LAYER M4 ;
        RECT  0 117.648 0.084 117.672 ;
    END
  END x[415]
  PIN x[416]
    DIRECTION INPUT ;
    USE SIGNAL ;
    PORT
      LAYER M4 ;
        RECT  0 117.696 0.084 117.72 ;
    END
  END x[416]
  PIN x[417]
    DIRECTION INPUT ;
    USE SIGNAL ;
    PORT
      LAYER M4 ;
        RECT  0 117.744 0.084 117.768 ;
    END
  END x[417]
  PIN x[418]
    DIRECTION INPUT ;
    USE SIGNAL ;
    PORT
      LAYER M4 ;
        RECT  0 117.792 0.084 117.816 ;
    END
  END x[418]
  PIN x[419]
    DIRECTION INPUT ;
    USE SIGNAL ;
    PORT
      LAYER M4 ;
        RECT  0 117.84 0.084 117.864 ;
    END
  END x[419]
  PIN x[41]
    DIRECTION INPUT ;
    USE SIGNAL ;
    PORT
      LAYER M4 ;
        RECT  0 99.696 0.084 99.72 ;
    END
  END x[41]
  PIN x[420]
    DIRECTION INPUT ;
    USE SIGNAL ;
    PORT
      LAYER M4 ;
        RECT  0 117.888 0.084 117.912 ;
    END
  END x[420]
  PIN x[421]
    DIRECTION INPUT ;
    USE SIGNAL ;
    PORT
      LAYER M4 ;
        RECT  0 117.936 0.084 117.96 ;
    END
  END x[421]
  PIN x[422]
    DIRECTION INPUT ;
    USE SIGNAL ;
    PORT
      LAYER M4 ;
        RECT  0 117.984 0.084 118.008 ;
    END
  END x[422]
  PIN x[423]
    DIRECTION INPUT ;
    USE SIGNAL ;
    PORT
      LAYER M4 ;
        RECT  0 118.032 0.084 118.056 ;
    END
  END x[423]
  PIN x[424]
    DIRECTION INPUT ;
    USE SIGNAL ;
    PORT
      LAYER M4 ;
        RECT  0 118.08 0.084 118.104 ;
    END
  END x[424]
  PIN x[425]
    DIRECTION INPUT ;
    USE SIGNAL ;
    PORT
      LAYER M4 ;
        RECT  0 118.128 0.084 118.152 ;
    END
  END x[425]
  PIN x[426]
    DIRECTION INPUT ;
    USE SIGNAL ;
    PORT
      LAYER M4 ;
        RECT  0 118.176 0.084 118.2 ;
    END
  END x[426]
  PIN x[427]
    DIRECTION INPUT ;
    USE SIGNAL ;
    PORT
      LAYER M4 ;
        RECT  0 118.224 0.084 118.248 ;
    END
  END x[427]
  PIN x[428]
    DIRECTION INPUT ;
    USE SIGNAL ;
    PORT
      LAYER M4 ;
        RECT  0 118.272 0.084 118.296 ;
    END
  END x[428]
  PIN x[429]
    DIRECTION INPUT ;
    USE SIGNAL ;
    PORT
      LAYER M4 ;
        RECT  0 118.32 0.084 118.344 ;
    END
  END x[429]
  PIN x[42]
    DIRECTION INPUT ;
    USE SIGNAL ;
    PORT
      LAYER M4 ;
        RECT  0 99.744 0.084 99.768 ;
    END
  END x[42]
  PIN x[430]
    DIRECTION INPUT ;
    USE SIGNAL ;
    PORT
      LAYER M4 ;
        RECT  0 118.368 0.084 118.392 ;
    END
  END x[430]
  PIN x[431]
    DIRECTION INPUT ;
    USE SIGNAL ;
    PORT
      LAYER M4 ;
        RECT  0 118.416 0.084 118.44 ;
    END
  END x[431]
  PIN x[432]
    DIRECTION INPUT ;
    USE SIGNAL ;
    PORT
      LAYER M4 ;
        RECT  0 118.464 0.084 118.488 ;
    END
  END x[432]
  PIN x[433]
    DIRECTION INPUT ;
    USE SIGNAL ;
    PORT
      LAYER M4 ;
        RECT  0 118.512 0.084 118.536 ;
    END
  END x[433]
  PIN x[434]
    DIRECTION INPUT ;
    USE SIGNAL ;
    PORT
      LAYER M4 ;
        RECT  0 118.56 0.084 118.584 ;
    END
  END x[434]
  PIN x[435]
    DIRECTION INPUT ;
    USE SIGNAL ;
    PORT
      LAYER M4 ;
        RECT  0 118.608 0.084 118.632 ;
    END
  END x[435]
  PIN x[436]
    DIRECTION INPUT ;
    USE SIGNAL ;
    PORT
      LAYER M4 ;
        RECT  0 118.656 0.084 118.68 ;
    END
  END x[436]
  PIN x[437]
    DIRECTION INPUT ;
    USE SIGNAL ;
    PORT
      LAYER M4 ;
        RECT  0 118.704 0.084 118.728 ;
    END
  END x[437]
  PIN x[438]
    DIRECTION INPUT ;
    USE SIGNAL ;
    PORT
      LAYER M4 ;
        RECT  0 118.752 0.084 118.776 ;
    END
  END x[438]
  PIN x[439]
    DIRECTION INPUT ;
    USE SIGNAL ;
    PORT
      LAYER M4 ;
        RECT  0 118.8 0.084 118.824 ;
    END
  END x[439]
  PIN x[43]
    DIRECTION INPUT ;
    USE SIGNAL ;
    PORT
      LAYER M4 ;
        RECT  0 99.792 0.084 99.816 ;
    END
  END x[43]
  PIN x[440]
    DIRECTION INPUT ;
    USE SIGNAL ;
    PORT
      LAYER M4 ;
        RECT  0 118.848 0.084 118.872 ;
    END
  END x[440]
  PIN x[441]
    DIRECTION INPUT ;
    USE SIGNAL ;
    PORT
      LAYER M4 ;
        RECT  0 118.896 0.084 118.92 ;
    END
  END x[441]
  PIN x[442]
    DIRECTION INPUT ;
    USE SIGNAL ;
    PORT
      LAYER M4 ;
        RECT  0 118.944 0.084 118.968 ;
    END
  END x[442]
  PIN x[443]
    DIRECTION INPUT ;
    USE SIGNAL ;
    PORT
      LAYER M4 ;
        RECT  0 118.992 0.084 119.016 ;
    END
  END x[443]
  PIN x[444]
    DIRECTION INPUT ;
    USE SIGNAL ;
    PORT
      LAYER M4 ;
        RECT  0 119.04 0.084 119.064 ;
    END
  END x[444]
  PIN x[445]
    DIRECTION INPUT ;
    USE SIGNAL ;
    PORT
      LAYER M4 ;
        RECT  0 119.088 0.084 119.112 ;
    END
  END x[445]
  PIN x[446]
    DIRECTION INPUT ;
    USE SIGNAL ;
    PORT
      LAYER M4 ;
        RECT  0 119.136 0.084 119.16 ;
    END
  END x[446]
  PIN x[447]
    DIRECTION INPUT ;
    USE SIGNAL ;
    PORT
      LAYER M4 ;
        RECT  0 119.184 0.084 119.208 ;
    END
  END x[447]
  PIN x[448]
    DIRECTION INPUT ;
    USE SIGNAL ;
    PORT
      LAYER M4 ;
        RECT  0 119.232 0.084 119.256 ;
    END
  END x[448]
  PIN x[449]
    DIRECTION INPUT ;
    USE SIGNAL ;
    PORT
      LAYER M4 ;
        RECT  0 119.28 0.084 119.304 ;
    END
  END x[449]
  PIN x[44]
    DIRECTION INPUT ;
    USE SIGNAL ;
    PORT
      LAYER M4 ;
        RECT  0 99.84 0.084 99.864 ;
    END
  END x[44]
  PIN x[450]
    DIRECTION INPUT ;
    USE SIGNAL ;
    PORT
      LAYER M4 ;
        RECT  0 119.328 0.084 119.352 ;
    END
  END x[450]
  PIN x[451]
    DIRECTION INPUT ;
    USE SIGNAL ;
    PORT
      LAYER M4 ;
        RECT  0 119.376 0.084 119.4 ;
    END
  END x[451]
  PIN x[452]
    DIRECTION INPUT ;
    USE SIGNAL ;
    PORT
      LAYER M4 ;
        RECT  0 119.424 0.084 119.448 ;
    END
  END x[452]
  PIN x[453]
    DIRECTION INPUT ;
    USE SIGNAL ;
    PORT
      LAYER M4 ;
        RECT  0 119.472 0.084 119.496 ;
    END
  END x[453]
  PIN x[454]
    DIRECTION INPUT ;
    USE SIGNAL ;
    PORT
      LAYER M4 ;
        RECT  0 119.52 0.084 119.544 ;
    END
  END x[454]
  PIN x[455]
    DIRECTION INPUT ;
    USE SIGNAL ;
    PORT
      LAYER M4 ;
        RECT  0 119.568 0.084 119.592 ;
    END
  END x[455]
  PIN x[456]
    DIRECTION INPUT ;
    USE SIGNAL ;
    PORT
      LAYER M4 ;
        RECT  0 119.616 0.084 119.64 ;
    END
  END x[456]
  PIN x[457]
    DIRECTION INPUT ;
    USE SIGNAL ;
    PORT
      LAYER M4 ;
        RECT  0 119.664 0.084 119.688 ;
    END
  END x[457]
  PIN x[458]
    DIRECTION INPUT ;
    USE SIGNAL ;
    PORT
      LAYER M4 ;
        RECT  0 119.712 0.084 119.736 ;
    END
  END x[458]
  PIN x[459]
    DIRECTION INPUT ;
    USE SIGNAL ;
    PORT
      LAYER M4 ;
        RECT  0 119.76 0.084 119.784 ;
    END
  END x[459]
  PIN x[45]
    DIRECTION INPUT ;
    USE SIGNAL ;
    PORT
      LAYER M4 ;
        RECT  0 99.888 0.084 99.912 ;
    END
  END x[45]
  PIN x[460]
    DIRECTION INPUT ;
    USE SIGNAL ;
    PORT
      LAYER M4 ;
        RECT  0 119.808 0.084 119.832 ;
    END
  END x[460]
  PIN x[461]
    DIRECTION INPUT ;
    USE SIGNAL ;
    PORT
      LAYER M4 ;
        RECT  0 119.856 0.084 119.88 ;
    END
  END x[461]
  PIN x[462]
    DIRECTION INPUT ;
    USE SIGNAL ;
    PORT
      LAYER M4 ;
        RECT  0 119.904 0.084 119.928 ;
    END
  END x[462]
  PIN x[463]
    DIRECTION INPUT ;
    USE SIGNAL ;
    PORT
      LAYER M4 ;
        RECT  0 119.952 0.084 119.976 ;
    END
  END x[463]
  PIN x[464]
    DIRECTION INPUT ;
    USE SIGNAL ;
    PORT
      LAYER M4 ;
        RECT  0 120 0.084 120.024 ;
    END
  END x[464]
  PIN x[465]
    DIRECTION INPUT ;
    USE SIGNAL ;
    PORT
      LAYER M4 ;
        RECT  0 120.048 0.084 120.072 ;
    END
  END x[465]
  PIN x[466]
    DIRECTION INPUT ;
    USE SIGNAL ;
    PORT
      LAYER M4 ;
        RECT  0 120.096 0.084 120.12 ;
    END
  END x[466]
  PIN x[467]
    DIRECTION INPUT ;
    USE SIGNAL ;
    PORT
      LAYER M4 ;
        RECT  0 120.144 0.084 120.168 ;
    END
  END x[467]
  PIN x[468]
    DIRECTION INPUT ;
    USE SIGNAL ;
    PORT
      LAYER M4 ;
        RECT  0 120.192 0.084 120.216 ;
    END
  END x[468]
  PIN x[469]
    DIRECTION INPUT ;
    USE SIGNAL ;
    PORT
      LAYER M4 ;
        RECT  0 120.24 0.084 120.264 ;
    END
  END x[469]
  PIN x[46]
    DIRECTION INPUT ;
    USE SIGNAL ;
    PORT
      LAYER M4 ;
        RECT  0 99.936 0.084 99.96 ;
    END
  END x[46]
  PIN x[470]
    DIRECTION INPUT ;
    USE SIGNAL ;
    PORT
      LAYER M4 ;
        RECT  0 120.288 0.084 120.312 ;
    END
  END x[470]
  PIN x[471]
    DIRECTION INPUT ;
    USE SIGNAL ;
    PORT
      LAYER M4 ;
        RECT  0 120.336 0.084 120.36 ;
    END
  END x[471]
  PIN x[472]
    DIRECTION INPUT ;
    USE SIGNAL ;
    PORT
      LAYER M4 ;
        RECT  0 120.384 0.084 120.408 ;
    END
  END x[472]
  PIN x[473]
    DIRECTION INPUT ;
    USE SIGNAL ;
    PORT
      LAYER M4 ;
        RECT  0 120.432 0.084 120.456 ;
    END
  END x[473]
  PIN x[474]
    DIRECTION INPUT ;
    USE SIGNAL ;
    PORT
      LAYER M4 ;
        RECT  0 120.48 0.084 120.504 ;
    END
  END x[474]
  PIN x[475]
    DIRECTION INPUT ;
    USE SIGNAL ;
    PORT
      LAYER M4 ;
        RECT  0 120.528 0.084 120.552 ;
    END
  END x[475]
  PIN x[476]
    DIRECTION INPUT ;
    USE SIGNAL ;
    PORT
      LAYER M4 ;
        RECT  0 120.576 0.084 120.6 ;
    END
  END x[476]
  PIN x[477]
    DIRECTION INPUT ;
    USE SIGNAL ;
    PORT
      LAYER M4 ;
        RECT  0 120.624 0.084 120.648 ;
    END
  END x[477]
  PIN x[478]
    DIRECTION INPUT ;
    USE SIGNAL ;
    PORT
      LAYER M4 ;
        RECT  0 120.672 0.084 120.696 ;
    END
  END x[478]
  PIN x[479]
    DIRECTION INPUT ;
    USE SIGNAL ;
    PORT
      LAYER M4 ;
        RECT  0 120.72 0.084 120.744 ;
    END
  END x[479]
  PIN x[47]
    DIRECTION INPUT ;
    USE SIGNAL ;
    PORT
      LAYER M4 ;
        RECT  0 99.984 0.084 100.008 ;
    END
  END x[47]
  PIN x[480]
    DIRECTION INPUT ;
    USE SIGNAL ;
    PORT
      LAYER M4 ;
        RECT  0 120.768 0.084 120.792 ;
    END
  END x[480]
  PIN x[481]
    DIRECTION INPUT ;
    USE SIGNAL ;
    PORT
      LAYER M4 ;
        RECT  0 120.816 0.084 120.84 ;
    END
  END x[481]
  PIN x[482]
    DIRECTION INPUT ;
    USE SIGNAL ;
    PORT
      LAYER M4 ;
        RECT  0 120.864 0.084 120.888 ;
    END
  END x[482]
  PIN x[483]
    DIRECTION INPUT ;
    USE SIGNAL ;
    PORT
      LAYER M4 ;
        RECT  0 120.912 0.084 120.936 ;
    END
  END x[483]
  PIN x[484]
    DIRECTION INPUT ;
    USE SIGNAL ;
    PORT
      LAYER M4 ;
        RECT  0 120.96 0.084 120.984 ;
    END
  END x[484]
  PIN x[485]
    DIRECTION INPUT ;
    USE SIGNAL ;
    PORT
      LAYER M4 ;
        RECT  0 121.008 0.084 121.032 ;
    END
  END x[485]
  PIN x[486]
    DIRECTION INPUT ;
    USE SIGNAL ;
    PORT
      LAYER M4 ;
        RECT  0 121.056 0.084 121.08 ;
    END
  END x[486]
  PIN x[487]
    DIRECTION INPUT ;
    USE SIGNAL ;
    PORT
      LAYER M4 ;
        RECT  0 121.104 0.084 121.128 ;
    END
  END x[487]
  PIN x[488]
    DIRECTION INPUT ;
    USE SIGNAL ;
    PORT
      LAYER M4 ;
        RECT  0 121.152 0.084 121.176 ;
    END
  END x[488]
  PIN x[489]
    DIRECTION INPUT ;
    USE SIGNAL ;
    PORT
      LAYER M4 ;
        RECT  0 121.2 0.084 121.224 ;
    END
  END x[489]
  PIN x[48]
    DIRECTION INPUT ;
    USE SIGNAL ;
    PORT
      LAYER M4 ;
        RECT  0 100.032 0.084 100.056 ;
    END
  END x[48]
  PIN x[490]
    DIRECTION INPUT ;
    USE SIGNAL ;
    PORT
      LAYER M4 ;
        RECT  0 121.248 0.084 121.272 ;
    END
  END x[490]
  PIN x[491]
    DIRECTION INPUT ;
    USE SIGNAL ;
    PORT
      LAYER M4 ;
        RECT  0 121.296 0.084 121.32 ;
    END
  END x[491]
  PIN x[492]
    DIRECTION INPUT ;
    USE SIGNAL ;
    PORT
      LAYER M4 ;
        RECT  0 121.344 0.084 121.368 ;
    END
  END x[492]
  PIN x[493]
    DIRECTION INPUT ;
    USE SIGNAL ;
    PORT
      LAYER M4 ;
        RECT  0 121.392 0.084 121.416 ;
    END
  END x[493]
  PIN x[494]
    DIRECTION INPUT ;
    USE SIGNAL ;
    PORT
      LAYER M4 ;
        RECT  0 121.44 0.084 121.464 ;
    END
  END x[494]
  PIN x[495]
    DIRECTION INPUT ;
    USE SIGNAL ;
    PORT
      LAYER M4 ;
        RECT  0 121.488 0.084 121.512 ;
    END
  END x[495]
  PIN x[496]
    DIRECTION INPUT ;
    USE SIGNAL ;
    PORT
      LAYER M4 ;
        RECT  0 121.536 0.084 121.56 ;
    END
  END x[496]
  PIN x[497]
    DIRECTION INPUT ;
    USE SIGNAL ;
    PORT
      LAYER M4 ;
        RECT  0 121.584 0.084 121.608 ;
    END
  END x[497]
  PIN x[498]
    DIRECTION INPUT ;
    USE SIGNAL ;
    PORT
      LAYER M4 ;
        RECT  0 121.632 0.084 121.656 ;
    END
  END x[498]
  PIN x[499]
    DIRECTION INPUT ;
    USE SIGNAL ;
    PORT
      LAYER M4 ;
        RECT  0 121.68 0.084 121.704 ;
    END
  END x[499]
  PIN x[49]
    DIRECTION INPUT ;
    USE SIGNAL ;
    PORT
      LAYER M4 ;
        RECT  0 100.08 0.084 100.104 ;
    END
  END x[49]
  PIN x[4]
    DIRECTION INPUT ;
    USE SIGNAL ;
    PORT
      LAYER M4 ;
        RECT  0 97.92 0.084 97.944 ;
    END
  END x[4]
  PIN x[500]
    DIRECTION INPUT ;
    USE SIGNAL ;
    PORT
      LAYER M4 ;
        RECT  0 121.728 0.084 121.752 ;
    END
  END x[500]
  PIN x[501]
    DIRECTION INPUT ;
    USE SIGNAL ;
    PORT
      LAYER M4 ;
        RECT  0 121.776 0.084 121.8 ;
    END
  END x[501]
  PIN x[502]
    DIRECTION INPUT ;
    USE SIGNAL ;
    PORT
      LAYER M4 ;
        RECT  0 121.824 0.084 121.848 ;
    END
  END x[502]
  PIN x[503]
    DIRECTION INPUT ;
    USE SIGNAL ;
    PORT
      LAYER M4 ;
        RECT  0 121.872 0.084 121.896 ;
    END
  END x[503]
  PIN x[504]
    DIRECTION INPUT ;
    USE SIGNAL ;
    PORT
      LAYER M4 ;
        RECT  0 121.92 0.084 121.944 ;
    END
  END x[504]
  PIN x[505]
    DIRECTION INPUT ;
    USE SIGNAL ;
    PORT
      LAYER M4 ;
        RECT  0 121.968 0.084 121.992 ;
    END
  END x[505]
  PIN x[506]
    DIRECTION INPUT ;
    USE SIGNAL ;
    PORT
      LAYER M4 ;
        RECT  0 122.016 0.084 122.04 ;
    END
  END x[506]
  PIN x[507]
    DIRECTION INPUT ;
    USE SIGNAL ;
    PORT
      LAYER M4 ;
        RECT  0 122.064 0.084 122.088 ;
    END
  END x[507]
  PIN x[508]
    DIRECTION INPUT ;
    USE SIGNAL ;
    PORT
      LAYER M4 ;
        RECT  0 122.112 0.084 122.136 ;
    END
  END x[508]
  PIN x[509]
    DIRECTION INPUT ;
    USE SIGNAL ;
    PORT
      LAYER M4 ;
        RECT  0 122.16 0.084 122.184 ;
    END
  END x[509]
  PIN x[50]
    DIRECTION INPUT ;
    USE SIGNAL ;
    PORT
      LAYER M4 ;
        RECT  0 100.128 0.084 100.152 ;
    END
  END x[50]
  PIN x[510]
    DIRECTION INPUT ;
    USE SIGNAL ;
    PORT
      LAYER M4 ;
        RECT  0 122.208 0.084 122.232 ;
    END
  END x[510]
  PIN x[511]
    DIRECTION INPUT ;
    USE SIGNAL ;
    PORT
      LAYER M4 ;
        RECT  0 122.256 0.084 122.28 ;
    END
  END x[511]
  PIN x[51]
    DIRECTION INPUT ;
    USE SIGNAL ;
    PORT
      LAYER M4 ;
        RECT  0 100.176 0.084 100.2 ;
    END
  END x[51]
  PIN x[52]
    DIRECTION INPUT ;
    USE SIGNAL ;
    PORT
      LAYER M4 ;
        RECT  0 100.224 0.084 100.248 ;
    END
  END x[52]
  PIN x[53]
    DIRECTION INPUT ;
    USE SIGNAL ;
    PORT
      LAYER M4 ;
        RECT  0 100.272 0.084 100.296 ;
    END
  END x[53]
  PIN x[54]
    DIRECTION INPUT ;
    USE SIGNAL ;
    PORT
      LAYER M4 ;
        RECT  0 100.32 0.084 100.344 ;
    END
  END x[54]
  PIN x[55]
    DIRECTION INPUT ;
    USE SIGNAL ;
    PORT
      LAYER M4 ;
        RECT  0 100.368 0.084 100.392 ;
    END
  END x[55]
  PIN x[56]
    DIRECTION INPUT ;
    USE SIGNAL ;
    PORT
      LAYER M4 ;
        RECT  0 100.416 0.084 100.44 ;
    END
  END x[56]
  PIN x[57]
    DIRECTION INPUT ;
    USE SIGNAL ;
    PORT
      LAYER M4 ;
        RECT  0 100.464 0.084 100.488 ;
    END
  END x[57]
  PIN x[58]
    DIRECTION INPUT ;
    USE SIGNAL ;
    PORT
      LAYER M4 ;
        RECT  0 100.512 0.084 100.536 ;
    END
  END x[58]
  PIN x[59]
    DIRECTION INPUT ;
    USE SIGNAL ;
    PORT
      LAYER M4 ;
        RECT  0 100.56 0.084 100.584 ;
    END
  END x[59]
  PIN x[5]
    DIRECTION INPUT ;
    USE SIGNAL ;
    PORT
      LAYER M4 ;
        RECT  0 97.968 0.084 97.992 ;
    END
  END x[5]
  PIN x[60]
    DIRECTION INPUT ;
    USE SIGNAL ;
    PORT
      LAYER M4 ;
        RECT  0 100.608 0.084 100.632 ;
    END
  END x[60]
  PIN x[61]
    DIRECTION INPUT ;
    USE SIGNAL ;
    PORT
      LAYER M4 ;
        RECT  0 100.656 0.084 100.68 ;
    END
  END x[61]
  PIN x[62]
    DIRECTION INPUT ;
    USE SIGNAL ;
    PORT
      LAYER M4 ;
        RECT  0 100.704 0.084 100.728 ;
    END
  END x[62]
  PIN x[63]
    DIRECTION INPUT ;
    USE SIGNAL ;
    PORT
      LAYER M4 ;
        RECT  0 100.752 0.084 100.776 ;
    END
  END x[63]
  PIN x[64]
    DIRECTION INPUT ;
    USE SIGNAL ;
    PORT
      LAYER M4 ;
        RECT  0 100.8 0.084 100.824 ;
    END
  END x[64]
  PIN x[65]
    DIRECTION INPUT ;
    USE SIGNAL ;
    PORT
      LAYER M4 ;
        RECT  0 100.848 0.084 100.872 ;
    END
  END x[65]
  PIN x[66]
    DIRECTION INPUT ;
    USE SIGNAL ;
    PORT
      LAYER M4 ;
        RECT  0 100.896 0.084 100.92 ;
    END
  END x[66]
  PIN x[67]
    DIRECTION INPUT ;
    USE SIGNAL ;
    PORT
      LAYER M4 ;
        RECT  0 100.944 0.084 100.968 ;
    END
  END x[67]
  PIN x[68]
    DIRECTION INPUT ;
    USE SIGNAL ;
    PORT
      LAYER M4 ;
        RECT  0 100.992 0.084 101.016 ;
    END
  END x[68]
  PIN x[69]
    DIRECTION INPUT ;
    USE SIGNAL ;
    PORT
      LAYER M4 ;
        RECT  0 101.04 0.084 101.064 ;
    END
  END x[69]
  PIN x[6]
    DIRECTION INPUT ;
    USE SIGNAL ;
    PORT
      LAYER M4 ;
        RECT  0 98.016 0.084 98.04 ;
    END
  END x[6]
  PIN x[70]
    DIRECTION INPUT ;
    USE SIGNAL ;
    PORT
      LAYER M4 ;
        RECT  0 101.088 0.084 101.112 ;
    END
  END x[70]
  PIN x[71]
    DIRECTION INPUT ;
    USE SIGNAL ;
    PORT
      LAYER M4 ;
        RECT  0 101.136 0.084 101.16 ;
    END
  END x[71]
  PIN x[72]
    DIRECTION INPUT ;
    USE SIGNAL ;
    PORT
      LAYER M4 ;
        RECT  0 101.184 0.084 101.208 ;
    END
  END x[72]
  PIN x[73]
    DIRECTION INPUT ;
    USE SIGNAL ;
    PORT
      LAYER M4 ;
        RECT  0 101.232 0.084 101.256 ;
    END
  END x[73]
  PIN x[74]
    DIRECTION INPUT ;
    USE SIGNAL ;
    PORT
      LAYER M4 ;
        RECT  0 101.28 0.084 101.304 ;
    END
  END x[74]
  PIN x[75]
    DIRECTION INPUT ;
    USE SIGNAL ;
    PORT
      LAYER M4 ;
        RECT  0 101.328 0.084 101.352 ;
    END
  END x[75]
  PIN x[76]
    DIRECTION INPUT ;
    USE SIGNAL ;
    PORT
      LAYER M4 ;
        RECT  0 101.376 0.084 101.4 ;
    END
  END x[76]
  PIN x[77]
    DIRECTION INPUT ;
    USE SIGNAL ;
    PORT
      LAYER M4 ;
        RECT  0 101.424 0.084 101.448 ;
    END
  END x[77]
  PIN x[78]
    DIRECTION INPUT ;
    USE SIGNAL ;
    PORT
      LAYER M4 ;
        RECT  0 101.472 0.084 101.496 ;
    END
  END x[78]
  PIN x[79]
    DIRECTION INPUT ;
    USE SIGNAL ;
    PORT
      LAYER M4 ;
        RECT  0 101.52 0.084 101.544 ;
    END
  END x[79]
  PIN x[7]
    DIRECTION INPUT ;
    USE SIGNAL ;
    PORT
      LAYER M4 ;
        RECT  0 98.064 0.084 98.088 ;
    END
  END x[7]
  PIN x[80]
    DIRECTION INPUT ;
    USE SIGNAL ;
    PORT
      LAYER M4 ;
        RECT  0 101.568 0.084 101.592 ;
    END
  END x[80]
  PIN x[81]
    DIRECTION INPUT ;
    USE SIGNAL ;
    PORT
      LAYER M4 ;
        RECT  0 101.616 0.084 101.64 ;
    END
  END x[81]
  PIN x[82]
    DIRECTION INPUT ;
    USE SIGNAL ;
    PORT
      LAYER M4 ;
        RECT  0 101.664 0.084 101.688 ;
    END
  END x[82]
  PIN x[83]
    DIRECTION INPUT ;
    USE SIGNAL ;
    PORT
      LAYER M4 ;
        RECT  0 101.712 0.084 101.736 ;
    END
  END x[83]
  PIN x[84]
    DIRECTION INPUT ;
    USE SIGNAL ;
    PORT
      LAYER M4 ;
        RECT  0 101.76 0.084 101.784 ;
    END
  END x[84]
  PIN x[85]
    DIRECTION INPUT ;
    USE SIGNAL ;
    PORT
      LAYER M4 ;
        RECT  0 101.808 0.084 101.832 ;
    END
  END x[85]
  PIN x[86]
    DIRECTION INPUT ;
    USE SIGNAL ;
    PORT
      LAYER M4 ;
        RECT  0 101.856 0.084 101.88 ;
    END
  END x[86]
  PIN x[87]
    DIRECTION INPUT ;
    USE SIGNAL ;
    PORT
      LAYER M4 ;
        RECT  0 101.904 0.084 101.928 ;
    END
  END x[87]
  PIN x[88]
    DIRECTION INPUT ;
    USE SIGNAL ;
    PORT
      LAYER M4 ;
        RECT  0 101.952 0.084 101.976 ;
    END
  END x[88]
  PIN x[89]
    DIRECTION INPUT ;
    USE SIGNAL ;
    PORT
      LAYER M4 ;
        RECT  0 102 0.084 102.024 ;
    END
  END x[89]
  PIN x[8]
    DIRECTION INPUT ;
    USE SIGNAL ;
    PORT
      LAYER M4 ;
        RECT  0 98.112 0.084 98.136 ;
    END
  END x[8]
  PIN x[90]
    DIRECTION INPUT ;
    USE SIGNAL ;
    PORT
      LAYER M4 ;
        RECT  0 102.048 0.084 102.072 ;
    END
  END x[90]
  PIN x[91]
    DIRECTION INPUT ;
    USE SIGNAL ;
    PORT
      LAYER M4 ;
        RECT  0 102.096 0.084 102.12 ;
    END
  END x[91]
  PIN x[92]
    DIRECTION INPUT ;
    USE SIGNAL ;
    PORT
      LAYER M4 ;
        RECT  0 102.144 0.084 102.168 ;
    END
  END x[92]
  PIN x[93]
    DIRECTION INPUT ;
    USE SIGNAL ;
    PORT
      LAYER M4 ;
        RECT  0 102.192 0.084 102.216 ;
    END
  END x[93]
  PIN x[94]
    DIRECTION INPUT ;
    USE SIGNAL ;
    PORT
      LAYER M4 ;
        RECT  0 102.24 0.084 102.264 ;
    END
  END x[94]
  PIN x[95]
    DIRECTION INPUT ;
    USE SIGNAL ;
    PORT
      LAYER M4 ;
        RECT  0 102.288 0.084 102.312 ;
    END
  END x[95]
  PIN x[96]
    DIRECTION INPUT ;
    USE SIGNAL ;
    PORT
      LAYER M4 ;
        RECT  0 102.336 0.084 102.36 ;
    END
  END x[96]
  PIN x[97]
    DIRECTION INPUT ;
    USE SIGNAL ;
    PORT
      LAYER M4 ;
        RECT  0 102.384 0.084 102.408 ;
    END
  END x[97]
  PIN x[98]
    DIRECTION INPUT ;
    USE SIGNAL ;
    PORT
      LAYER M4 ;
        RECT  0 102.432 0.084 102.456 ;
    END
  END x[98]
  PIN x[99]
    DIRECTION INPUT ;
    USE SIGNAL ;
    PORT
      LAYER M4 ;
        RECT  0 102.48 0.084 102.504 ;
    END
  END x[99]
  PIN x[9]
    DIRECTION INPUT ;
    USE SIGNAL ;
    PORT
      LAYER M4 ;
        RECT  0 98.16 0.084 98.184 ;
    END
  END x[9]
  PIN y[0]
    DIRECTION OUTPUT ;
    USE SIGNAL ;
    PORT
      LAYER M4 ;
        RECT  219.916 123.984 220 124.008 ;
    END
  END y[0]
  PIN y[10]
    DIRECTION OUTPUT ;
    USE SIGNAL ;
    PORT
      LAYER M4 ;
        RECT  219.916 124.464 220 124.488 ;
    END
  END y[10]
  PIN y[11]
    DIRECTION OUTPUT ;
    USE SIGNAL ;
    PORT
      LAYER M4 ;
        RECT  219.916 124.512 220 124.536 ;
    END
  END y[11]
  PIN y[12]
    DIRECTION OUTPUT ;
    USE SIGNAL ;
    PORT
      LAYER M4 ;
        RECT  219.916 124.56 220 124.584 ;
    END
  END y[12]
  PIN y[13]
    DIRECTION OUTPUT ;
    USE SIGNAL ;
    PORT
      LAYER M4 ;
        RECT  219.916 124.608 220 124.632 ;
    END
  END y[13]
  PIN y[14]
    DIRECTION OUTPUT ;
    USE SIGNAL ;
    PORT
      LAYER M4 ;
        RECT  219.916 124.656 220 124.68 ;
    END
  END y[14]
  PIN y[15]
    DIRECTION OUTPUT ;
    USE SIGNAL ;
    PORT
      LAYER M4 ;
        RECT  219.916 124.704 220 124.728 ;
    END
  END y[15]
  PIN y[16]
    DIRECTION OUTPUT ;
    USE SIGNAL ;
    PORT
      LAYER M4 ;
        RECT  219.916 124.752 220 124.776 ;
    END
  END y[16]
  PIN y[17]
    DIRECTION OUTPUT ;
    USE SIGNAL ;
    PORT
      LAYER M4 ;
        RECT  219.916 124.8 220 124.824 ;
    END
  END y[17]
  PIN y[18]
    DIRECTION OUTPUT ;
    USE SIGNAL ;
    PORT
      LAYER M4 ;
        RECT  219.916 124.848 220 124.872 ;
    END
  END y[18]
  PIN y[19]
    DIRECTION OUTPUT ;
    USE SIGNAL ;
    PORT
      LAYER M4 ;
        RECT  219.916 124.896 220 124.92 ;
    END
  END y[19]
  PIN y[1]
    DIRECTION OUTPUT ;
    USE SIGNAL ;
    PORT
      LAYER M4 ;
        RECT  219.916 124.032 220 124.056 ;
    END
  END y[1]
  PIN y[20]
    DIRECTION OUTPUT ;
    USE SIGNAL ;
    PORT
      LAYER M4 ;
        RECT  219.916 124.944 220 124.968 ;
    END
  END y[20]
  PIN y[21]
    DIRECTION OUTPUT ;
    USE SIGNAL ;
    PORT
      LAYER M4 ;
        RECT  219.916 124.992 220 125.016 ;
    END
  END y[21]
  PIN y[22]
    DIRECTION OUTPUT ;
    USE SIGNAL ;
    PORT
      LAYER M4 ;
        RECT  219.916 125.04 220 125.064 ;
    END
  END y[22]
  PIN y[23]
    DIRECTION OUTPUT ;
    USE SIGNAL ;
    PORT
      LAYER M4 ;
        RECT  219.916 125.088 220 125.112 ;
    END
  END y[23]
  PIN y[24]
    DIRECTION OUTPUT ;
    USE SIGNAL ;
    PORT
      LAYER M4 ;
        RECT  219.916 125.136 220 125.16 ;
    END
  END y[24]
  PIN y[25]
    DIRECTION OUTPUT ;
    USE SIGNAL ;
    PORT
      LAYER M4 ;
        RECT  219.916 125.184 220 125.208 ;
    END
  END y[25]
  PIN y[26]
    DIRECTION OUTPUT ;
    USE SIGNAL ;
    PORT
      LAYER M4 ;
        RECT  219.916 125.232 220 125.256 ;
    END
  END y[26]
  PIN y[27]
    DIRECTION OUTPUT ;
    USE SIGNAL ;
    PORT
      LAYER M4 ;
        RECT  219.916 125.28 220 125.304 ;
    END
  END y[27]
  PIN y[28]
    DIRECTION OUTPUT ;
    USE SIGNAL ;
    PORT
      LAYER M4 ;
        RECT  219.916 125.328 220 125.352 ;
    END
  END y[28]
  PIN y[29]
    DIRECTION OUTPUT ;
    USE SIGNAL ;
    PORT
      LAYER M4 ;
        RECT  219.916 125.376 220 125.4 ;
    END
  END y[29]
  PIN y[2]
    DIRECTION OUTPUT ;
    USE SIGNAL ;
    PORT
      LAYER M4 ;
        RECT  219.916 124.08 220 124.104 ;
    END
  END y[2]
  PIN y[30]
    DIRECTION OUTPUT ;
    USE SIGNAL ;
    PORT
      LAYER M4 ;
        RECT  219.916 125.424 220 125.448 ;
    END
  END y[30]
  PIN y[31]
    DIRECTION OUTPUT ;
    USE SIGNAL ;
    PORT
      LAYER M4 ;
        RECT  219.916 125.472 220 125.496 ;
    END
  END y[31]
  PIN y[3]
    DIRECTION OUTPUT ;
    USE SIGNAL ;
    PORT
      LAYER M4 ;
        RECT  219.916 124.128 220 124.152 ;
    END
  END y[3]
  PIN y[4]
    DIRECTION OUTPUT ;
    USE SIGNAL ;
    PORT
      LAYER M4 ;
        RECT  219.916 124.176 220 124.2 ;
    END
  END y[4]
  PIN y[5]
    DIRECTION OUTPUT ;
    USE SIGNAL ;
    PORT
      LAYER M4 ;
        RECT  219.916 124.224 220 124.248 ;
    END
  END y[5]
  PIN y[6]
    DIRECTION OUTPUT ;
    USE SIGNAL ;
    PORT
      LAYER M4 ;
        RECT  219.916 124.272 220 124.296 ;
    END
  END y[6]
  PIN y[7]
    DIRECTION OUTPUT ;
    USE SIGNAL ;
    PORT
      LAYER M4 ;
        RECT  219.916 124.32 220 124.344 ;
    END
  END y[7]
  PIN y[8]
    DIRECTION OUTPUT ;
    USE SIGNAL ;
    PORT
      LAYER M4 ;
        RECT  219.916 124.368 220 124.392 ;
    END
  END y[8]
  PIN y[9]
    DIRECTION OUTPUT ;
    USE SIGNAL ;
    PORT
      LAYER M4 ;
        RECT  219.916 124.416 220 124.44 ;
    END
  END y[9]
  PIN VDD
    DIRECTION INOUT ;
    USE POWER ;
    PORT
      LAYER M6 ;
        RECT  1.44 209.6 218.61 209.888 ;
        RECT  1.44 198.8 218.61 199.088 ;
        RECT  1.44 188 218.61 188.288 ;
        RECT  1.44 177.2 218.61 177.488 ;
        RECT  1.44 166.4 218.61 166.688 ;
        RECT  1.44 155.6 218.61 155.888 ;
        RECT  1.44 144.8 218.61 145.088 ;
        RECT  1.44 134 218.61 134.288 ;
        RECT  1.44 123.2 218.61 123.488 ;
        RECT  1.44 112.4 218.61 112.688 ;
        RECT  1.44 101.6 218.61 101.888 ;
        RECT  1.44 90.8 218.61 91.088 ;
        RECT  1.44 80 218.61 80.288 ;
        RECT  1.44 69.2 218.61 69.488 ;
        RECT  1.44 58.4 218.61 58.688 ;
        RECT  1.44 47.6 218.61 47.888 ;
        RECT  1.44 36.8 218.61 37.088 ;
        RECT  1.44 26 218.61 26.288 ;
        RECT  1.44 15.2 218.61 15.488 ;
        RECT  1.44 4.4 218.61 4.688 ;
        RECT  1.44 218.574 218.61 218.862 ;
        RECT  1.44 1.188 218.61 1.476 ;
    END
  END VDD
  PIN VSS
    DIRECTION INOUT ;
    USE GROUND ;
    PORT
      LAYER M6 ;
        RECT  1.44 209.216 218.61 209.504 ;
        RECT  1.44 198.416 218.61 198.704 ;
        RECT  1.44 187.616 218.61 187.904 ;
        RECT  1.44 176.816 218.61 177.104 ;
        RECT  1.44 166.016 218.61 166.304 ;
        RECT  1.44 155.216 218.61 155.504 ;
        RECT  1.44 144.416 218.61 144.704 ;
        RECT  1.44 133.616 218.61 133.904 ;
        RECT  1.44 122.816 218.61 123.104 ;
        RECT  1.44 112.016 218.61 112.304 ;
        RECT  1.44 101.216 218.61 101.504 ;
        RECT  1.44 90.416 218.61 90.704 ;
        RECT  1.44 79.616 218.61 79.904 ;
        RECT  1.44 68.816 218.61 69.104 ;
        RECT  1.44 58.016 218.61 58.304 ;
        RECT  1.44 47.216 218.61 47.504 ;
        RECT  1.44 36.416 218.61 36.704 ;
        RECT  1.44 25.616 218.61 25.904 ;
        RECT  1.44 14.816 218.61 15.104 ;
        RECT  1.44 4.016 218.61 4.304 ;
        RECT  1.632 218.19 218.418 218.478 ;
        RECT  1.632 1.572 218.418 1.86 ;
    END
  END VSS
  OBS
    LAYER RVTN ;
     RECT  0 0 220 220 ;
    LAYER RVTP ;
     RECT  0 0 220 220 ;
    LAYER M1 ;
     RECT  0 0 220 220 ;
    LAYER M2 ;
     RECT  0 0 220 220 ;
    LAYER M3 ;
     RECT  0 0 220 220 ;
    LAYER M4 ;
     RECT  0 0 220 220 ;
    LAYER M5 ;
     RECT  0 0 220 220 ;
    LAYER M6 ;
     RECT  0 0 220 220 ;
  END
END ot_gpu_tc_col
END LIBRARY
